VERSION 5.8 ;
BUSBITCHARS "[]" ;
DIVIDERCHAR "/" ;
UNITS
    DATABASE MICRONS 2000 ;
END UNITS

VIA adder_tester_via1_2_3200_1200_1_3_1040_1040
  VIARULE Via1_GEN_HH ;
  CUTSIZE 0.26 0.26 ;
  LAYERS Metal1 Via1 Metal2 ;
  CUTSPACING 0.26 0.26 ;
  ENCLOSURE 0.06 0.17 0.01 0.06 ;
  ROWCOL 1 3 ;
END adder_tester_via1_2_3200_1200_1_3_1040_1040

VIA adder_tester_via2_3_3200_1200_1_3_1040_1040
  VIARULE Via2_GEN_HH ;
  CUTSIZE 0.26 0.26 ;
  LAYERS Metal2 Via2 Metal3 ;
  CUTSPACING 0.26 0.26 ;
  ENCLOSURE 0.01 0.06 0.06 0.01 ;
  ROWCOL 1 3 ;
END adder_tester_via2_3_3200_1200_1_3_1040_1040

VIA adder_tester_via3_4_3200_1200_1_3_1040_1040
  VIARULE Via3_GEN_HH ;
  CUTSIZE 0.26 0.26 ;
  LAYERS Metal3 Via3 Metal4 ;
  CUTSPACING 0.26 0.26 ;
  ENCLOSURE 0.06 0.01 0.15 0.06 ;
  ROWCOL 1 3 ;
END adder_tester_via3_4_3200_1200_1_3_1040_1040

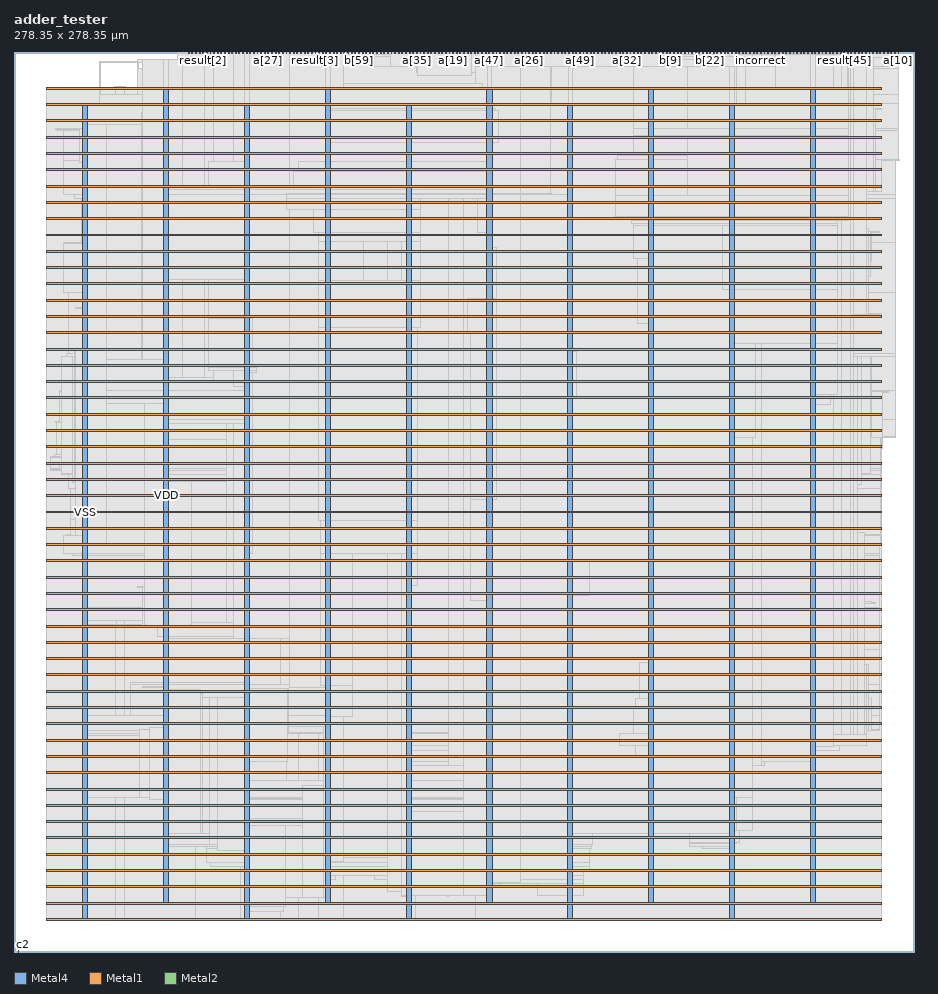
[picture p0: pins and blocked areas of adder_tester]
MACRO adder_tester
  FOREIGN adder_tester 0 0 ;
  CLASS BLOCK ;
  SIZE 278.35 BY 278.35 ;
  PIN VDD
    USE POWER ;
    DIRECTION INOUT ;
    PORT
      LAYER Metal4 ;
        RECT  246.28 14.82 247.88 267.42 ;
        RECT  196.28 14.82 197.88 267.42 ;
        RECT  146.28 14.82 147.88 267.42 ;
        RECT  96.28 14.82 97.88 267.42 ;
        RECT  46.28 14.82 47.88 267.42 ;
      LAYER Metal1 ;
        RECT  10.08 266.82 268.24 267.42 ;
        RECT  10.08 256.74 268.24 257.34 ;
        RECT  10.08 246.66 268.24 247.26 ;
        RECT  10.08 236.58 268.24 237.18 ;
        RECT  10.08 226.5 268.24 227.1 ;
        RECT  10.08 216.42 268.24 217.02 ;
        RECT  10.08 206.34 268.24 206.94 ;
        RECT  10.08 196.26 268.24 196.86 ;
        RECT  10.08 186.18 268.24 186.78 ;
        RECT  10.08 176.1 268.24 176.7 ;
        RECT  10.08 166.02 268.24 166.62 ;
        RECT  10.08 155.94 268.24 156.54 ;
        RECT  10.08 145.86 268.24 146.46 ;
        RECT  10.08 135.78 268.24 136.38 ;
        RECT  10.08 125.7 268.24 126.3 ;
        RECT  10.08 115.62 268.24 116.22 ;
        RECT  10.08 105.54 268.24 106.14 ;
        RECT  10.08 95.46 268.24 96.06 ;
        RECT  10.08 85.38 268.24 85.98 ;
        RECT  10.08 75.3 268.24 75.9 ;
        RECT  10.08 65.22 268.24 65.82 ;
        RECT  10.08 55.14 268.24 55.74 ;
        RECT  10.08 45.06 268.24 45.66 ;
        RECT  10.08 34.98 268.24 35.58 ;
        RECT  10.08 24.9 268.24 25.5 ;
        RECT  10.08 14.82 268.24 15.42 ;
      VIA 247.08 267.12 adder_tester_via3_4_3200_1200_1_3_1040_1040 ;
      VIA 247.08 267.12 adder_tester_via2_3_3200_1200_1_3_1040_1040 ;
      VIA 247.08 267.12 adder_tester_via1_2_3200_1200_1_3_1040_1040 ;
      VIA 247.08 257.04 adder_tester_via3_4_3200_1200_1_3_1040_1040 ;
      VIA 247.08 257.04 adder_tester_via2_3_3200_1200_1_3_1040_1040 ;
      VIA 247.08 257.04 adder_tester_via1_2_3200_1200_1_3_1040_1040 ;
      VIA 247.08 246.96 adder_tester_via3_4_3200_1200_1_3_1040_1040 ;
      VIA 247.08 246.96 adder_tester_via2_3_3200_1200_1_3_1040_1040 ;
      VIA 247.08 246.96 adder_tester_via1_2_3200_1200_1_3_1040_1040 ;
      VIA 247.08 236.88 adder_tester_via3_4_3200_1200_1_3_1040_1040 ;
      VIA 247.08 236.88 adder_tester_via2_3_3200_1200_1_3_1040_1040 ;
      VIA 247.08 236.88 adder_tester_via1_2_3200_1200_1_3_1040_1040 ;
      VIA 247.08 226.8 adder_tester_via3_4_3200_1200_1_3_1040_1040 ;
      VIA 247.08 226.8 adder_tester_via2_3_3200_1200_1_3_1040_1040 ;
      VIA 247.08 226.8 adder_tester_via1_2_3200_1200_1_3_1040_1040 ;
      VIA 247.08 216.72 adder_tester_via3_4_3200_1200_1_3_1040_1040 ;
      VIA 247.08 216.72 adder_tester_via2_3_3200_1200_1_3_1040_1040 ;
      VIA 247.08 216.72 adder_tester_via1_2_3200_1200_1_3_1040_1040 ;
      VIA 247.08 206.64 adder_tester_via3_4_3200_1200_1_3_1040_1040 ;
      VIA 247.08 206.64 adder_tester_via2_3_3200_1200_1_3_1040_1040 ;
      VIA 247.08 206.64 adder_tester_via1_2_3200_1200_1_3_1040_1040 ;
      VIA 247.08 196.56 adder_tester_via3_4_3200_1200_1_3_1040_1040 ;
      VIA 247.08 196.56 adder_tester_via2_3_3200_1200_1_3_1040_1040 ;
      VIA 247.08 196.56 adder_tester_via1_2_3200_1200_1_3_1040_1040 ;
      VIA 247.08 186.48 adder_tester_via3_4_3200_1200_1_3_1040_1040 ;
      VIA 247.08 186.48 adder_tester_via2_3_3200_1200_1_3_1040_1040 ;
      VIA 247.08 186.48 adder_tester_via1_2_3200_1200_1_3_1040_1040 ;
      VIA 247.08 176.4 adder_tester_via3_4_3200_1200_1_3_1040_1040 ;
      VIA 247.08 176.4 adder_tester_via2_3_3200_1200_1_3_1040_1040 ;
      VIA 247.08 176.4 adder_tester_via1_2_3200_1200_1_3_1040_1040 ;
      VIA 247.08 166.32 adder_tester_via3_4_3200_1200_1_3_1040_1040 ;
      VIA 247.08 166.32 adder_tester_via2_3_3200_1200_1_3_1040_1040 ;
      VIA 247.08 166.32 adder_tester_via1_2_3200_1200_1_3_1040_1040 ;
      VIA 247.08 156.24 adder_tester_via3_4_3200_1200_1_3_1040_1040 ;
      VIA 247.08 156.24 adder_tester_via2_3_3200_1200_1_3_1040_1040 ;
      VIA 247.08 156.24 adder_tester_via1_2_3200_1200_1_3_1040_1040 ;
      VIA 247.08 146.16 adder_tester_via3_4_3200_1200_1_3_1040_1040 ;
      VIA 247.08 146.16 adder_tester_via2_3_3200_1200_1_3_1040_1040 ;
      VIA 247.08 146.16 adder_tester_via1_2_3200_1200_1_3_1040_1040 ;
      VIA 247.08 136.08 adder_tester_via3_4_3200_1200_1_3_1040_1040 ;
      VIA 247.08 136.08 adder_tester_via2_3_3200_1200_1_3_1040_1040 ;
      VIA 247.08 136.08 adder_tester_via1_2_3200_1200_1_3_1040_1040 ;
      VIA 247.08 126 adder_tester_via3_4_3200_1200_1_3_1040_1040 ;
      VIA 247.08 126 adder_tester_via2_3_3200_1200_1_3_1040_1040 ;
      VIA 247.08 126 adder_tester_via1_2_3200_1200_1_3_1040_1040 ;
      VIA 247.08 115.92 adder_tester_via3_4_3200_1200_1_3_1040_1040 ;
      VIA 247.08 115.92 adder_tester_via2_3_3200_1200_1_3_1040_1040 ;
      VIA 247.08 115.92 adder_tester_via1_2_3200_1200_1_3_1040_1040 ;
      VIA 247.08 105.84 adder_tester_via3_4_3200_1200_1_3_1040_1040 ;
      VIA 247.08 105.84 adder_tester_via2_3_3200_1200_1_3_1040_1040 ;
      VIA 247.08 105.84 adder_tester_via1_2_3200_1200_1_3_1040_1040 ;
      VIA 247.08 95.76 adder_tester_via3_4_3200_1200_1_3_1040_1040 ;
      VIA 247.08 95.76 adder_tester_via2_3_3200_1200_1_3_1040_1040 ;
      VIA 247.08 95.76 adder_tester_via1_2_3200_1200_1_3_1040_1040 ;
      VIA 247.08 85.68 adder_tester_via3_4_3200_1200_1_3_1040_1040 ;
      VIA 247.08 85.68 adder_tester_via2_3_3200_1200_1_3_1040_1040 ;
      VIA 247.08 85.68 adder_tester_via1_2_3200_1200_1_3_1040_1040 ;
      VIA 247.08 75.6 adder_tester_via3_4_3200_1200_1_3_1040_1040 ;
      VIA 247.08 75.6 adder_tester_via2_3_3200_1200_1_3_1040_1040 ;
      VIA 247.08 75.6 adder_tester_via1_2_3200_1200_1_3_1040_1040 ;
      VIA 247.08 65.52 adder_tester_via3_4_3200_1200_1_3_1040_1040 ;
      VIA 247.08 65.52 adder_tester_via2_3_3200_1200_1_3_1040_1040 ;
      VIA 247.08 65.52 adder_tester_via1_2_3200_1200_1_3_1040_1040 ;
      VIA 247.08 55.44 adder_tester_via3_4_3200_1200_1_3_1040_1040 ;
      VIA 247.08 55.44 adder_tester_via2_3_3200_1200_1_3_1040_1040 ;
      VIA 247.08 55.44 adder_tester_via1_2_3200_1200_1_3_1040_1040 ;
      VIA 247.08 45.36 adder_tester_via3_4_3200_1200_1_3_1040_1040 ;
      VIA 247.08 45.36 adder_tester_via2_3_3200_1200_1_3_1040_1040 ;
      VIA 247.08 45.36 adder_tester_via1_2_3200_1200_1_3_1040_1040 ;
      VIA 247.08 35.28 adder_tester_via3_4_3200_1200_1_3_1040_1040 ;
      VIA 247.08 35.28 adder_tester_via2_3_3200_1200_1_3_1040_1040 ;
      VIA 247.08 35.28 adder_tester_via1_2_3200_1200_1_3_1040_1040 ;
      VIA 247.08 25.2 adder_tester_via3_4_3200_1200_1_3_1040_1040 ;
      VIA 247.08 25.2 adder_tester_via2_3_3200_1200_1_3_1040_1040 ;
      VIA 247.08 25.2 adder_tester_via1_2_3200_1200_1_3_1040_1040 ;
      VIA 247.08 15.12 adder_tester_via3_4_3200_1200_1_3_1040_1040 ;
      VIA 247.08 15.12 adder_tester_via2_3_3200_1200_1_3_1040_1040 ;
      VIA 247.08 15.12 adder_tester_via1_2_3200_1200_1_3_1040_1040 ;
      VIA 197.08 267.12 adder_tester_via3_4_3200_1200_1_3_1040_1040 ;
      VIA 197.08 267.12 adder_tester_via2_3_3200_1200_1_3_1040_1040 ;
      VIA 197.08 267.12 adder_tester_via1_2_3200_1200_1_3_1040_1040 ;
      VIA 197.08 257.04 adder_tester_via3_4_3200_1200_1_3_1040_1040 ;
      VIA 197.08 257.04 adder_tester_via2_3_3200_1200_1_3_1040_1040 ;
      VIA 197.08 257.04 adder_tester_via1_2_3200_1200_1_3_1040_1040 ;
      VIA 197.08 246.96 adder_tester_via3_4_3200_1200_1_3_1040_1040 ;
      VIA 197.08 246.96 adder_tester_via2_3_3200_1200_1_3_1040_1040 ;
      VIA 197.08 246.96 adder_tester_via1_2_3200_1200_1_3_1040_1040 ;
      VIA 197.08 236.88 adder_tester_via3_4_3200_1200_1_3_1040_1040 ;
      VIA 197.08 236.88 adder_tester_via2_3_3200_1200_1_3_1040_1040 ;
      VIA 197.08 236.88 adder_tester_via1_2_3200_1200_1_3_1040_1040 ;
      VIA 197.08 226.8 adder_tester_via3_4_3200_1200_1_3_1040_1040 ;
      VIA 197.08 226.8 adder_tester_via2_3_3200_1200_1_3_1040_1040 ;
      VIA 197.08 226.8 adder_tester_via1_2_3200_1200_1_3_1040_1040 ;
      VIA 197.08 216.72 adder_tester_via3_4_3200_1200_1_3_1040_1040 ;
      VIA 197.08 216.72 adder_tester_via2_3_3200_1200_1_3_1040_1040 ;
      VIA 197.08 216.72 adder_tester_via1_2_3200_1200_1_3_1040_1040 ;
      VIA 197.08 206.64 adder_tester_via3_4_3200_1200_1_3_1040_1040 ;
      VIA 197.08 206.64 adder_tester_via2_3_3200_1200_1_3_1040_1040 ;
      VIA 197.08 206.64 adder_tester_via1_2_3200_1200_1_3_1040_1040 ;
      VIA 197.08 196.56 adder_tester_via3_4_3200_1200_1_3_1040_1040 ;
      VIA 197.08 196.56 adder_tester_via2_3_3200_1200_1_3_1040_1040 ;
      VIA 197.08 196.56 adder_tester_via1_2_3200_1200_1_3_1040_1040 ;
      VIA 197.08 186.48 adder_tester_via3_4_3200_1200_1_3_1040_1040 ;
      VIA 197.08 186.48 adder_tester_via2_3_3200_1200_1_3_1040_1040 ;
      VIA 197.08 186.48 adder_tester_via1_2_3200_1200_1_3_1040_1040 ;
      VIA 197.08 176.4 adder_tester_via3_4_3200_1200_1_3_1040_1040 ;
      VIA 197.08 176.4 adder_tester_via2_3_3200_1200_1_3_1040_1040 ;
      VIA 197.08 176.4 adder_tester_via1_2_3200_1200_1_3_1040_1040 ;
      VIA 197.08 166.32 adder_tester_via3_4_3200_1200_1_3_1040_1040 ;
      VIA 197.08 166.32 adder_tester_via2_3_3200_1200_1_3_1040_1040 ;
      VIA 197.08 166.32 adder_tester_via1_2_3200_1200_1_3_1040_1040 ;
      VIA 197.08 156.24 adder_tester_via3_4_3200_1200_1_3_1040_1040 ;
      VIA 197.08 156.24 adder_tester_via2_3_3200_1200_1_3_1040_1040 ;
      VIA 197.08 156.24 adder_tester_via1_2_3200_1200_1_3_1040_1040 ;
      VIA 197.08 146.16 adder_tester_via3_4_3200_1200_1_3_1040_1040 ;
      VIA 197.08 146.16 adder_tester_via2_3_3200_1200_1_3_1040_1040 ;
      VIA 197.08 146.16 adder_tester_via1_2_3200_1200_1_3_1040_1040 ;
      VIA 197.08 136.08 adder_tester_via3_4_3200_1200_1_3_1040_1040 ;
      VIA 197.08 136.08 adder_tester_via2_3_3200_1200_1_3_1040_1040 ;
      VIA 197.08 136.08 adder_tester_via1_2_3200_1200_1_3_1040_1040 ;
      VIA 197.08 126 adder_tester_via3_4_3200_1200_1_3_1040_1040 ;
      VIA 197.08 126 adder_tester_via2_3_3200_1200_1_3_1040_1040 ;
      VIA 197.08 126 adder_tester_via1_2_3200_1200_1_3_1040_1040 ;
      VIA 197.08 115.92 adder_tester_via3_4_3200_1200_1_3_1040_1040 ;
      VIA 197.08 115.92 adder_tester_via2_3_3200_1200_1_3_1040_1040 ;
      VIA 197.08 115.92 adder_tester_via1_2_3200_1200_1_3_1040_1040 ;
      VIA 197.08 105.84 adder_tester_via3_4_3200_1200_1_3_1040_1040 ;
      VIA 197.08 105.84 adder_tester_via2_3_3200_1200_1_3_1040_1040 ;
      VIA 197.08 105.84 adder_tester_via1_2_3200_1200_1_3_1040_1040 ;
      VIA 197.08 95.76 adder_tester_via3_4_3200_1200_1_3_1040_1040 ;
      VIA 197.08 95.76 adder_tester_via2_3_3200_1200_1_3_1040_1040 ;
      VIA 197.08 95.76 adder_tester_via1_2_3200_1200_1_3_1040_1040 ;
      VIA 197.08 85.68 adder_tester_via3_4_3200_1200_1_3_1040_1040 ;
      VIA 197.08 85.68 adder_tester_via2_3_3200_1200_1_3_1040_1040 ;
      VIA 197.08 85.68 adder_tester_via1_2_3200_1200_1_3_1040_1040 ;
      VIA 197.08 75.6 adder_tester_via3_4_3200_1200_1_3_1040_1040 ;
      VIA 197.08 75.6 adder_tester_via2_3_3200_1200_1_3_1040_1040 ;
      VIA 197.08 75.6 adder_tester_via1_2_3200_1200_1_3_1040_1040 ;
      VIA 197.08 65.52 adder_tester_via3_4_3200_1200_1_3_1040_1040 ;
      VIA 197.08 65.52 adder_tester_via2_3_3200_1200_1_3_1040_1040 ;
      VIA 197.08 65.52 adder_tester_via1_2_3200_1200_1_3_1040_1040 ;
      VIA 197.08 55.44 adder_tester_via3_4_3200_1200_1_3_1040_1040 ;
      VIA 197.08 55.44 adder_tester_via2_3_3200_1200_1_3_1040_1040 ;
      VIA 197.08 55.44 adder_tester_via1_2_3200_1200_1_3_1040_1040 ;
      VIA 197.08 45.36 adder_tester_via3_4_3200_1200_1_3_1040_1040 ;
      VIA 197.08 45.36 adder_tester_via2_3_3200_1200_1_3_1040_1040 ;
      VIA 197.08 45.36 adder_tester_via1_2_3200_1200_1_3_1040_1040 ;
      VIA 197.08 35.28 adder_tester_via3_4_3200_1200_1_3_1040_1040 ;
      VIA 197.08 35.28 adder_tester_via2_3_3200_1200_1_3_1040_1040 ;
      VIA 197.08 35.28 adder_tester_via1_2_3200_1200_1_3_1040_1040 ;
      VIA 197.08 25.2 adder_tester_via3_4_3200_1200_1_3_1040_1040 ;
      VIA 197.08 25.2 adder_tester_via2_3_3200_1200_1_3_1040_1040 ;
      VIA 197.08 25.2 adder_tester_via1_2_3200_1200_1_3_1040_1040 ;
      VIA 197.08 15.12 adder_tester_via3_4_3200_1200_1_3_1040_1040 ;
      VIA 197.08 15.12 adder_tester_via2_3_3200_1200_1_3_1040_1040 ;
      VIA 197.08 15.12 adder_tester_via1_2_3200_1200_1_3_1040_1040 ;
      VIA 147.08 267.12 adder_tester_via3_4_3200_1200_1_3_1040_1040 ;
      VIA 147.08 267.12 adder_tester_via2_3_3200_1200_1_3_1040_1040 ;
      VIA 147.08 267.12 adder_tester_via1_2_3200_1200_1_3_1040_1040 ;
      VIA 147.08 257.04 adder_tester_via3_4_3200_1200_1_3_1040_1040 ;
      VIA 147.08 257.04 adder_tester_via2_3_3200_1200_1_3_1040_1040 ;
      VIA 147.08 257.04 adder_tester_via1_2_3200_1200_1_3_1040_1040 ;
      VIA 147.08 246.96 adder_tester_via3_4_3200_1200_1_3_1040_1040 ;
      VIA 147.08 246.96 adder_tester_via2_3_3200_1200_1_3_1040_1040 ;
      VIA 147.08 246.96 adder_tester_via1_2_3200_1200_1_3_1040_1040 ;
      VIA 147.08 236.88 adder_tester_via3_4_3200_1200_1_3_1040_1040 ;
      VIA 147.08 236.88 adder_tester_via2_3_3200_1200_1_3_1040_1040 ;
      VIA 147.08 236.88 adder_tester_via1_2_3200_1200_1_3_1040_1040 ;
      VIA 147.08 226.8 adder_tester_via3_4_3200_1200_1_3_1040_1040 ;
      VIA 147.08 226.8 adder_tester_via2_3_3200_1200_1_3_1040_1040 ;
      VIA 147.08 226.8 adder_tester_via1_2_3200_1200_1_3_1040_1040 ;
      VIA 147.08 216.72 adder_tester_via3_4_3200_1200_1_3_1040_1040 ;
      VIA 147.08 216.72 adder_tester_via2_3_3200_1200_1_3_1040_1040 ;
      VIA 147.08 216.72 adder_tester_via1_2_3200_1200_1_3_1040_1040 ;
      VIA 147.08 206.64 adder_tester_via3_4_3200_1200_1_3_1040_1040 ;
      VIA 147.08 206.64 adder_tester_via2_3_3200_1200_1_3_1040_1040 ;
      VIA 147.08 206.64 adder_tester_via1_2_3200_1200_1_3_1040_1040 ;
      VIA 147.08 196.56 adder_tester_via3_4_3200_1200_1_3_1040_1040 ;
      VIA 147.08 196.56 adder_tester_via2_3_3200_1200_1_3_1040_1040 ;
      VIA 147.08 196.56 adder_tester_via1_2_3200_1200_1_3_1040_1040 ;
      VIA 147.08 186.48 adder_tester_via3_4_3200_1200_1_3_1040_1040 ;
      VIA 147.08 186.48 adder_tester_via2_3_3200_1200_1_3_1040_1040 ;
      VIA 147.08 186.48 adder_tester_via1_2_3200_1200_1_3_1040_1040 ;
      VIA 147.08 176.4 adder_tester_via3_4_3200_1200_1_3_1040_1040 ;
      VIA 147.08 176.4 adder_tester_via2_3_3200_1200_1_3_1040_1040 ;
      VIA 147.08 176.4 adder_tester_via1_2_3200_1200_1_3_1040_1040 ;
      VIA 147.08 166.32 adder_tester_via3_4_3200_1200_1_3_1040_1040 ;
      VIA 147.08 166.32 adder_tester_via2_3_3200_1200_1_3_1040_1040 ;
      VIA 147.08 166.32 adder_tester_via1_2_3200_1200_1_3_1040_1040 ;
      VIA 147.08 156.24 adder_tester_via3_4_3200_1200_1_3_1040_1040 ;
      VIA 147.08 156.24 adder_tester_via2_3_3200_1200_1_3_1040_1040 ;
      VIA 147.08 156.24 adder_tester_via1_2_3200_1200_1_3_1040_1040 ;
      VIA 147.08 146.16 adder_tester_via3_4_3200_1200_1_3_1040_1040 ;
      VIA 147.08 146.16 adder_tester_via2_3_3200_1200_1_3_1040_1040 ;
      VIA 147.08 146.16 adder_tester_via1_2_3200_1200_1_3_1040_1040 ;
      VIA 147.08 136.08 adder_tester_via3_4_3200_1200_1_3_1040_1040 ;
      VIA 147.08 136.08 adder_tester_via2_3_3200_1200_1_3_1040_1040 ;
      VIA 147.08 136.08 adder_tester_via1_2_3200_1200_1_3_1040_1040 ;
      VIA 147.08 126 adder_tester_via3_4_3200_1200_1_3_1040_1040 ;
      VIA 147.08 126 adder_tester_via2_3_3200_1200_1_3_1040_1040 ;
      VIA 147.08 126 adder_tester_via1_2_3200_1200_1_3_1040_1040 ;
      VIA 147.08 115.92 adder_tester_via3_4_3200_1200_1_3_1040_1040 ;
      VIA 147.08 115.92 adder_tester_via2_3_3200_1200_1_3_1040_1040 ;
      VIA 147.08 115.92 adder_tester_via1_2_3200_1200_1_3_1040_1040 ;
      VIA 147.08 105.84 adder_tester_via3_4_3200_1200_1_3_1040_1040 ;
      VIA 147.08 105.84 adder_tester_via2_3_3200_1200_1_3_1040_1040 ;
      VIA 147.08 105.84 adder_tester_via1_2_3200_1200_1_3_1040_1040 ;
      VIA 147.08 95.76 adder_tester_via3_4_3200_1200_1_3_1040_1040 ;
      VIA 147.08 95.76 adder_tester_via2_3_3200_1200_1_3_1040_1040 ;
      VIA 147.08 95.76 adder_tester_via1_2_3200_1200_1_3_1040_1040 ;
      VIA 147.08 85.68 adder_tester_via3_4_3200_1200_1_3_1040_1040 ;
      VIA 147.08 85.68 adder_tester_via2_3_3200_1200_1_3_1040_1040 ;
      VIA 147.08 85.68 adder_tester_via1_2_3200_1200_1_3_1040_1040 ;
      VIA 147.08 75.6 adder_tester_via3_4_3200_1200_1_3_1040_1040 ;
      VIA 147.08 75.6 adder_tester_via2_3_3200_1200_1_3_1040_1040 ;
      VIA 147.08 75.6 adder_tester_via1_2_3200_1200_1_3_1040_1040 ;
      VIA 147.08 65.52 adder_tester_via3_4_3200_1200_1_3_1040_1040 ;
      VIA 147.08 65.52 adder_tester_via2_3_3200_1200_1_3_1040_1040 ;
      VIA 147.08 65.52 adder_tester_via1_2_3200_1200_1_3_1040_1040 ;
      VIA 147.08 55.44 adder_tester_via3_4_3200_1200_1_3_1040_1040 ;
      VIA 147.08 55.44 adder_tester_via2_3_3200_1200_1_3_1040_1040 ;
      VIA 147.08 55.44 adder_tester_via1_2_3200_1200_1_3_1040_1040 ;
      VIA 147.08 45.36 adder_tester_via3_4_3200_1200_1_3_1040_1040 ;
      VIA 147.08 45.36 adder_tester_via2_3_3200_1200_1_3_1040_1040 ;
      VIA 147.08 45.36 adder_tester_via1_2_3200_1200_1_3_1040_1040 ;
      VIA 147.08 35.28 adder_tester_via3_4_3200_1200_1_3_1040_1040 ;
      VIA 147.08 35.28 adder_tester_via2_3_3200_1200_1_3_1040_1040 ;
      VIA 147.08 35.28 adder_tester_via1_2_3200_1200_1_3_1040_1040 ;
      VIA 147.08 25.2 adder_tester_via3_4_3200_1200_1_3_1040_1040 ;
      VIA 147.08 25.2 adder_tester_via2_3_3200_1200_1_3_1040_1040 ;
      VIA 147.08 25.2 adder_tester_via1_2_3200_1200_1_3_1040_1040 ;
      VIA 147.08 15.12 adder_tester_via3_4_3200_1200_1_3_1040_1040 ;
      VIA 147.08 15.12 adder_tester_via2_3_3200_1200_1_3_1040_1040 ;
      VIA 147.08 15.12 adder_tester_via1_2_3200_1200_1_3_1040_1040 ;
      VIA 97.08 267.12 adder_tester_via3_4_3200_1200_1_3_1040_1040 ;
      VIA 97.08 267.12 adder_tester_via2_3_3200_1200_1_3_1040_1040 ;
      VIA 97.08 267.12 adder_tester_via1_2_3200_1200_1_3_1040_1040 ;
      VIA 97.08 257.04 adder_tester_via3_4_3200_1200_1_3_1040_1040 ;
      VIA 97.08 257.04 adder_tester_via2_3_3200_1200_1_3_1040_1040 ;
      VIA 97.08 257.04 adder_tester_via1_2_3200_1200_1_3_1040_1040 ;
      VIA 97.08 246.96 adder_tester_via3_4_3200_1200_1_3_1040_1040 ;
      VIA 97.08 246.96 adder_tester_via2_3_3200_1200_1_3_1040_1040 ;
      VIA 97.08 246.96 adder_tester_via1_2_3200_1200_1_3_1040_1040 ;
      VIA 97.08 236.88 adder_tester_via3_4_3200_1200_1_3_1040_1040 ;
      VIA 97.08 236.88 adder_tester_via2_3_3200_1200_1_3_1040_1040 ;
      VIA 97.08 236.88 adder_tester_via1_2_3200_1200_1_3_1040_1040 ;
      VIA 97.08 226.8 adder_tester_via3_4_3200_1200_1_3_1040_1040 ;
      VIA 97.08 226.8 adder_tester_via2_3_3200_1200_1_3_1040_1040 ;
      VIA 97.08 226.8 adder_tester_via1_2_3200_1200_1_3_1040_1040 ;
      VIA 97.08 216.72 adder_tester_via3_4_3200_1200_1_3_1040_1040 ;
      VIA 97.08 216.72 adder_tester_via2_3_3200_1200_1_3_1040_1040 ;
      VIA 97.08 216.72 adder_tester_via1_2_3200_1200_1_3_1040_1040 ;
      VIA 97.08 206.64 adder_tester_via3_4_3200_1200_1_3_1040_1040 ;
      VIA 97.08 206.64 adder_tester_via2_3_3200_1200_1_3_1040_1040 ;
      VIA 97.08 206.64 adder_tester_via1_2_3200_1200_1_3_1040_1040 ;
      VIA 97.08 196.56 adder_tester_via3_4_3200_1200_1_3_1040_1040 ;
      VIA 97.08 196.56 adder_tester_via2_3_3200_1200_1_3_1040_1040 ;
      VIA 97.08 196.56 adder_tester_via1_2_3200_1200_1_3_1040_1040 ;
      VIA 97.08 186.48 adder_tester_via3_4_3200_1200_1_3_1040_1040 ;
      VIA 97.08 186.48 adder_tester_via2_3_3200_1200_1_3_1040_1040 ;
      VIA 97.08 186.48 adder_tester_via1_2_3200_1200_1_3_1040_1040 ;
      VIA 97.08 176.4 adder_tester_via3_4_3200_1200_1_3_1040_1040 ;
      VIA 97.08 176.4 adder_tester_via2_3_3200_1200_1_3_1040_1040 ;
      VIA 97.08 176.4 adder_tester_via1_2_3200_1200_1_3_1040_1040 ;
      VIA 97.08 166.32 adder_tester_via3_4_3200_1200_1_3_1040_1040 ;
      VIA 97.08 166.32 adder_tester_via2_3_3200_1200_1_3_1040_1040 ;
      VIA 97.08 166.32 adder_tester_via1_2_3200_1200_1_3_1040_1040 ;
      VIA 97.08 156.24 adder_tester_via3_4_3200_1200_1_3_1040_1040 ;
      VIA 97.08 156.24 adder_tester_via2_3_3200_1200_1_3_1040_1040 ;
      VIA 97.08 156.24 adder_tester_via1_2_3200_1200_1_3_1040_1040 ;
      VIA 97.08 146.16 adder_tester_via3_4_3200_1200_1_3_1040_1040 ;
      VIA 97.08 146.16 adder_tester_via2_3_3200_1200_1_3_1040_1040 ;
      VIA 97.08 146.16 adder_tester_via1_2_3200_1200_1_3_1040_1040 ;
      VIA 97.08 136.08 adder_tester_via3_4_3200_1200_1_3_1040_1040 ;
      VIA 97.08 136.08 adder_tester_via2_3_3200_1200_1_3_1040_1040 ;
      VIA 97.08 136.08 adder_tester_via1_2_3200_1200_1_3_1040_1040 ;
      VIA 97.08 126 adder_tester_via3_4_3200_1200_1_3_1040_1040 ;
      VIA 97.08 126 adder_tester_via2_3_3200_1200_1_3_1040_1040 ;
      VIA 97.08 126 adder_tester_via1_2_3200_1200_1_3_1040_1040 ;
      VIA 97.08 115.92 adder_tester_via3_4_3200_1200_1_3_1040_1040 ;
      VIA 97.08 115.92 adder_tester_via2_3_3200_1200_1_3_1040_1040 ;
      VIA 97.08 115.92 adder_tester_via1_2_3200_1200_1_3_1040_1040 ;
      VIA 97.08 105.84 adder_tester_via3_4_3200_1200_1_3_1040_1040 ;
      VIA 97.08 105.84 adder_tester_via2_3_3200_1200_1_3_1040_1040 ;
      VIA 97.08 105.84 adder_tester_via1_2_3200_1200_1_3_1040_1040 ;
      VIA 97.08 95.76 adder_tester_via3_4_3200_1200_1_3_1040_1040 ;
      VIA 97.08 95.76 adder_tester_via2_3_3200_1200_1_3_1040_1040 ;
      VIA 97.08 95.76 adder_tester_via1_2_3200_1200_1_3_1040_1040 ;
      VIA 97.08 85.68 adder_tester_via3_4_3200_1200_1_3_1040_1040 ;
      VIA 97.08 85.68 adder_tester_via2_3_3200_1200_1_3_1040_1040 ;
      VIA 97.08 85.68 adder_tester_via1_2_3200_1200_1_3_1040_1040 ;
      VIA 97.08 75.6 adder_tester_via3_4_3200_1200_1_3_1040_1040 ;
      VIA 97.08 75.6 adder_tester_via2_3_3200_1200_1_3_1040_1040 ;
      VIA 97.08 75.6 adder_tester_via1_2_3200_1200_1_3_1040_1040 ;
      VIA 97.08 65.52 adder_tester_via3_4_3200_1200_1_3_1040_1040 ;
      VIA 97.08 65.52 adder_tester_via2_3_3200_1200_1_3_1040_1040 ;
      VIA 97.08 65.52 adder_tester_via1_2_3200_1200_1_3_1040_1040 ;
      VIA 97.08 55.44 adder_tester_via3_4_3200_1200_1_3_1040_1040 ;
      VIA 97.08 55.44 adder_tester_via2_3_3200_1200_1_3_1040_1040 ;
      VIA 97.08 55.44 adder_tester_via1_2_3200_1200_1_3_1040_1040 ;
      VIA 97.08 45.36 adder_tester_via3_4_3200_1200_1_3_1040_1040 ;
      VIA 97.08 45.36 adder_tester_via2_3_3200_1200_1_3_1040_1040 ;
      VIA 97.08 45.36 adder_tester_via1_2_3200_1200_1_3_1040_1040 ;
      VIA 97.08 35.28 adder_tester_via3_4_3200_1200_1_3_1040_1040 ;
      VIA 97.08 35.28 adder_tester_via2_3_3200_1200_1_3_1040_1040 ;
      VIA 97.08 35.28 adder_tester_via1_2_3200_1200_1_3_1040_1040 ;
      VIA 97.08 25.2 adder_tester_via3_4_3200_1200_1_3_1040_1040 ;
      VIA 97.08 25.2 adder_tester_via2_3_3200_1200_1_3_1040_1040 ;
      VIA 97.08 25.2 adder_tester_via1_2_3200_1200_1_3_1040_1040 ;
      VIA 97.08 15.12 adder_tester_via3_4_3200_1200_1_3_1040_1040 ;
      VIA 97.08 15.12 adder_tester_via2_3_3200_1200_1_3_1040_1040 ;
      VIA 97.08 15.12 adder_tester_via1_2_3200_1200_1_3_1040_1040 ;
      VIA 47.08 267.12 adder_tester_via3_4_3200_1200_1_3_1040_1040 ;
      VIA 47.08 267.12 adder_tester_via2_3_3200_1200_1_3_1040_1040 ;
      VIA 47.08 267.12 adder_tester_via1_2_3200_1200_1_3_1040_1040 ;
      VIA 47.08 257.04 adder_tester_via3_4_3200_1200_1_3_1040_1040 ;
      VIA 47.08 257.04 adder_tester_via2_3_3200_1200_1_3_1040_1040 ;
      VIA 47.08 257.04 adder_tester_via1_2_3200_1200_1_3_1040_1040 ;
      VIA 47.08 246.96 adder_tester_via3_4_3200_1200_1_3_1040_1040 ;
      VIA 47.08 246.96 adder_tester_via2_3_3200_1200_1_3_1040_1040 ;
      VIA 47.08 246.96 adder_tester_via1_2_3200_1200_1_3_1040_1040 ;
      VIA 47.08 236.88 adder_tester_via3_4_3200_1200_1_3_1040_1040 ;
      VIA 47.08 236.88 adder_tester_via2_3_3200_1200_1_3_1040_1040 ;
      VIA 47.08 236.88 adder_tester_via1_2_3200_1200_1_3_1040_1040 ;
      VIA 47.08 226.8 adder_tester_via3_4_3200_1200_1_3_1040_1040 ;
      VIA 47.08 226.8 adder_tester_via2_3_3200_1200_1_3_1040_1040 ;
      VIA 47.08 226.8 adder_tester_via1_2_3200_1200_1_3_1040_1040 ;
      VIA 47.08 216.72 adder_tester_via3_4_3200_1200_1_3_1040_1040 ;
      VIA 47.08 216.72 adder_tester_via2_3_3200_1200_1_3_1040_1040 ;
      VIA 47.08 216.72 adder_tester_via1_2_3200_1200_1_3_1040_1040 ;
      VIA 47.08 206.64 adder_tester_via3_4_3200_1200_1_3_1040_1040 ;
      VIA 47.08 206.64 adder_tester_via2_3_3200_1200_1_3_1040_1040 ;
      VIA 47.08 206.64 adder_tester_via1_2_3200_1200_1_3_1040_1040 ;
      VIA 47.08 196.56 adder_tester_via3_4_3200_1200_1_3_1040_1040 ;
      VIA 47.08 196.56 adder_tester_via2_3_3200_1200_1_3_1040_1040 ;
      VIA 47.08 196.56 adder_tester_via1_2_3200_1200_1_3_1040_1040 ;
      VIA 47.08 186.48 adder_tester_via3_4_3200_1200_1_3_1040_1040 ;
      VIA 47.08 186.48 adder_tester_via2_3_3200_1200_1_3_1040_1040 ;
      VIA 47.08 186.48 adder_tester_via1_2_3200_1200_1_3_1040_1040 ;
      VIA 47.08 176.4 adder_tester_via3_4_3200_1200_1_3_1040_1040 ;
      VIA 47.08 176.4 adder_tester_via2_3_3200_1200_1_3_1040_1040 ;
      VIA 47.08 176.4 adder_tester_via1_2_3200_1200_1_3_1040_1040 ;
      VIA 47.08 166.32 adder_tester_via3_4_3200_1200_1_3_1040_1040 ;
      VIA 47.08 166.32 adder_tester_via2_3_3200_1200_1_3_1040_1040 ;
      VIA 47.08 166.32 adder_tester_via1_2_3200_1200_1_3_1040_1040 ;
      VIA 47.08 156.24 adder_tester_via3_4_3200_1200_1_3_1040_1040 ;
      VIA 47.08 156.24 adder_tester_via2_3_3200_1200_1_3_1040_1040 ;
      VIA 47.08 156.24 adder_tester_via1_2_3200_1200_1_3_1040_1040 ;
      VIA 47.08 146.16 adder_tester_via3_4_3200_1200_1_3_1040_1040 ;
      VIA 47.08 146.16 adder_tester_via2_3_3200_1200_1_3_1040_1040 ;
      VIA 47.08 146.16 adder_tester_via1_2_3200_1200_1_3_1040_1040 ;
      VIA 47.08 136.08 adder_tester_via3_4_3200_1200_1_3_1040_1040 ;
      VIA 47.08 136.08 adder_tester_via2_3_3200_1200_1_3_1040_1040 ;
      VIA 47.08 136.08 adder_tester_via1_2_3200_1200_1_3_1040_1040 ;
      VIA 47.08 126 adder_tester_via3_4_3200_1200_1_3_1040_1040 ;
      VIA 47.08 126 adder_tester_via2_3_3200_1200_1_3_1040_1040 ;
      VIA 47.08 126 adder_tester_via1_2_3200_1200_1_3_1040_1040 ;
      VIA 47.08 115.92 adder_tester_via3_4_3200_1200_1_3_1040_1040 ;
      VIA 47.08 115.92 adder_tester_via2_3_3200_1200_1_3_1040_1040 ;
      VIA 47.08 115.92 adder_tester_via1_2_3200_1200_1_3_1040_1040 ;
      VIA 47.08 105.84 adder_tester_via3_4_3200_1200_1_3_1040_1040 ;
      VIA 47.08 105.84 adder_tester_via2_3_3200_1200_1_3_1040_1040 ;
      VIA 47.08 105.84 adder_tester_via1_2_3200_1200_1_3_1040_1040 ;
      VIA 47.08 95.76 adder_tester_via3_4_3200_1200_1_3_1040_1040 ;
      VIA 47.08 95.76 adder_tester_via2_3_3200_1200_1_3_1040_1040 ;
      VIA 47.08 95.76 adder_tester_via1_2_3200_1200_1_3_1040_1040 ;
      VIA 47.08 85.68 adder_tester_via3_4_3200_1200_1_3_1040_1040 ;
      VIA 47.08 85.68 adder_tester_via2_3_3200_1200_1_3_1040_1040 ;
      VIA 47.08 85.68 adder_tester_via1_2_3200_1200_1_3_1040_1040 ;
      VIA 47.08 75.6 adder_tester_via3_4_3200_1200_1_3_1040_1040 ;
      VIA 47.08 75.6 adder_tester_via2_3_3200_1200_1_3_1040_1040 ;
      VIA 47.08 75.6 adder_tester_via1_2_3200_1200_1_3_1040_1040 ;
      VIA 47.08 65.52 adder_tester_via3_4_3200_1200_1_3_1040_1040 ;
      VIA 47.08 65.52 adder_tester_via2_3_3200_1200_1_3_1040_1040 ;
      VIA 47.08 65.52 adder_tester_via1_2_3200_1200_1_3_1040_1040 ;
      VIA 47.08 55.44 adder_tester_via3_4_3200_1200_1_3_1040_1040 ;
      VIA 47.08 55.44 adder_tester_via2_3_3200_1200_1_3_1040_1040 ;
      VIA 47.08 55.44 adder_tester_via1_2_3200_1200_1_3_1040_1040 ;
      VIA 47.08 45.36 adder_tester_via3_4_3200_1200_1_3_1040_1040 ;
      VIA 47.08 45.36 adder_tester_via2_3_3200_1200_1_3_1040_1040 ;
      VIA 47.08 45.36 adder_tester_via1_2_3200_1200_1_3_1040_1040 ;
      VIA 47.08 35.28 adder_tester_via3_4_3200_1200_1_3_1040_1040 ;
      VIA 47.08 35.28 adder_tester_via2_3_3200_1200_1_3_1040_1040 ;
      VIA 47.08 35.28 adder_tester_via1_2_3200_1200_1_3_1040_1040 ;
      VIA 47.08 25.2 adder_tester_via3_4_3200_1200_1_3_1040_1040 ;
      VIA 47.08 25.2 adder_tester_via2_3_3200_1200_1_3_1040_1040 ;
      VIA 47.08 25.2 adder_tester_via1_2_3200_1200_1_3_1040_1040 ;
      VIA 47.08 15.12 adder_tester_via3_4_3200_1200_1_3_1040_1040 ;
      VIA 47.08 15.12 adder_tester_via2_3_3200_1200_1_3_1040_1040 ;
      VIA 47.08 15.12 adder_tester_via1_2_3200_1200_1_3_1040_1040 ;
    END
  END VDD
  PIN VSS
    USE GROUND ;
    DIRECTION INOUT ;
    PORT
      LAYER Metal4 ;
        RECT  221.28 9.78 222.88 262.38 ;
        RECT  171.28 9.78 172.88 262.38 ;
        RECT  121.28 9.78 122.88 262.38 ;
        RECT  71.28 9.78 72.88 262.38 ;
        RECT  21.28 9.78 22.88 262.38 ;
      LAYER Metal1 ;
        RECT  10.08 261.78 268.24 262.38 ;
        RECT  10.08 251.7 268.24 252.3 ;
        RECT  10.08 241.62 268.24 242.22 ;
        RECT  10.08 231.54 268.24 232.14 ;
        RECT  10.08 221.46 268.24 222.06 ;
        RECT  10.08 211.38 268.24 211.98 ;
        RECT  10.08 201.3 268.24 201.9 ;
        RECT  10.08 191.22 268.24 191.82 ;
        RECT  10.08 181.14 268.24 181.74 ;
        RECT  10.08 171.06 268.24 171.66 ;
        RECT  10.08 160.98 268.24 161.58 ;
        RECT  10.08 150.9 268.24 151.5 ;
        RECT  10.08 140.82 268.24 141.42 ;
        RECT  10.08 130.74 268.24 131.34 ;
        RECT  10.08 120.66 268.24 121.26 ;
        RECT  10.08 110.58 268.24 111.18 ;
        RECT  10.08 100.5 268.24 101.1 ;
        RECT  10.08 90.42 268.24 91.02 ;
        RECT  10.08 80.34 268.24 80.94 ;
        RECT  10.08 70.26 268.24 70.86 ;
        RECT  10.08 60.18 268.24 60.78 ;
        RECT  10.08 50.1 268.24 50.7 ;
        RECT  10.08 40.02 268.24 40.62 ;
        RECT  10.08 29.94 268.24 30.54 ;
        RECT  10.08 19.86 268.24 20.46 ;
        RECT  10.08 9.78 268.24 10.38 ;
      VIA 222.08 262.08 adder_tester_via3_4_3200_1200_1_3_1040_1040 ;
      VIA 222.08 262.08 adder_tester_via2_3_3200_1200_1_3_1040_1040 ;
      VIA 222.08 262.08 adder_tester_via1_2_3200_1200_1_3_1040_1040 ;
      VIA 222.08 252 adder_tester_via3_4_3200_1200_1_3_1040_1040 ;
      VIA 222.08 252 adder_tester_via2_3_3200_1200_1_3_1040_1040 ;
      VIA 222.08 252 adder_tester_via1_2_3200_1200_1_3_1040_1040 ;
      VIA 222.08 241.92 adder_tester_via3_4_3200_1200_1_3_1040_1040 ;
      VIA 222.08 241.92 adder_tester_via2_3_3200_1200_1_3_1040_1040 ;
      VIA 222.08 241.92 adder_tester_via1_2_3200_1200_1_3_1040_1040 ;
      VIA 222.08 231.84 adder_tester_via3_4_3200_1200_1_3_1040_1040 ;
      VIA 222.08 231.84 adder_tester_via2_3_3200_1200_1_3_1040_1040 ;
      VIA 222.08 231.84 adder_tester_via1_2_3200_1200_1_3_1040_1040 ;
      VIA 222.08 221.76 adder_tester_via3_4_3200_1200_1_3_1040_1040 ;
      VIA 222.08 221.76 adder_tester_via2_3_3200_1200_1_3_1040_1040 ;
      VIA 222.08 221.76 adder_tester_via1_2_3200_1200_1_3_1040_1040 ;
      VIA 222.08 211.68 adder_tester_via3_4_3200_1200_1_3_1040_1040 ;
      VIA 222.08 211.68 adder_tester_via2_3_3200_1200_1_3_1040_1040 ;
      VIA 222.08 211.68 adder_tester_via1_2_3200_1200_1_3_1040_1040 ;
      VIA 222.08 201.6 adder_tester_via3_4_3200_1200_1_3_1040_1040 ;
      VIA 222.08 201.6 adder_tester_via2_3_3200_1200_1_3_1040_1040 ;
      VIA 222.08 201.6 adder_tester_via1_2_3200_1200_1_3_1040_1040 ;
      VIA 222.08 191.52 adder_tester_via3_4_3200_1200_1_3_1040_1040 ;
      VIA 222.08 191.52 adder_tester_via2_3_3200_1200_1_3_1040_1040 ;
      VIA 222.08 191.52 adder_tester_via1_2_3200_1200_1_3_1040_1040 ;
      VIA 222.08 181.44 adder_tester_via3_4_3200_1200_1_3_1040_1040 ;
      VIA 222.08 181.44 adder_tester_via2_3_3200_1200_1_3_1040_1040 ;
      VIA 222.08 181.44 adder_tester_via1_2_3200_1200_1_3_1040_1040 ;
      VIA 222.08 171.36 adder_tester_via3_4_3200_1200_1_3_1040_1040 ;
      VIA 222.08 171.36 adder_tester_via2_3_3200_1200_1_3_1040_1040 ;
      VIA 222.08 171.36 adder_tester_via1_2_3200_1200_1_3_1040_1040 ;
      VIA 222.08 161.28 adder_tester_via3_4_3200_1200_1_3_1040_1040 ;
      VIA 222.08 161.28 adder_tester_via2_3_3200_1200_1_3_1040_1040 ;
      VIA 222.08 161.28 adder_tester_via1_2_3200_1200_1_3_1040_1040 ;
      VIA 222.08 151.2 adder_tester_via3_4_3200_1200_1_3_1040_1040 ;
      VIA 222.08 151.2 adder_tester_via2_3_3200_1200_1_3_1040_1040 ;
      VIA 222.08 151.2 adder_tester_via1_2_3200_1200_1_3_1040_1040 ;
      VIA 222.08 141.12 adder_tester_via3_4_3200_1200_1_3_1040_1040 ;
      VIA 222.08 141.12 adder_tester_via2_3_3200_1200_1_3_1040_1040 ;
      VIA 222.08 141.12 adder_tester_via1_2_3200_1200_1_3_1040_1040 ;
      VIA 222.08 131.04 adder_tester_via3_4_3200_1200_1_3_1040_1040 ;
      VIA 222.08 131.04 adder_tester_via2_3_3200_1200_1_3_1040_1040 ;
      VIA 222.08 131.04 adder_tester_via1_2_3200_1200_1_3_1040_1040 ;
      VIA 222.08 120.96 adder_tester_via3_4_3200_1200_1_3_1040_1040 ;
      VIA 222.08 120.96 adder_tester_via2_3_3200_1200_1_3_1040_1040 ;
      VIA 222.08 120.96 adder_tester_via1_2_3200_1200_1_3_1040_1040 ;
      VIA 222.08 110.88 adder_tester_via3_4_3200_1200_1_3_1040_1040 ;
      VIA 222.08 110.88 adder_tester_via2_3_3200_1200_1_3_1040_1040 ;
      VIA 222.08 110.88 adder_tester_via1_2_3200_1200_1_3_1040_1040 ;
      VIA 222.08 100.8 adder_tester_via3_4_3200_1200_1_3_1040_1040 ;
      VIA 222.08 100.8 adder_tester_via2_3_3200_1200_1_3_1040_1040 ;
      VIA 222.08 100.8 adder_tester_via1_2_3200_1200_1_3_1040_1040 ;
      VIA 222.08 90.72 adder_tester_via3_4_3200_1200_1_3_1040_1040 ;
      VIA 222.08 90.72 adder_tester_via2_3_3200_1200_1_3_1040_1040 ;
      VIA 222.08 90.72 adder_tester_via1_2_3200_1200_1_3_1040_1040 ;
      VIA 222.08 80.64 adder_tester_via3_4_3200_1200_1_3_1040_1040 ;
      VIA 222.08 80.64 adder_tester_via2_3_3200_1200_1_3_1040_1040 ;
      VIA 222.08 80.64 adder_tester_via1_2_3200_1200_1_3_1040_1040 ;
      VIA 222.08 70.56 adder_tester_via3_4_3200_1200_1_3_1040_1040 ;
      VIA 222.08 70.56 adder_tester_via2_3_3200_1200_1_3_1040_1040 ;
      VIA 222.08 70.56 adder_tester_via1_2_3200_1200_1_3_1040_1040 ;
      VIA 222.08 60.48 adder_tester_via3_4_3200_1200_1_3_1040_1040 ;
      VIA 222.08 60.48 adder_tester_via2_3_3200_1200_1_3_1040_1040 ;
      VIA 222.08 60.48 adder_tester_via1_2_3200_1200_1_3_1040_1040 ;
      VIA 222.08 50.4 adder_tester_via3_4_3200_1200_1_3_1040_1040 ;
      VIA 222.08 50.4 adder_tester_via2_3_3200_1200_1_3_1040_1040 ;
      VIA 222.08 50.4 adder_tester_via1_2_3200_1200_1_3_1040_1040 ;
      VIA 222.08 40.32 adder_tester_via3_4_3200_1200_1_3_1040_1040 ;
      VIA 222.08 40.32 adder_tester_via2_3_3200_1200_1_3_1040_1040 ;
      VIA 222.08 40.32 adder_tester_via1_2_3200_1200_1_3_1040_1040 ;
      VIA 222.08 30.24 adder_tester_via3_4_3200_1200_1_3_1040_1040 ;
      VIA 222.08 30.24 adder_tester_via2_3_3200_1200_1_3_1040_1040 ;
      VIA 222.08 30.24 adder_tester_via1_2_3200_1200_1_3_1040_1040 ;
      VIA 222.08 20.16 adder_tester_via3_4_3200_1200_1_3_1040_1040 ;
      VIA 222.08 20.16 adder_tester_via2_3_3200_1200_1_3_1040_1040 ;
      VIA 222.08 20.16 adder_tester_via1_2_3200_1200_1_3_1040_1040 ;
      VIA 222.08 10.08 adder_tester_via3_4_3200_1200_1_3_1040_1040 ;
      VIA 222.08 10.08 adder_tester_via2_3_3200_1200_1_3_1040_1040 ;
      VIA 222.08 10.08 adder_tester_via1_2_3200_1200_1_3_1040_1040 ;
      VIA 172.08 262.08 adder_tester_via3_4_3200_1200_1_3_1040_1040 ;
      VIA 172.08 262.08 adder_tester_via2_3_3200_1200_1_3_1040_1040 ;
      VIA 172.08 262.08 adder_tester_via1_2_3200_1200_1_3_1040_1040 ;
      VIA 172.08 252 adder_tester_via3_4_3200_1200_1_3_1040_1040 ;
      VIA 172.08 252 adder_tester_via2_3_3200_1200_1_3_1040_1040 ;
      VIA 172.08 252 adder_tester_via1_2_3200_1200_1_3_1040_1040 ;
      VIA 172.08 241.92 adder_tester_via3_4_3200_1200_1_3_1040_1040 ;
      VIA 172.08 241.92 adder_tester_via2_3_3200_1200_1_3_1040_1040 ;
      VIA 172.08 241.92 adder_tester_via1_2_3200_1200_1_3_1040_1040 ;
      VIA 172.08 231.84 adder_tester_via3_4_3200_1200_1_3_1040_1040 ;
      VIA 172.08 231.84 adder_tester_via2_3_3200_1200_1_3_1040_1040 ;
      VIA 172.08 231.84 adder_tester_via1_2_3200_1200_1_3_1040_1040 ;
      VIA 172.08 221.76 adder_tester_via3_4_3200_1200_1_3_1040_1040 ;
      VIA 172.08 221.76 adder_tester_via2_3_3200_1200_1_3_1040_1040 ;
      VIA 172.08 221.76 adder_tester_via1_2_3200_1200_1_3_1040_1040 ;
      VIA 172.08 211.68 adder_tester_via3_4_3200_1200_1_3_1040_1040 ;
      VIA 172.08 211.68 adder_tester_via2_3_3200_1200_1_3_1040_1040 ;
      VIA 172.08 211.68 adder_tester_via1_2_3200_1200_1_3_1040_1040 ;
      VIA 172.08 201.6 adder_tester_via3_4_3200_1200_1_3_1040_1040 ;
      VIA 172.08 201.6 adder_tester_via2_3_3200_1200_1_3_1040_1040 ;
      VIA 172.08 201.6 adder_tester_via1_2_3200_1200_1_3_1040_1040 ;
      VIA 172.08 191.52 adder_tester_via3_4_3200_1200_1_3_1040_1040 ;
      VIA 172.08 191.52 adder_tester_via2_3_3200_1200_1_3_1040_1040 ;
      VIA 172.08 191.52 adder_tester_via1_2_3200_1200_1_3_1040_1040 ;
      VIA 172.08 181.44 adder_tester_via3_4_3200_1200_1_3_1040_1040 ;
      VIA 172.08 181.44 adder_tester_via2_3_3200_1200_1_3_1040_1040 ;
      VIA 172.08 181.44 adder_tester_via1_2_3200_1200_1_3_1040_1040 ;
      VIA 172.08 171.36 adder_tester_via3_4_3200_1200_1_3_1040_1040 ;
      VIA 172.08 171.36 adder_tester_via2_3_3200_1200_1_3_1040_1040 ;
      VIA 172.08 171.36 adder_tester_via1_2_3200_1200_1_3_1040_1040 ;
      VIA 172.08 161.28 adder_tester_via3_4_3200_1200_1_3_1040_1040 ;
      VIA 172.08 161.28 adder_tester_via2_3_3200_1200_1_3_1040_1040 ;
      VIA 172.08 161.28 adder_tester_via1_2_3200_1200_1_3_1040_1040 ;
      VIA 172.08 151.2 adder_tester_via3_4_3200_1200_1_3_1040_1040 ;
      VIA 172.08 151.2 adder_tester_via2_3_3200_1200_1_3_1040_1040 ;
      VIA 172.08 151.2 adder_tester_via1_2_3200_1200_1_3_1040_1040 ;
      VIA 172.08 141.12 adder_tester_via3_4_3200_1200_1_3_1040_1040 ;
      VIA 172.08 141.12 adder_tester_via2_3_3200_1200_1_3_1040_1040 ;
      VIA 172.08 141.12 adder_tester_via1_2_3200_1200_1_3_1040_1040 ;
      VIA 172.08 131.04 adder_tester_via3_4_3200_1200_1_3_1040_1040 ;
      VIA 172.08 131.04 adder_tester_via2_3_3200_1200_1_3_1040_1040 ;
      VIA 172.08 131.04 adder_tester_via1_2_3200_1200_1_3_1040_1040 ;
      VIA 172.08 120.96 adder_tester_via3_4_3200_1200_1_3_1040_1040 ;
      VIA 172.08 120.96 adder_tester_via2_3_3200_1200_1_3_1040_1040 ;
      VIA 172.08 120.96 adder_tester_via1_2_3200_1200_1_3_1040_1040 ;
      VIA 172.08 110.88 adder_tester_via3_4_3200_1200_1_3_1040_1040 ;
      VIA 172.08 110.88 adder_tester_via2_3_3200_1200_1_3_1040_1040 ;
      VIA 172.08 110.88 adder_tester_via1_2_3200_1200_1_3_1040_1040 ;
      VIA 172.08 100.8 adder_tester_via3_4_3200_1200_1_3_1040_1040 ;
      VIA 172.08 100.8 adder_tester_via2_3_3200_1200_1_3_1040_1040 ;
      VIA 172.08 100.8 adder_tester_via1_2_3200_1200_1_3_1040_1040 ;
      VIA 172.08 90.72 adder_tester_via3_4_3200_1200_1_3_1040_1040 ;
      VIA 172.08 90.72 adder_tester_via2_3_3200_1200_1_3_1040_1040 ;
      VIA 172.08 90.72 adder_tester_via1_2_3200_1200_1_3_1040_1040 ;
      VIA 172.08 80.64 adder_tester_via3_4_3200_1200_1_3_1040_1040 ;
      VIA 172.08 80.64 adder_tester_via2_3_3200_1200_1_3_1040_1040 ;
      VIA 172.08 80.64 adder_tester_via1_2_3200_1200_1_3_1040_1040 ;
      VIA 172.08 70.56 adder_tester_via3_4_3200_1200_1_3_1040_1040 ;
      VIA 172.08 70.56 adder_tester_via2_3_3200_1200_1_3_1040_1040 ;
      VIA 172.08 70.56 adder_tester_via1_2_3200_1200_1_3_1040_1040 ;
      VIA 172.08 60.48 adder_tester_via3_4_3200_1200_1_3_1040_1040 ;
      VIA 172.08 60.48 adder_tester_via2_3_3200_1200_1_3_1040_1040 ;
      VIA 172.08 60.48 adder_tester_via1_2_3200_1200_1_3_1040_1040 ;
      VIA 172.08 50.4 adder_tester_via3_4_3200_1200_1_3_1040_1040 ;
      VIA 172.08 50.4 adder_tester_via2_3_3200_1200_1_3_1040_1040 ;
      VIA 172.08 50.4 adder_tester_via1_2_3200_1200_1_3_1040_1040 ;
      VIA 172.08 40.32 adder_tester_via3_4_3200_1200_1_3_1040_1040 ;
      VIA 172.08 40.32 adder_tester_via2_3_3200_1200_1_3_1040_1040 ;
      VIA 172.08 40.32 adder_tester_via1_2_3200_1200_1_3_1040_1040 ;
      VIA 172.08 30.24 adder_tester_via3_4_3200_1200_1_3_1040_1040 ;
      VIA 172.08 30.24 adder_tester_via2_3_3200_1200_1_3_1040_1040 ;
      VIA 172.08 30.24 adder_tester_via1_2_3200_1200_1_3_1040_1040 ;
      VIA 172.08 20.16 adder_tester_via3_4_3200_1200_1_3_1040_1040 ;
      VIA 172.08 20.16 adder_tester_via2_3_3200_1200_1_3_1040_1040 ;
      VIA 172.08 20.16 adder_tester_via1_2_3200_1200_1_3_1040_1040 ;
      VIA 172.08 10.08 adder_tester_via3_4_3200_1200_1_3_1040_1040 ;
      VIA 172.08 10.08 adder_tester_via2_3_3200_1200_1_3_1040_1040 ;
      VIA 172.08 10.08 adder_tester_via1_2_3200_1200_1_3_1040_1040 ;
      VIA 122.08 262.08 adder_tester_via3_4_3200_1200_1_3_1040_1040 ;
      VIA 122.08 262.08 adder_tester_via2_3_3200_1200_1_3_1040_1040 ;
      VIA 122.08 262.08 adder_tester_via1_2_3200_1200_1_3_1040_1040 ;
      VIA 122.08 252 adder_tester_via3_4_3200_1200_1_3_1040_1040 ;
      VIA 122.08 252 adder_tester_via2_3_3200_1200_1_3_1040_1040 ;
      VIA 122.08 252 adder_tester_via1_2_3200_1200_1_3_1040_1040 ;
      VIA 122.08 241.92 adder_tester_via3_4_3200_1200_1_3_1040_1040 ;
      VIA 122.08 241.92 adder_tester_via2_3_3200_1200_1_3_1040_1040 ;
      VIA 122.08 241.92 adder_tester_via1_2_3200_1200_1_3_1040_1040 ;
      VIA 122.08 231.84 adder_tester_via3_4_3200_1200_1_3_1040_1040 ;
      VIA 122.08 231.84 adder_tester_via2_3_3200_1200_1_3_1040_1040 ;
      VIA 122.08 231.84 adder_tester_via1_2_3200_1200_1_3_1040_1040 ;
      VIA 122.08 221.76 adder_tester_via3_4_3200_1200_1_3_1040_1040 ;
      VIA 122.08 221.76 adder_tester_via2_3_3200_1200_1_3_1040_1040 ;
      VIA 122.08 221.76 adder_tester_via1_2_3200_1200_1_3_1040_1040 ;
      VIA 122.08 211.68 adder_tester_via3_4_3200_1200_1_3_1040_1040 ;
      VIA 122.08 211.68 adder_tester_via2_3_3200_1200_1_3_1040_1040 ;
      VIA 122.08 211.68 adder_tester_via1_2_3200_1200_1_3_1040_1040 ;
      VIA 122.08 201.6 adder_tester_via3_4_3200_1200_1_3_1040_1040 ;
      VIA 122.08 201.6 adder_tester_via2_3_3200_1200_1_3_1040_1040 ;
      VIA 122.08 201.6 adder_tester_via1_2_3200_1200_1_3_1040_1040 ;
      VIA 122.08 191.52 adder_tester_via3_4_3200_1200_1_3_1040_1040 ;
      VIA 122.08 191.52 adder_tester_via2_3_3200_1200_1_3_1040_1040 ;
      VIA 122.08 191.52 adder_tester_via1_2_3200_1200_1_3_1040_1040 ;
      VIA 122.08 181.44 adder_tester_via3_4_3200_1200_1_3_1040_1040 ;
      VIA 122.08 181.44 adder_tester_via2_3_3200_1200_1_3_1040_1040 ;
      VIA 122.08 181.44 adder_tester_via1_2_3200_1200_1_3_1040_1040 ;
      VIA 122.08 171.36 adder_tester_via3_4_3200_1200_1_3_1040_1040 ;
      VIA 122.08 171.36 adder_tester_via2_3_3200_1200_1_3_1040_1040 ;
      VIA 122.08 171.36 adder_tester_via1_2_3200_1200_1_3_1040_1040 ;
      VIA 122.08 161.28 adder_tester_via3_4_3200_1200_1_3_1040_1040 ;
      VIA 122.08 161.28 adder_tester_via2_3_3200_1200_1_3_1040_1040 ;
      VIA 122.08 161.28 adder_tester_via1_2_3200_1200_1_3_1040_1040 ;
      VIA 122.08 151.2 adder_tester_via3_4_3200_1200_1_3_1040_1040 ;
      VIA 122.08 151.2 adder_tester_via2_3_3200_1200_1_3_1040_1040 ;
      VIA 122.08 151.2 adder_tester_via1_2_3200_1200_1_3_1040_1040 ;
      VIA 122.08 141.12 adder_tester_via3_4_3200_1200_1_3_1040_1040 ;
      VIA 122.08 141.12 adder_tester_via2_3_3200_1200_1_3_1040_1040 ;
      VIA 122.08 141.12 adder_tester_via1_2_3200_1200_1_3_1040_1040 ;
      VIA 122.08 131.04 adder_tester_via3_4_3200_1200_1_3_1040_1040 ;
      VIA 122.08 131.04 adder_tester_via2_3_3200_1200_1_3_1040_1040 ;
      VIA 122.08 131.04 adder_tester_via1_2_3200_1200_1_3_1040_1040 ;
      VIA 122.08 120.96 adder_tester_via3_4_3200_1200_1_3_1040_1040 ;
      VIA 122.08 120.96 adder_tester_via2_3_3200_1200_1_3_1040_1040 ;
      VIA 122.08 120.96 adder_tester_via1_2_3200_1200_1_3_1040_1040 ;
      VIA 122.08 110.88 adder_tester_via3_4_3200_1200_1_3_1040_1040 ;
      VIA 122.08 110.88 adder_tester_via2_3_3200_1200_1_3_1040_1040 ;
      VIA 122.08 110.88 adder_tester_via1_2_3200_1200_1_3_1040_1040 ;
      VIA 122.08 100.8 adder_tester_via3_4_3200_1200_1_3_1040_1040 ;
      VIA 122.08 100.8 adder_tester_via2_3_3200_1200_1_3_1040_1040 ;
      VIA 122.08 100.8 adder_tester_via1_2_3200_1200_1_3_1040_1040 ;
      VIA 122.08 90.72 adder_tester_via3_4_3200_1200_1_3_1040_1040 ;
      VIA 122.08 90.72 adder_tester_via2_3_3200_1200_1_3_1040_1040 ;
      VIA 122.08 90.72 adder_tester_via1_2_3200_1200_1_3_1040_1040 ;
      VIA 122.08 80.64 adder_tester_via3_4_3200_1200_1_3_1040_1040 ;
      VIA 122.08 80.64 adder_tester_via2_3_3200_1200_1_3_1040_1040 ;
      VIA 122.08 80.64 adder_tester_via1_2_3200_1200_1_3_1040_1040 ;
      VIA 122.08 70.56 adder_tester_via3_4_3200_1200_1_3_1040_1040 ;
      VIA 122.08 70.56 adder_tester_via2_3_3200_1200_1_3_1040_1040 ;
      VIA 122.08 70.56 adder_tester_via1_2_3200_1200_1_3_1040_1040 ;
      VIA 122.08 60.48 adder_tester_via3_4_3200_1200_1_3_1040_1040 ;
      VIA 122.08 60.48 adder_tester_via2_3_3200_1200_1_3_1040_1040 ;
      VIA 122.08 60.48 adder_tester_via1_2_3200_1200_1_3_1040_1040 ;
      VIA 122.08 50.4 adder_tester_via3_4_3200_1200_1_3_1040_1040 ;
      VIA 122.08 50.4 adder_tester_via2_3_3200_1200_1_3_1040_1040 ;
      VIA 122.08 50.4 adder_tester_via1_2_3200_1200_1_3_1040_1040 ;
      VIA 122.08 40.32 adder_tester_via3_4_3200_1200_1_3_1040_1040 ;
      VIA 122.08 40.32 adder_tester_via2_3_3200_1200_1_3_1040_1040 ;
      VIA 122.08 40.32 adder_tester_via1_2_3200_1200_1_3_1040_1040 ;
      VIA 122.08 30.24 adder_tester_via3_4_3200_1200_1_3_1040_1040 ;
      VIA 122.08 30.24 adder_tester_via2_3_3200_1200_1_3_1040_1040 ;
      VIA 122.08 30.24 adder_tester_via1_2_3200_1200_1_3_1040_1040 ;
      VIA 122.08 20.16 adder_tester_via3_4_3200_1200_1_3_1040_1040 ;
      VIA 122.08 20.16 adder_tester_via2_3_3200_1200_1_3_1040_1040 ;
      VIA 122.08 20.16 adder_tester_via1_2_3200_1200_1_3_1040_1040 ;
      VIA 122.08 10.08 adder_tester_via3_4_3200_1200_1_3_1040_1040 ;
      VIA 122.08 10.08 adder_tester_via2_3_3200_1200_1_3_1040_1040 ;
      VIA 122.08 10.08 adder_tester_via1_2_3200_1200_1_3_1040_1040 ;
      VIA 72.08 262.08 adder_tester_via3_4_3200_1200_1_3_1040_1040 ;
      VIA 72.08 262.08 adder_tester_via2_3_3200_1200_1_3_1040_1040 ;
      VIA 72.08 262.08 adder_tester_via1_2_3200_1200_1_3_1040_1040 ;
      VIA 72.08 252 adder_tester_via3_4_3200_1200_1_3_1040_1040 ;
      VIA 72.08 252 adder_tester_via2_3_3200_1200_1_3_1040_1040 ;
      VIA 72.08 252 adder_tester_via1_2_3200_1200_1_3_1040_1040 ;
      VIA 72.08 241.92 adder_tester_via3_4_3200_1200_1_3_1040_1040 ;
      VIA 72.08 241.92 adder_tester_via2_3_3200_1200_1_3_1040_1040 ;
      VIA 72.08 241.92 adder_tester_via1_2_3200_1200_1_3_1040_1040 ;
      VIA 72.08 231.84 adder_tester_via3_4_3200_1200_1_3_1040_1040 ;
      VIA 72.08 231.84 adder_tester_via2_3_3200_1200_1_3_1040_1040 ;
      VIA 72.08 231.84 adder_tester_via1_2_3200_1200_1_3_1040_1040 ;
      VIA 72.08 221.76 adder_tester_via3_4_3200_1200_1_3_1040_1040 ;
      VIA 72.08 221.76 adder_tester_via2_3_3200_1200_1_3_1040_1040 ;
      VIA 72.08 221.76 adder_tester_via1_2_3200_1200_1_3_1040_1040 ;
      VIA 72.08 211.68 adder_tester_via3_4_3200_1200_1_3_1040_1040 ;
      VIA 72.08 211.68 adder_tester_via2_3_3200_1200_1_3_1040_1040 ;
      VIA 72.08 211.68 adder_tester_via1_2_3200_1200_1_3_1040_1040 ;
      VIA 72.08 201.6 adder_tester_via3_4_3200_1200_1_3_1040_1040 ;
      VIA 72.08 201.6 adder_tester_via2_3_3200_1200_1_3_1040_1040 ;
      VIA 72.08 201.6 adder_tester_via1_2_3200_1200_1_3_1040_1040 ;
      VIA 72.08 191.52 adder_tester_via3_4_3200_1200_1_3_1040_1040 ;
      VIA 72.08 191.52 adder_tester_via2_3_3200_1200_1_3_1040_1040 ;
      VIA 72.08 191.52 adder_tester_via1_2_3200_1200_1_3_1040_1040 ;
      VIA 72.08 181.44 adder_tester_via3_4_3200_1200_1_3_1040_1040 ;
      VIA 72.08 181.44 adder_tester_via2_3_3200_1200_1_3_1040_1040 ;
      VIA 72.08 181.44 adder_tester_via1_2_3200_1200_1_3_1040_1040 ;
      VIA 72.08 171.36 adder_tester_via3_4_3200_1200_1_3_1040_1040 ;
      VIA 72.08 171.36 adder_tester_via2_3_3200_1200_1_3_1040_1040 ;
      VIA 72.08 171.36 adder_tester_via1_2_3200_1200_1_3_1040_1040 ;
      VIA 72.08 161.28 adder_tester_via3_4_3200_1200_1_3_1040_1040 ;
      VIA 72.08 161.28 adder_tester_via2_3_3200_1200_1_3_1040_1040 ;
      VIA 72.08 161.28 adder_tester_via1_2_3200_1200_1_3_1040_1040 ;
      VIA 72.08 151.2 adder_tester_via3_4_3200_1200_1_3_1040_1040 ;
      VIA 72.08 151.2 adder_tester_via2_3_3200_1200_1_3_1040_1040 ;
      VIA 72.08 151.2 adder_tester_via1_2_3200_1200_1_3_1040_1040 ;
      VIA 72.08 141.12 adder_tester_via3_4_3200_1200_1_3_1040_1040 ;
      VIA 72.08 141.12 adder_tester_via2_3_3200_1200_1_3_1040_1040 ;
      VIA 72.08 141.12 adder_tester_via1_2_3200_1200_1_3_1040_1040 ;
      VIA 72.08 131.04 adder_tester_via3_4_3200_1200_1_3_1040_1040 ;
      VIA 72.08 131.04 adder_tester_via2_3_3200_1200_1_3_1040_1040 ;
      VIA 72.08 131.04 adder_tester_via1_2_3200_1200_1_3_1040_1040 ;
      VIA 72.08 120.96 adder_tester_via3_4_3200_1200_1_3_1040_1040 ;
      VIA 72.08 120.96 adder_tester_via2_3_3200_1200_1_3_1040_1040 ;
      VIA 72.08 120.96 adder_tester_via1_2_3200_1200_1_3_1040_1040 ;
      VIA 72.08 110.88 adder_tester_via3_4_3200_1200_1_3_1040_1040 ;
      VIA 72.08 110.88 adder_tester_via2_3_3200_1200_1_3_1040_1040 ;
      VIA 72.08 110.88 adder_tester_via1_2_3200_1200_1_3_1040_1040 ;
      VIA 72.08 100.8 adder_tester_via3_4_3200_1200_1_3_1040_1040 ;
      VIA 72.08 100.8 adder_tester_via2_3_3200_1200_1_3_1040_1040 ;
      VIA 72.08 100.8 adder_tester_via1_2_3200_1200_1_3_1040_1040 ;
      VIA 72.08 90.72 adder_tester_via3_4_3200_1200_1_3_1040_1040 ;
      VIA 72.08 90.72 adder_tester_via2_3_3200_1200_1_3_1040_1040 ;
      VIA 72.08 90.72 adder_tester_via1_2_3200_1200_1_3_1040_1040 ;
      VIA 72.08 80.64 adder_tester_via3_4_3200_1200_1_3_1040_1040 ;
      VIA 72.08 80.64 adder_tester_via2_3_3200_1200_1_3_1040_1040 ;
      VIA 72.08 80.64 adder_tester_via1_2_3200_1200_1_3_1040_1040 ;
      VIA 72.08 70.56 adder_tester_via3_4_3200_1200_1_3_1040_1040 ;
      VIA 72.08 70.56 adder_tester_via2_3_3200_1200_1_3_1040_1040 ;
      VIA 72.08 70.56 adder_tester_via1_2_3200_1200_1_3_1040_1040 ;
      VIA 72.08 60.48 adder_tester_via3_4_3200_1200_1_3_1040_1040 ;
      VIA 72.08 60.48 adder_tester_via2_3_3200_1200_1_3_1040_1040 ;
      VIA 72.08 60.48 adder_tester_via1_2_3200_1200_1_3_1040_1040 ;
      VIA 72.08 50.4 adder_tester_via3_4_3200_1200_1_3_1040_1040 ;
      VIA 72.08 50.4 adder_tester_via2_3_3200_1200_1_3_1040_1040 ;
      VIA 72.08 50.4 adder_tester_via1_2_3200_1200_1_3_1040_1040 ;
      VIA 72.08 40.32 adder_tester_via3_4_3200_1200_1_3_1040_1040 ;
      VIA 72.08 40.32 adder_tester_via2_3_3200_1200_1_3_1040_1040 ;
      VIA 72.08 40.32 adder_tester_via1_2_3200_1200_1_3_1040_1040 ;
      VIA 72.08 30.24 adder_tester_via3_4_3200_1200_1_3_1040_1040 ;
      VIA 72.08 30.24 adder_tester_via2_3_3200_1200_1_3_1040_1040 ;
      VIA 72.08 30.24 adder_tester_via1_2_3200_1200_1_3_1040_1040 ;
      VIA 72.08 20.16 adder_tester_via3_4_3200_1200_1_3_1040_1040 ;
      VIA 72.08 20.16 adder_tester_via2_3_3200_1200_1_3_1040_1040 ;
      VIA 72.08 20.16 adder_tester_via1_2_3200_1200_1_3_1040_1040 ;
      VIA 72.08 10.08 adder_tester_via3_4_3200_1200_1_3_1040_1040 ;
      VIA 72.08 10.08 adder_tester_via2_3_3200_1200_1_3_1040_1040 ;
      VIA 72.08 10.08 adder_tester_via1_2_3200_1200_1_3_1040_1040 ;
      VIA 22.08 262.08 adder_tester_via3_4_3200_1200_1_3_1040_1040 ;
      VIA 22.08 262.08 adder_tester_via2_3_3200_1200_1_3_1040_1040 ;
      VIA 22.08 262.08 adder_tester_via1_2_3200_1200_1_3_1040_1040 ;
      VIA 22.08 252 adder_tester_via3_4_3200_1200_1_3_1040_1040 ;
      VIA 22.08 252 adder_tester_via2_3_3200_1200_1_3_1040_1040 ;
      VIA 22.08 252 adder_tester_via1_2_3200_1200_1_3_1040_1040 ;
      VIA 22.08 241.92 adder_tester_via3_4_3200_1200_1_3_1040_1040 ;
      VIA 22.08 241.92 adder_tester_via2_3_3200_1200_1_3_1040_1040 ;
      VIA 22.08 241.92 adder_tester_via1_2_3200_1200_1_3_1040_1040 ;
      VIA 22.08 231.84 adder_tester_via3_4_3200_1200_1_3_1040_1040 ;
      VIA 22.08 231.84 adder_tester_via2_3_3200_1200_1_3_1040_1040 ;
      VIA 22.08 231.84 adder_tester_via1_2_3200_1200_1_3_1040_1040 ;
      VIA 22.08 221.76 adder_tester_via3_4_3200_1200_1_3_1040_1040 ;
      VIA 22.08 221.76 adder_tester_via2_3_3200_1200_1_3_1040_1040 ;
      VIA 22.08 221.76 adder_tester_via1_2_3200_1200_1_3_1040_1040 ;
      VIA 22.08 211.68 adder_tester_via3_4_3200_1200_1_3_1040_1040 ;
      VIA 22.08 211.68 adder_tester_via2_3_3200_1200_1_3_1040_1040 ;
      VIA 22.08 211.68 adder_tester_via1_2_3200_1200_1_3_1040_1040 ;
      VIA 22.08 201.6 adder_tester_via3_4_3200_1200_1_3_1040_1040 ;
      VIA 22.08 201.6 adder_tester_via2_3_3200_1200_1_3_1040_1040 ;
      VIA 22.08 201.6 adder_tester_via1_2_3200_1200_1_3_1040_1040 ;
      VIA 22.08 191.52 adder_tester_via3_4_3200_1200_1_3_1040_1040 ;
      VIA 22.08 191.52 adder_tester_via2_3_3200_1200_1_3_1040_1040 ;
      VIA 22.08 191.52 adder_tester_via1_2_3200_1200_1_3_1040_1040 ;
      VIA 22.08 181.44 adder_tester_via3_4_3200_1200_1_3_1040_1040 ;
      VIA 22.08 181.44 adder_tester_via2_3_3200_1200_1_3_1040_1040 ;
      VIA 22.08 181.44 adder_tester_via1_2_3200_1200_1_3_1040_1040 ;
      VIA 22.08 171.36 adder_tester_via3_4_3200_1200_1_3_1040_1040 ;
      VIA 22.08 171.36 adder_tester_via2_3_3200_1200_1_3_1040_1040 ;
      VIA 22.08 171.36 adder_tester_via1_2_3200_1200_1_3_1040_1040 ;
      VIA 22.08 161.28 adder_tester_via3_4_3200_1200_1_3_1040_1040 ;
      VIA 22.08 161.28 adder_tester_via2_3_3200_1200_1_3_1040_1040 ;
      VIA 22.08 161.28 adder_tester_via1_2_3200_1200_1_3_1040_1040 ;
      VIA 22.08 151.2 adder_tester_via3_4_3200_1200_1_3_1040_1040 ;
      VIA 22.08 151.2 adder_tester_via2_3_3200_1200_1_3_1040_1040 ;
      VIA 22.08 151.2 adder_tester_via1_2_3200_1200_1_3_1040_1040 ;
      VIA 22.08 141.12 adder_tester_via3_4_3200_1200_1_3_1040_1040 ;
      VIA 22.08 141.12 adder_tester_via2_3_3200_1200_1_3_1040_1040 ;
      VIA 22.08 141.12 adder_tester_via1_2_3200_1200_1_3_1040_1040 ;
      VIA 22.08 131.04 adder_tester_via3_4_3200_1200_1_3_1040_1040 ;
      VIA 22.08 131.04 adder_tester_via2_3_3200_1200_1_3_1040_1040 ;
      VIA 22.08 131.04 adder_tester_via1_2_3200_1200_1_3_1040_1040 ;
      VIA 22.08 120.96 adder_tester_via3_4_3200_1200_1_3_1040_1040 ;
      VIA 22.08 120.96 adder_tester_via2_3_3200_1200_1_3_1040_1040 ;
      VIA 22.08 120.96 adder_tester_via1_2_3200_1200_1_3_1040_1040 ;
      VIA 22.08 110.88 adder_tester_via3_4_3200_1200_1_3_1040_1040 ;
      VIA 22.08 110.88 adder_tester_via2_3_3200_1200_1_3_1040_1040 ;
      VIA 22.08 110.88 adder_tester_via1_2_3200_1200_1_3_1040_1040 ;
      VIA 22.08 100.8 adder_tester_via3_4_3200_1200_1_3_1040_1040 ;
      VIA 22.08 100.8 adder_tester_via2_3_3200_1200_1_3_1040_1040 ;
      VIA 22.08 100.8 adder_tester_via1_2_3200_1200_1_3_1040_1040 ;
      VIA 22.08 90.72 adder_tester_via3_4_3200_1200_1_3_1040_1040 ;
      VIA 22.08 90.72 adder_tester_via2_3_3200_1200_1_3_1040_1040 ;
      VIA 22.08 90.72 adder_tester_via1_2_3200_1200_1_3_1040_1040 ;
      VIA 22.08 80.64 adder_tester_via3_4_3200_1200_1_3_1040_1040 ;
      VIA 22.08 80.64 adder_tester_via2_3_3200_1200_1_3_1040_1040 ;
      VIA 22.08 80.64 adder_tester_via1_2_3200_1200_1_3_1040_1040 ;
      VIA 22.08 70.56 adder_tester_via3_4_3200_1200_1_3_1040_1040 ;
      VIA 22.08 70.56 adder_tester_via2_3_3200_1200_1_3_1040_1040 ;
      VIA 22.08 70.56 adder_tester_via1_2_3200_1200_1_3_1040_1040 ;
      VIA 22.08 60.48 adder_tester_via3_4_3200_1200_1_3_1040_1040 ;
      VIA 22.08 60.48 adder_tester_via2_3_3200_1200_1_3_1040_1040 ;
      VIA 22.08 60.48 adder_tester_via1_2_3200_1200_1_3_1040_1040 ;
      VIA 22.08 50.4 adder_tester_via3_4_3200_1200_1_3_1040_1040 ;
      VIA 22.08 50.4 adder_tester_via2_3_3200_1200_1_3_1040_1040 ;
      VIA 22.08 50.4 adder_tester_via1_2_3200_1200_1_3_1040_1040 ;
      VIA 22.08 40.32 adder_tester_via3_4_3200_1200_1_3_1040_1040 ;
      VIA 22.08 40.32 adder_tester_via2_3_3200_1200_1_3_1040_1040 ;
      VIA 22.08 40.32 adder_tester_via1_2_3200_1200_1_3_1040_1040 ;
      VIA 22.08 30.24 adder_tester_via3_4_3200_1200_1_3_1040_1040 ;
      VIA 22.08 30.24 adder_tester_via2_3_3200_1200_1_3_1040_1040 ;
      VIA 22.08 30.24 adder_tester_via1_2_3200_1200_1_3_1040_1040 ;
      VIA 22.08 20.16 adder_tester_via3_4_3200_1200_1_3_1040_1040 ;
      VIA 22.08 20.16 adder_tester_via2_3_3200_1200_1_3_1040_1040 ;
      VIA 22.08 20.16 adder_tester_via1_2_3200_1200_1_3_1040_1040 ;
      VIA 22.08 10.08 adder_tester_via3_4_3200_1200_1_3_1040_1040 ;
      VIA 22.08 10.08 adder_tester_via2_3_3200_1200_1_3_1040_1040 ;
      VIA 22.08 10.08 adder_tester_via1_2_3200_1200_1_3_1040_1040 ;
    END
  END VSS
  PIN a[0]
    DIRECTION OUTPUT ;
    USE SIGNAL ;
    PORT
      LAYER Metal2 ;
        RECT  175.98 277.83 176.26 278.35 ;
    END
  END a[0]
  PIN a[10]
    DIRECTION OUTPUT ;
    USE SIGNAL ;
    PORT
      LAYER Metal2 ;
        RECT  273.42 277.83 273.7 278.35 ;
    END
  END a[10]
  PIN a[11]
    DIRECTION OUTPUT ;
    USE SIGNAL ;
    PORT
      LAYER Metal2 ;
        RECT  84.14 277.83 84.42 278.35 ;
    END
  END a[11]
  PIN a[12]
    DIRECTION OUTPUT ;
    USE SIGNAL ;
    PORT
      LAYER Metal2 ;
        RECT  141.26 277.83 141.54 278.35 ;
    END
  END a[12]
  PIN a[13]
    DIRECTION OUTPUT ;
    USE SIGNAL ;
    PORT
      LAYER Metal2 ;
        RECT  137.9 277.83 138.18 278.35 ;
    END
  END a[13]
  PIN a[14]
    DIRECTION OUTPUT ;
    USE SIGNAL ;
    PORT
      LAYER Metal2 ;
        RECT  83.02 277.83 83.3 278.35 ;
    END
  END a[14]
  PIN a[15]
    DIRECTION OUTPUT ;
    USE SIGNAL ;
    PORT
      LAYER Metal2 ;
        RECT  144.62 277.83 144.9 278.35 ;
    END
  END a[15]
  PIN a[16]
    DIRECTION OUTPUT ;
    USE SIGNAL ;
    PORT
      LAYER Metal2 ;
        RECT  145.74 277.83 146.02 278.35 ;
    END
  END a[16]
  PIN a[17]
    DIRECTION OUTPUT ;
    USE SIGNAL ;
    PORT
      LAYER Metal2 ;
        RECT  136.78 277.83 137.06 278.35 ;
    END
  END a[17]
  PIN a[18]
    DIRECTION OUTPUT ;
    USE SIGNAL ;
    PORT
      LAYER Metal2 ;
        RECT  81.9 277.83 82.18 278.35 ;
    END
  END a[18]
  PIN a[19]
    DIRECTION OUTPUT ;
    USE SIGNAL ;
    PORT
      LAYER Metal2 ;
        RECT  135.66 277.83 135.94 278.35 ;
    END
  END a[19]
  PIN a[1]
    DIRECTION OUTPUT ;
    USE SIGNAL ;
    PORT
      LAYER Metal2 ;
        RECT  149.1 277.83 149.38 278.35 ;
    END
  END a[1]
  PIN a[20]
    DIRECTION OUTPUT ;
    USE SIGNAL ;
    PORT
      LAYER Metal2 ;
        RECT  151.34 277.83 151.62 278.35 ;
    END
  END a[20]
  PIN a[21]
    DIRECTION OUTPUT ;
    USE SIGNAL ;
    PORT
      LAYER Metal2 ;
        RECT  150.22 277.83 150.5 278.35 ;
    END
  END a[21]
  PIN a[22]
    DIRECTION OUTPUT ;
    USE SIGNAL ;
    PORT
      LAYER Metal2 ;
        RECT  80.78 277.83 81.06 278.35 ;
    END
  END a[22]
  PIN a[23]
    DIRECTION OUTPUT ;
    USE SIGNAL ;
    PORT
      LAYER Metal2 ;
        RECT  134.54 277.83 134.82 278.35 ;
    END
  END a[23]
  PIN a[24]
    DIRECTION OUTPUT ;
    USE SIGNAL ;
    PORT
      LAYER Metal2 ;
        RECT  155.82 277.83 156.1 278.35 ;
    END
  END a[24]
  PIN a[25]
    DIRECTION OUTPUT ;
    USE SIGNAL ;
    PORT
      LAYER Metal2 ;
        RECT  79.66 277.83 79.94 278.35 ;
    END
  END a[25]
  PIN a[26]
    DIRECTION OUTPUT ;
    USE SIGNAL ;
    PORT
      LAYER Metal2 ;
        RECT  159.18 277.83 159.46 278.35 ;
    END
  END a[26]
  PIN a[27]
    DIRECTION OUTPUT ;
    USE SIGNAL ;
    PORT
      LAYER Metal2 ;
        RECT  78.54 277.83 78.82 278.35 ;
    END
  END a[27]
  PIN a[28]
    DIRECTION OUTPUT ;
    USE SIGNAL ;
    PORT
      LAYER Metal2 ;
        RECT  161.42 277.83 161.7 278.35 ;
    END
  END a[28]
  PIN a[29]
    DIRECTION OUTPUT ;
    USE SIGNAL ;
    PORT
      LAYER Metal2 ;
        RECT  162.54 277.83 162.82 278.35 ;
    END
  END a[29]
  PIN a[2]
    DIRECTION OUTPUT ;
    USE SIGNAL ;
    PORT
      LAYER Metal2 ;
        RECT  131.18 277.83 131.46 278.35 ;
    END
  END a[2]
  PIN a[30]
    DIRECTION OUTPUT ;
    USE SIGNAL ;
    PORT
      LAYER Metal2 ;
        RECT  163.66 277.83 163.94 278.35 ;
    END
  END a[30]
  PIN a[31]
    DIRECTION OUTPUT ;
    USE SIGNAL ;
    PORT
      LAYER Metal2 ;
        RECT  165.9 277.83 166.18 278.35 ;
    END
  END a[31]
  PIN a[32]
    DIRECTION OUTPUT ;
    USE SIGNAL ;
    PORT
      LAYER Metal2 ;
        RECT  189.42 277.83 189.7 278.35 ;
    END
  END a[32]
  PIN a[33]
    DIRECTION OUTPUT ;
    USE SIGNAL ;
    PORT
      LAYER Metal2 ;
        RECT  71.82 277.83 72.1 278.35 ;
    END
  END a[33]
  PIN a[34]
    DIRECTION OUTPUT ;
    USE SIGNAL ;
    PORT
      LAYER Metal2 ;
        RECT  77.42 277.83 77.7 278.35 ;
    END
  END a[34]
  PIN a[35]
    DIRECTION OUTPUT ;
    USE SIGNAL ;
    PORT
      LAYER Metal2 ;
        RECT  124.46 277.83 124.74 278.35 ;
    END
  END a[35]
  PIN a[36]
    DIRECTION OUTPUT ;
    USE SIGNAL ;
    PORT
      LAYER Metal2 ;
        RECT  130.06 277.83 130.34 278.35 ;
    END
  END a[36]
  PIN a[37]
    DIRECTION OUTPUT ;
    USE SIGNAL ;
    PORT
      LAYER Metal2 ;
        RECT  117.74 277.83 118.02 278.35 ;
    END
  END a[37]
  PIN a[38]
    DIRECTION OUTPUT ;
    USE SIGNAL ;
    PORT
      LAYER Metal2 ;
        RECT  75.18 277.83 75.46 278.35 ;
    END
  END a[38]
  PIN a[39]
    DIRECTION OUTPUT ;
    USE SIGNAL ;
    PORT
      LAYER Metal2 ;
        RECT  167.02 277.83 167.3 278.35 ;
    END
  END a[39]
  PIN a[3]
    DIRECTION OUTPUT ;
    USE SIGNAL ;
    PORT
      LAYER Metal2 ;
        RECT  168.14 277.83 168.42 278.35 ;
    END
  END a[3]
  PIN a[40]
    DIRECTION OUTPUT ;
    USE SIGNAL ;
    PORT
      LAYER Metal2 ;
        RECT  171.5 277.83 171.78 278.35 ;
    END
  END a[40]
  PIN a[41]
    DIRECTION OUTPUT ;
    USE SIGNAL ;
    PORT
      LAYER Metal2 ;
        RECT  125.58 277.83 125.86 278.35 ;
    END
  END a[41]
  PIN a[42]
    DIRECTION OUTPUT ;
    USE SIGNAL ;
    PORT
      LAYER Metal2 ;
        RECT  128.94 277.83 129.22 278.35 ;
    END
  END a[42]
  PIN a[43]
    DIRECTION OUTPUT ;
    USE SIGNAL ;
    PORT
      LAYER Metal2 ;
        RECT  76.3 277.83 76.58 278.35 ;
    END
  END a[43]
  PIN a[44]
    DIRECTION OUTPUT ;
    USE SIGNAL ;
    PORT
      LAYER Metal2 ;
        RECT  170.38 277.83 170.66 278.35 ;
    END
  END a[44]
  PIN a[45]
    DIRECTION OUTPUT ;
    USE SIGNAL ;
    PORT
      LAYER Metal2 ;
        RECT  74.06 277.83 74.34 278.35 ;
    END
  END a[45]
  PIN a[46]
    DIRECTION OUTPUT ;
    USE SIGNAL ;
    PORT
      LAYER Metal2 ;
        RECT  172.62 277.83 172.9 278.35 ;
    END
  END a[46]
  PIN a[47]
    DIRECTION OUTPUT ;
    USE SIGNAL ;
    PORT
      LAYER Metal2 ;
        RECT  146.86 277.83 147.14 278.35 ;
    END
  END a[47]
  PIN a[48]
    DIRECTION OUTPUT ;
    USE SIGNAL ;
    PORT
      LAYER Metal2 ;
        RECT  173.74 277.83 174.02 278.35 ;
    END
  END a[48]
  PIN a[49]
    DIRECTION OUTPUT ;
    USE SIGNAL ;
    PORT
      LAYER Metal2 ;
        RECT  174.86 277.83 175.14 278.35 ;
    END
  END a[49]
  PIN a[4]
    DIRECTION OUTPUT ;
    USE SIGNAL ;
    PORT
      LAYER Metal2 ;
        RECT  126.7 277.83 126.98 278.35 ;
    END
  END a[4]
  PIN a[50]
    DIRECTION OUTPUT ;
    USE SIGNAL ;
    PORT
      LAYER Metal2 ;
        RECT  122.22 277.83 122.5 278.35 ;
    END
  END a[50]
  PIN a[51]
    DIRECTION OUTPUT ;
    USE SIGNAL ;
    PORT
      LAYER Metal2 ;
        RECT  178.22 277.83 178.5 278.35 ;
    END
  END a[51]
  PIN a[52]
    DIRECTION OUTPUT ;
    USE SIGNAL ;
    PORT
      LAYER Metal2 ;
        RECT  179.34 277.83 179.62 278.35 ;
    END
  END a[52]
  PIN a[53]
    DIRECTION OUTPUT ;
    USE SIGNAL ;
    PORT
      LAYER Metal2 ;
        RECT  180.46 277.83 180.74 278.35 ;
    END
  END a[53]
  PIN a[54]
    DIRECTION OUTPUT ;
    USE SIGNAL ;
    PORT
      LAYER Metal2 ;
        RECT  72.94 277.83 73.22 278.35 ;
    END
  END a[54]
  PIN a[55]
    DIRECTION OUTPUT ;
    USE SIGNAL ;
    PORT
      LAYER Metal2 ;
        RECT  158.06 277.83 158.34 278.35 ;
    END
  END a[55]
  PIN a[56]
    DIRECTION OUTPUT ;
    USE SIGNAL ;
    PORT
      LAYER Metal2 ;
        RECT  182.7 277.83 182.98 278.35 ;
    END
  END a[56]
  PIN a[57]
    DIRECTION OUTPUT ;
    USE SIGNAL ;
    PORT
      LAYER Metal2 ;
        RECT  183.82 277.83 184.1 278.35 ;
    END
  END a[57]
  PIN a[58]
    DIRECTION OUTPUT ;
    USE SIGNAL ;
    PORT
      LAYER Metal2 ;
        RECT  184.94 277.83 185.22 278.35 ;
    END
  END a[58]
  PIN a[59]
    DIRECTION OUTPUT ;
    USE SIGNAL ;
    PORT
      LAYER Metal2 ;
        RECT  153.58 277.83 153.86 278.35 ;
    END
  END a[59]
  PIN a[5]
    DIRECTION OUTPUT ;
    USE SIGNAL ;
    PORT
      LAYER Metal2 ;
        RECT  140.14 277.83 140.42 278.35 ;
    END
  END a[5]
  PIN a[60]
    DIRECTION OUTPUT ;
    USE SIGNAL ;
    PORT
      LAYER Metal2 ;
        RECT  132.3 277.83 132.58 278.35 ;
    END
  END a[60]
  PIN a[61]
    DIRECTION OUTPUT ;
    USE SIGNAL ;
    PORT
      LAYER Metal2 ;
        RECT  123.34 277.83 123.62 278.35 ;
    END
  END a[61]
  PIN a[62]
    DIRECTION OUTPUT ;
    USE SIGNAL ;
    PORT
      LAYER Metal2 ;
        RECT  187.18 277.83 187.46 278.35 ;
    END
  END a[62]
  PIN a[63]
    DIRECTION OUTPUT ;
    USE SIGNAL ;
    PORT
      LAYER Metal2 ;
        RECT  188.3 277.83 188.58 278.35 ;
    END
  END a[63]
  PIN a[6]
    DIRECTION OUTPUT ;
    USE SIGNAL ;
    PORT
      LAYER Metal2 ;
        RECT  70.7 277.83 70.98 278.35 ;
    END
  END a[6]
  PIN a[7]
    DIRECTION OUTPUT ;
    USE SIGNAL ;
    PORT
      LAYER Metal2 ;
        RECT  154.7 277.83 154.98 278.35 ;
    END
  END a[7]
  PIN a[8]
    DIRECTION OUTPUT ;
    USE SIGNAL ;
    PORT
      LAYER Metal2 ;
        RECT  190.54 277.83 190.82 278.35 ;
    END
  END a[8]
  PIN a[9]
    DIRECTION OUTPUT ;
    USE SIGNAL ;
    PORT
      LAYER Metal2 ;
        RECT  191.66 277.83 191.94 278.35 ;
    END
  END a[9]
  PIN b[0]
    DIRECTION OUTPUT ;
    USE SIGNAL ;
    PORT
      LAYER Metal2 ;
        RECT  192.78 277.83 193.06 278.35 ;
    END
  END b[0]
  PIN b[10]
    DIRECTION OUTPUT ;
    USE SIGNAL ;
    PORT
      LAYER Metal2 ;
        RECT  121.1 277.83 121.38 278.35 ;
    END
  END b[10]
  PIN b[11]
    DIRECTION OUTPUT ;
    USE SIGNAL ;
    PORT
      LAYER Metal2 ;
        RECT  196.14 277.83 196.42 278.35 ;
    END
  END b[11]
  PIN b[12]
    DIRECTION OUTPUT ;
    USE SIGNAL ;
    PORT
      LAYER Metal2 ;
        RECT  197.26 277.83 197.54 278.35 ;
    END
  END b[12]
  PIN b[13]
    DIRECTION OUTPUT ;
    USE SIGNAL ;
    PORT
      LAYER Metal2 ;
        RECT  198.38 277.83 198.66 278.35 ;
    END
  END b[13]
  PIN b[14]
    DIRECTION OUTPUT ;
    USE SIGNAL ;
    PORT
      LAYER Metal2 ;
        RECT  118.86 277.83 119.14 278.35 ;
    END
  END b[14]
  PIN b[15]
    DIRECTION OUTPUT ;
    USE SIGNAL ;
    PORT
      LAYER Metal2 ;
        RECT  201.74 277.83 202.02 278.35 ;
    END
  END b[15]
  PIN b[16]
    DIRECTION OUTPUT ;
    USE SIGNAL ;
    PORT
      LAYER Metal2 ;
        RECT  67.34 277.83 67.62 278.35 ;
    END
  END b[16]
  PIN b[17]
    DIRECTION OUTPUT ;
    USE SIGNAL ;
    PORT
      LAYER Metal2 ;
        RECT  206.22 277.83 206.5 278.35 ;
    END
  END b[17]
  PIN b[18]
    DIRECTION OUTPUT ;
    USE SIGNAL ;
    PORT
      LAYER Metal2 ;
        RECT  66.22 277.83 66.5 278.35 ;
    END
  END b[18]
  PIN b[19]
    DIRECTION OUTPUT ;
    USE SIGNAL ;
    PORT
      LAYER Metal2 ;
        RECT  217.42 277.83 217.7 278.35 ;
    END
  END b[19]
  PIN b[1]
    DIRECTION OUTPUT ;
    USE SIGNAL ;
    PORT
      LAYER Metal2 ;
        RECT  209.58 277.83 209.86 278.35 ;
    END
  END b[1]
  PIN b[20]
    DIRECTION OUTPUT ;
    USE SIGNAL ;
    PORT
      LAYER Metal2 ;
        RECT  199.5 277.83 199.78 278.35 ;
    END
  END b[20]
  PIN b[21]
    DIRECTION OUTPUT ;
    USE SIGNAL ;
    PORT
      LAYER Metal2 ;
        RECT  115.5 277.83 115.78 278.35 ;
    END
  END b[21]
  PIN b[22]
    DIRECTION OUTPUT ;
    USE SIGNAL ;
    PORT
      LAYER Metal2 ;
        RECT  215.18 277.83 215.46 278.35 ;
    END
  END b[22]
  PIN b[23]
    DIRECTION OUTPUT ;
    USE SIGNAL ;
    PORT
      LAYER Metal2 ;
        RECT  212.94 277.83 213.22 278.35 ;
    END
  END b[23]
  PIN b[24]
    DIRECTION OUTPUT ;
    USE SIGNAL ;
    PORT
      LAYER Metal2 ;
        RECT  102.06 277.83 102.34 278.35 ;
    END
  END b[24]
  PIN b[25]
    DIRECTION OUTPUT ;
    USE SIGNAL ;
    PORT
      LAYER Metal2 ;
        RECT  113.26 277.83 113.54 278.35 ;
    END
  END b[25]
  PIN b[26]
    DIRECTION OUTPUT ;
    USE SIGNAL ;
    PORT
      LAYER Metal2 ;
        RECT  65.1 277.83 65.38 278.35 ;
    END
  END b[26]
  PIN b[27]
    DIRECTION OUTPUT ;
    USE SIGNAL ;
    PORT
      LAYER Metal2 ;
        RECT  112.14 277.83 112.42 278.35 ;
    END
  END b[27]
  PIN b[28]
    DIRECTION OUTPUT ;
    USE SIGNAL ;
    PORT
      LAYER Metal2 ;
        RECT  218.54 277.83 218.82 278.35 ;
    END
  END b[28]
  PIN b[29]
    DIRECTION OUTPUT ;
    USE SIGNAL ;
    PORT
      LAYER Metal2 ;
        RECT  195.02 277.83 195.3 278.35 ;
    END
  END b[29]
  PIN b[2]
    DIRECTION OUTPUT ;
    USE SIGNAL ;
    PORT
      LAYER Metal2 ;
        RECT  203.98 277.83 204.26 278.35 ;
    END
  END b[2]
  PIN b[30]
    DIRECTION OUTPUT ;
    USE SIGNAL ;
    PORT
      LAYER Metal2 ;
        RECT  111.02 277.83 111.3 278.35 ;
    END
  END b[30]
  PIN b[31]
    DIRECTION OUTPUT ;
    USE SIGNAL ;
    PORT
      LAYER Metal2 ;
        RECT  114.38 277.83 114.66 278.35 ;
    END
  END b[31]
  PIN b[32]
    DIRECTION OUTPUT ;
    USE SIGNAL ;
    PORT
      LAYER Metal2 ;
        RECT  216.3 277.83 216.58 278.35 ;
    END
  END b[32]
  PIN b[33]
    DIRECTION OUTPUT ;
    USE SIGNAL ;
    PORT
      LAYER Metal2 ;
        RECT  63.98 277.83 64.26 278.35 ;
    END
  END b[33]
  PIN b[34]
    DIRECTION OUTPUT ;
    USE SIGNAL ;
    PORT
      LAYER Metal2 ;
        RECT  219.66 277.83 219.94 278.35 ;
    END
  END b[34]
  PIN b[35]
    DIRECTION OUTPUT ;
    USE SIGNAL ;
    PORT
      LAYER Metal2 ;
        RECT  160.3 277.83 160.58 278.35 ;
    END
  END b[35]
  PIN b[36]
    DIRECTION OUTPUT ;
    USE SIGNAL ;
    PORT
      LAYER Metal2 ;
        RECT  200.62 277.83 200.9 278.35 ;
    END
  END b[36]
  PIN b[37]
    DIRECTION OUTPUT ;
    USE SIGNAL ;
    PORT
      LAYER Metal2 ;
        RECT  105.42 277.83 105.7 278.35 ;
    END
  END b[37]
  PIN b[38]
    DIRECTION OUTPUT ;
    USE SIGNAL ;
    PORT
      LAYER Metal2 ;
        RECT  220.78 277.83 221.06 278.35 ;
    END
  END b[38]
  PIN b[39]
    DIRECTION OUTPUT ;
    USE SIGNAL ;
    PORT
      LAYER Metal2 ;
        RECT  109.9 277.83 110.18 278.35 ;
    END
  END b[39]
  PIN b[3]
    DIRECTION OUTPUT ;
    USE SIGNAL ;
    PORT
      LAYER Metal2 ;
        RECT  214.06 277.83 214.34 278.35 ;
    END
  END b[3]
  PIN b[40]
    DIRECTION OUTPUT ;
    USE SIGNAL ;
    PORT
      LAYER Metal2 ;
        RECT  193.9 277.83 194.18 278.35 ;
    END
  END b[40]
  PIN b[41]
    DIRECTION OUTPUT ;
    USE SIGNAL ;
    PORT
      LAYER Metal2 ;
        RECT  119.98 277.83 120.26 278.35 ;
    END
  END b[41]
  PIN b[42]
    DIRECTION OUTPUT ;
    USE SIGNAL ;
    PORT
      LAYER Metal2 ;
        RECT  186.06 277.83 186.34 278.35 ;
    END
  END b[42]
  PIN b[43]
    DIRECTION OUTPUT ;
    USE SIGNAL ;
    PORT
      LAYER Metal2 ;
        RECT  221.9 277.83 222.18 278.35 ;
    END
  END b[43]
  PIN b[44]
    DIRECTION OUTPUT ;
    USE SIGNAL ;
    PORT
      LAYER Metal2 ;
        RECT  107.66 277.83 107.94 278.35 ;
    END
  END b[44]
  PIN b[45]
    DIRECTION OUTPUT ;
    USE SIGNAL ;
    PORT
      LAYER Metal2 ;
        RECT  210.7 277.83 210.98 278.35 ;
    END
  END b[45]
  PIN b[46]
    DIRECTION OUTPUT ;
    USE SIGNAL ;
    PORT
      LAYER Metal2 ;
        RECT  181.58 277.83 181.86 278.35 ;
    END
  END b[46]
  PIN b[47]
    DIRECTION OUTPUT ;
    USE SIGNAL ;
    PORT
      LAYER Metal2 ;
        RECT  68.46 277.83 68.74 278.35 ;
    END
  END b[47]
  PIN b[48]
    DIRECTION OUTPUT ;
    USE SIGNAL ;
    PORT
      LAYER Metal2 ;
        RECT  69.58 277.83 69.86 278.35 ;
    END
  END b[48]
  PIN b[49]
    DIRECTION OUTPUT ;
    USE SIGNAL ;
    PORT
      LAYER Metal2 ;
        RECT  211.82 277.83 212.1 278.35 ;
    END
  END b[49]
  PIN b[4]
    DIRECTION OUTPUT ;
    USE SIGNAL ;
    PORT
      LAYER Metal2 ;
        RECT  108.78 277.83 109.06 278.35 ;
    END
  END b[4]
  PIN b[50]
    DIRECTION OUTPUT ;
    USE SIGNAL ;
    PORT
      LAYER Metal2 ;
        RECT  62.86 277.83 63.14 278.35 ;
    END
  END b[50]
  PIN b[51]
    DIRECTION OUTPUT ;
    USE SIGNAL ;
    PORT
      LAYER Metal2 ;
        RECT  224.14 277.83 224.42 278.35 ;
    END
  END b[51]
  PIN b[52]
    DIRECTION OUTPUT ;
    USE SIGNAL ;
    PORT
      LAYER Metal2 ;
        RECT  225.26 277.83 225.54 278.35 ;
    END
  END b[52]
  PIN b[53]
    DIRECTION OUTPUT ;
    USE SIGNAL ;
    PORT
      LAYER Metal2 ;
        RECT  116.62 277.83 116.9 278.35 ;
    END
  END b[53]
  PIN b[54]
    DIRECTION OUTPUT ;
    USE SIGNAL ;
    PORT
      LAYER Metal2 ;
        RECT  169.26 277.83 169.54 278.35 ;
    END
  END b[54]
  PIN b[55]
    DIRECTION OUTPUT ;
    USE SIGNAL ;
    PORT
      LAYER Metal2 ;
        RECT  227.5 277.83 227.78 278.35 ;
    END
  END b[55]
  PIN b[56]
    DIRECTION OUTPUT ;
    USE SIGNAL ;
    PORT
      LAYER Metal2 ;
        RECT  223.02 277.83 223.3 278.35 ;
    END
  END b[56]
  PIN b[57]
    DIRECTION OUTPUT ;
    USE SIGNAL ;
    PORT
      LAYER Metal2 ;
        RECT  226.38 277.83 226.66 278.35 ;
    END
  END b[57]
  PIN b[58]
    DIRECTION OUTPUT ;
    USE SIGNAL ;
    PORT
      LAYER Metal2 ;
        RECT  205.1 277.83 205.38 278.35 ;
    END
  END b[58]
  PIN b[59]
    DIRECTION OUTPUT ;
    USE SIGNAL ;
    PORT
      LAYER Metal2 ;
        RECT  106.54 277.83 106.82 278.35 ;
    END
  END b[59]
  PIN b[5]
    DIRECTION OUTPUT ;
    USE SIGNAL ;
    PORT
      LAYER Metal2 ;
        RECT  164.78 277.83 165.06 278.35 ;
    END
  END b[5]
  PIN b[60]
    DIRECTION OUTPUT ;
    USE SIGNAL ;
    PORT
      LAYER Metal2 ;
        RECT  208.46 277.83 208.74 278.35 ;
    END
  END b[60]
  PIN b[61]
    DIRECTION OUTPUT ;
    USE SIGNAL ;
    PORT
      LAYER Metal2 ;
        RECT  61.74 277.83 62.02 278.35 ;
    END
  END b[61]
  PIN b[62]
    DIRECTION OUTPUT ;
    USE SIGNAL ;
    PORT
      LAYER Metal2 ;
        RECT  152.46 277.83 152.74 278.35 ;
    END
  END b[62]
  PIN b[63]
    DIRECTION OUTPUT ;
    USE SIGNAL ;
    PORT
      LAYER Metal2 ;
        RECT  104.3 277.83 104.58 278.35 ;
    END
  END b[63]
  PIN b[6]
    DIRECTION OUTPUT ;
    USE SIGNAL ;
    PORT
      LAYER Metal2 ;
        RECT  228.62 277.83 228.9 278.35 ;
    END
  END b[6]
  PIN b[7]
    DIRECTION OUTPUT ;
    USE SIGNAL ;
    PORT
      LAYER Metal2 ;
        RECT  207.34 277.83 207.62 278.35 ;
    END
  END b[7]
  PIN b[8]
    DIRECTION OUTPUT ;
    USE SIGNAL ;
    PORT
      LAYER Metal2 ;
        RECT  147.98 277.83 148.26 278.35 ;
    END
  END b[8]
  PIN b[9]
    DIRECTION OUTPUT ;
    USE SIGNAL ;
    PORT
      LAYER Metal2 ;
        RECT  202.86 277.83 203.14 278.35 ;
    END
  END b[9]
  PIN c1
    DIRECTION INPUT ;
    USE SIGNAL ;
    PORT
      LAYER Metal2 ;
        RECT  229.74 277.83 230.02 278.35 ;
    END
  END c1
  PIN c2
    DIRECTION INPUT ;
    USE SIGNAL ;
    PORT
      LAYER Metal2 ;
        RECT  1.26 0 1.54 0.52 ;
    END
  END c2
  PIN cin
    DIRECTION OUTPUT ;
    USE SIGNAL ;
    PORT
      LAYER Metal2 ;
        RECT  103.18 277.83 103.46 278.35 ;
    END
  END cin
  PIN correct
    DIRECTION OUTPUT ;
    USE SIGNAL ;
    PORT
      LAYER Metal2 ;
        RECT  143.5 277.83 143.78 278.35 ;
    END
  END correct
  PIN incorrect
    DIRECTION OUTPUT ;
    USE SIGNAL ;
    PORT
      LAYER Metal2 ;
        RECT  230.86 277.83 231.14 278.35 ;
    END
  END incorrect
  PIN result[0]
    DIRECTION INPUT ;
    USE SIGNAL ;
    PORT
      LAYER Metal2 ;
        RECT  139.02 277.83 139.3 278.35 ;
    END
  END result[0]
  PIN result[10]
    DIRECTION INPUT ;
    USE SIGNAL ;
    PORT
      LAYER Metal2 ;
        RECT  60.62 277.83 60.9 278.35 ;
    END
  END result[10]
  PIN result[11]
    DIRECTION INPUT ;
    USE SIGNAL ;
    PORT
      LAYER Metal2 ;
        RECT  231.98 277.83 232.26 278.35 ;
    END
  END result[11]
  PIN result[12]
    DIRECTION INPUT ;
    USE SIGNAL ;
    PORT
      LAYER Metal2 ;
        RECT  233.1 277.83 233.38 278.35 ;
    END
  END result[12]
  PIN result[13]
    DIRECTION INPUT ;
    USE SIGNAL ;
    PORT
      LAYER Metal2 ;
        RECT  234.22 277.83 234.5 278.35 ;
    END
  END result[13]
  PIN result[14]
    DIRECTION INPUT ;
    USE SIGNAL ;
    PORT
      LAYER Metal2 ;
        RECT  100.94 277.83 101.22 278.35 ;
    END
  END result[14]
  PIN result[15]
    DIRECTION INPUT ;
    USE SIGNAL ;
    PORT
      LAYER Metal2 ;
        RECT  235.34 277.83 235.62 278.35 ;
    END
  END result[15]
  PIN result[16]
    DIRECTION INPUT ;
    USE SIGNAL ;
    PORT
      LAYER Metal2 ;
        RECT  236.46 277.83 236.74 278.35 ;
    END
  END result[16]
  PIN result[17]
    DIRECTION INPUT ;
    USE SIGNAL ;
    PORT
      LAYER Metal2 ;
        RECT  237.58 277.83 237.86 278.35 ;
    END
  END result[17]
  PIN result[18]
    DIRECTION INPUT ;
    USE SIGNAL ;
    PORT
      LAYER Metal2 ;
        RECT  99.82 277.83 100.1 278.35 ;
    END
  END result[18]
  PIN result[19]
    DIRECTION INPUT ;
    USE SIGNAL ;
    PORT
      LAYER Metal2 ;
        RECT  238.7 277.83 238.98 278.35 ;
    END
  END result[19]
  PIN result[1]
    DIRECTION INPUT ;
    USE SIGNAL ;
    PORT
      LAYER Metal2 ;
        RECT  59.5 277.83 59.78 278.35 ;
    END
  END result[1]
  PIN result[20]
    DIRECTION INPUT ;
    USE SIGNAL ;
    PORT
      LAYER Metal2 ;
        RECT  239.82 277.83 240.1 278.35 ;
    END
  END result[20]
  PIN result[21]
    DIRECTION INPUT ;
    USE SIGNAL ;
    PORT
      LAYER Metal2 ;
        RECT  98.7 277.83 98.98 278.35 ;
    END
  END result[21]
  PIN result[22]
    DIRECTION INPUT ;
    USE SIGNAL ;
    PORT
      LAYER Metal2 ;
        RECT  240.94 277.83 241.22 278.35 ;
    END
  END result[22]
  PIN result[23]
    DIRECTION INPUT ;
    USE SIGNAL ;
    PORT
      LAYER Metal2 ;
        RECT  242.06 277.83 242.34 278.35 ;
    END
  END result[23]
  PIN result[24]
    DIRECTION INPUT ;
    USE SIGNAL ;
    PORT
      LAYER Metal2 ;
        RECT  243.18 277.83 243.46 278.35 ;
    END
  END result[24]
  PIN result[25]
    DIRECTION INPUT ;
    USE SIGNAL ;
    PORT
      LAYER Metal2 ;
        RECT  97.58 277.83 97.86 278.35 ;
    END
  END result[25]
  PIN result[26]
    DIRECTION INPUT ;
    USE SIGNAL ;
    PORT
      LAYER Metal2 ;
        RECT  244.3 277.83 244.58 278.35 ;
    END
  END result[26]
  PIN result[27]
    DIRECTION INPUT ;
    USE SIGNAL ;
    PORT
      LAYER Metal2 ;
        RECT  245.42 277.83 245.7 278.35 ;
    END
  END result[27]
  PIN result[28]
    DIRECTION INPUT ;
    USE SIGNAL ;
    PORT
      LAYER Metal2 ;
        RECT  246.54 277.83 246.82 278.35 ;
    END
  END result[28]
  PIN result[29]
    DIRECTION INPUT ;
    USE SIGNAL ;
    PORT
      LAYER Metal2 ;
        RECT  96.46 277.83 96.74 278.35 ;
    END
  END result[29]
  PIN result[2]
    DIRECTION INPUT ;
    USE SIGNAL ;
    PORT
      LAYER Metal2 ;
        RECT  58.38 277.83 58.66 278.35 ;
    END
  END result[2]
  PIN result[30]
    DIRECTION INPUT ;
    USE SIGNAL ;
    PORT
      LAYER Metal2 ;
        RECT  133.42 277.83 133.7 278.35 ;
    END
  END result[30]
  PIN result[31]
    DIRECTION INPUT ;
    USE SIGNAL ;
    PORT
      LAYER Metal2 ;
        RECT  247.66 277.83 247.94 278.35 ;
    END
  END result[31]
  PIN result[32]
    DIRECTION INPUT ;
    USE SIGNAL ;
    PORT
      LAYER Metal2 ;
        RECT  95.34 277.83 95.62 278.35 ;
    END
  END result[32]
  PIN result[33]
    DIRECTION INPUT ;
    USE SIGNAL ;
    PORT
      LAYER Metal2 ;
        RECT  248.78 277.83 249.06 278.35 ;
    END
  END result[33]
  PIN result[34]
    DIRECTION INPUT ;
    USE SIGNAL ;
    PORT
      LAYER Metal2 ;
        RECT  177.1 277.83 177.38 278.35 ;
    END
  END result[34]
  PIN result[35]
    DIRECTION INPUT ;
    USE SIGNAL ;
    PORT
      LAYER Metal2 ;
        RECT  249.9 277.83 250.18 278.35 ;
    END
  END result[35]
  PIN result[36]
    DIRECTION INPUT ;
    USE SIGNAL ;
    PORT
      LAYER Metal2 ;
        RECT  94.22 277.83 94.5 278.35 ;
    END
  END result[36]
  PIN result[37]
    DIRECTION INPUT ;
    USE SIGNAL ;
    PORT
      LAYER Metal2 ;
        RECT  251.02 277.83 251.3 278.35 ;
    END
  END result[37]
  PIN result[38]
    DIRECTION INPUT ;
    USE SIGNAL ;
    PORT
      LAYER Metal2 ;
        RECT  252.14 277.83 252.42 278.35 ;
    END
  END result[38]
  PIN result[39]
    DIRECTION INPUT ;
    USE SIGNAL ;
    PORT
      LAYER Metal2 ;
        RECT  57.26 277.83 57.54 278.35 ;
    END
  END result[39]
  PIN result[3]
    DIRECTION INPUT ;
    USE SIGNAL ;
    PORT
      LAYER Metal2 ;
        RECT  93.1 277.83 93.38 278.35 ;
    END
  END result[3]
  PIN result[40]
    DIRECTION INPUT ;
    USE SIGNAL ;
    PORT
      LAYER Metal2 ;
        RECT  253.26 277.83 253.54 278.35 ;
    END
  END result[40]
  PIN result[41]
    DIRECTION INPUT ;
    USE SIGNAL ;
    PORT
      LAYER Metal2 ;
        RECT  254.38 277.83 254.66 278.35 ;
    END
  END result[41]
  PIN result[42]
    DIRECTION INPUT ;
    USE SIGNAL ;
    PORT
      LAYER Metal2 ;
        RECT  156.94 277.83 157.22 278.35 ;
    END
  END result[42]
  PIN result[43]
    DIRECTION INPUT ;
    USE SIGNAL ;
    PORT
      LAYER Metal2 ;
        RECT  91.98 277.83 92.26 278.35 ;
    END
  END result[43]
  PIN result[44]
    DIRECTION INPUT ;
    USE SIGNAL ;
    PORT
      LAYER Metal2 ;
        RECT  255.5 277.83 255.78 278.35 ;
    END
  END result[44]
  PIN result[45]
    DIRECTION INPUT ;
    USE SIGNAL ;
    PORT
      LAYER Metal2 ;
        RECT  256.62 277.83 256.9 278.35 ;
    END
  END result[45]
  PIN result[46]
    DIRECTION INPUT ;
    USE SIGNAL ;
    PORT
      LAYER Metal2 ;
        RECT  257.74 277.83 258.02 278.35 ;
    END
  END result[46]
  PIN result[47]
    DIRECTION INPUT ;
    USE SIGNAL ;
    PORT
      LAYER Metal2 ;
        RECT  90.86 277.83 91.14 278.35 ;
    END
  END result[47]
  PIN result[48]
    DIRECTION INPUT ;
    USE SIGNAL ;
    PORT
      LAYER Metal2 ;
        RECT  258.86 277.83 259.14 278.35 ;
    END
  END result[48]
  PIN result[49]
    DIRECTION INPUT ;
    USE SIGNAL ;
    PORT
      LAYER Metal2 ;
        RECT  142.38 277.83 142.66 278.35 ;
    END
  END result[49]
  PIN result[4]
    DIRECTION INPUT ;
    USE SIGNAL ;
    PORT
      LAYER Metal2 ;
        RECT  56.14 277.83 56.42 278.35 ;
    END
  END result[4]
  PIN result[50]
    DIRECTION INPUT ;
    USE SIGNAL ;
    PORT
      LAYER Metal2 ;
        RECT  89.74 277.83 90.02 278.35 ;
    END
  END result[50]
  PIN result[51]
    DIRECTION INPUT ;
    USE SIGNAL ;
    PORT
      LAYER Metal2 ;
        RECT  127.82 277.83 128.1 278.35 ;
    END
  END result[51]
  PIN result[52]
    DIRECTION INPUT ;
    USE SIGNAL ;
    PORT
      LAYER Metal2 ;
        RECT  259.98 277.83 260.26 278.35 ;
    END
  END result[52]
  PIN result[53]
    DIRECTION INPUT ;
    USE SIGNAL ;
    PORT
      LAYER Metal2 ;
        RECT  261.1 277.83 261.38 278.35 ;
    END
  END result[53]
  PIN result[54]
    DIRECTION INPUT ;
    USE SIGNAL ;
    PORT
      LAYER Metal2 ;
        RECT  88.62 277.83 88.9 278.35 ;
    END
  END result[54]
  PIN result[55]
    DIRECTION INPUT ;
    USE SIGNAL ;
    PORT
      LAYER Metal2 ;
        RECT  262.22 277.83 262.5 278.35 ;
    END
  END result[55]
  PIN result[56]
    DIRECTION INPUT ;
    USE SIGNAL ;
    PORT
      LAYER Metal2 ;
        RECT  263.34 277.83 263.62 278.35 ;
    END
  END result[56]
  PIN result[57]
    DIRECTION INPUT ;
    USE SIGNAL ;
    PORT
      LAYER Metal2 ;
        RECT  55.02 277.83 55.3 278.35 ;
    END
  END result[57]
  PIN result[58]
    DIRECTION INPUT ;
    USE SIGNAL ;
    PORT
      LAYER Metal2 ;
        RECT  87.5 277.83 87.78 278.35 ;
    END
  END result[58]
  PIN result[59]
    DIRECTION INPUT ;
    USE SIGNAL ;
    PORT
      LAYER Metal2 ;
        RECT  264.46 277.83 264.74 278.35 ;
    END
  END result[59]
  PIN result[5]
    DIRECTION INPUT ;
    USE SIGNAL ;
    PORT
      LAYER Metal2 ;
        RECT  265.58 277.83 265.86 278.35 ;
    END
  END result[5]
  PIN result[60]
    DIRECTION INPUT ;
    USE SIGNAL ;
    PORT
      LAYER Metal2 ;
        RECT  266.7 277.83 266.98 278.35 ;
    END
  END result[60]
  PIN result[61]
    DIRECTION INPUT ;
    USE SIGNAL ;
    PORT
      LAYER Metal2 ;
        RECT  86.38 277.83 86.66 278.35 ;
    END
  END result[61]
  PIN result[62]
    DIRECTION INPUT ;
    USE SIGNAL ;
    PORT
      LAYER Metal2 ;
        RECT  267.82 277.83 268.1 278.35 ;
    END
  END result[62]
  PIN result[63]
    DIRECTION INPUT ;
    USE SIGNAL ;
    PORT
      LAYER Metal2 ;
        RECT  268.94 277.83 269.22 278.35 ;
    END
  END result[63]
  PIN result[64]
    DIRECTION INPUT ;
    USE SIGNAL ;
    PORT
      LAYER Metal2 ;
        RECT  270.06 277.83 270.34 278.35 ;
    END
  END result[64]
  PIN result[6]
    DIRECTION INPUT ;
    USE SIGNAL ;
    PORT
      LAYER Metal2 ;
        RECT  85.26 277.83 85.54 278.35 ;
    END
  END result[6]
  PIN result[7]
    DIRECTION INPUT ;
    USE SIGNAL ;
    PORT
      LAYER Metal2 ;
        RECT  271.18 277.83 271.46 278.35 ;
    END
  END result[7]
  PIN result[8]
    DIRECTION INPUT ;
    USE SIGNAL ;
    PORT
      LAYER Metal2 ;
        RECT  272.3 277.83 272.58 278.35 ;
    END
  END result[8]
  PIN result[9]
    DIRECTION INPUT ;
    USE SIGNAL ;
    PORT
      LAYER Metal2 ;
        RECT  53.9 277.83 54.18 278.35 ;
    END
  END result[9]
  OBS
    LAYER Pwell ;
     RECT  81.89 9.65 88.35 12.345 ;
     RECT  74.05 17.895 94.51 19.73 ;
     RECT  118.85 17.895 128.67 19.73 ;
     RECT  132.85 17.895 142.11 19.73 ;
     RECT  160.85 17.895 177.39 19.73 ;
     RECT  74.05 19.73 104.03 20.59 ;
     RECT  110.45 19.73 177.39 20.59 ;
     RECT  76.29 20.59 104.03 22.425 ;
     RECT  110.45 20.59 167.87 22.425 ;
     RECT  58.37 27.975 63.71 29.81 ;
     RECT  74.05 27.975 110.19 29.81 ;
     RECT  113.81 27.975 138.75 29.81 ;
     RECT  139.57 27.975 151.63 29.81 ;
     RECT  151.89 27.975 159.47 29.81 ;
     RECT  160.29 27.975 176.83 29.81 ;
     RECT  74.05 29.81 151.63 30.67 ;
     RECT  151.89 29.81 180.19 30.67 ;
     RECT  55.01 29.81 71.55 32.505 ;
     RECT  86.37 30.67 92.83 32.505 ;
     RECT  95.89 30.67 104.59 32.505 ;
     RECT  104.85 30.67 114.67 32.505 ;
     RECT  118.85 30.67 147.71 32.505 ;
     RECT  155.25 30.67 180.19 32.505 ;
     RECT  207.89 29.81 224.43 32.505 ;
     RECT  58.93 38.055 118.03 39.89 ;
     RECT  129.49 38.055 159.47 39.89 ;
     RECT  164.77 38.055 193.63 39.89 ;
     RECT  200.61 38.055 224.43 39.89 ;
     RECT  48.85 39.89 232.83 40.75 ;
     RECT  48.85 40.75 63.15 42.585 ;
     RECT  90.29 40.75 105.71 42.585 ;
     RECT  106.53 40.75 143.79 42.585 ;
     RECT  154.69 40.75 171.23 42.585 ;
     RECT  188.29 40.75 232.83 42.585 ;
     RECT  34.29 48.135 39.63 49.97 ;
     RECT  40.45 48.135 44.11 49.97 ;
     RECT  44.93 48.135 64.83 49.97 ;
     RECT  65.09 48.135 81.63 49.97 ;
     RECT  154.13 48.135 170.67 49.97 ;
     RECT  171.49 48.135 177.95 49.97 ;
     RECT  179.89 48.135 196.43 49.97 ;
     RECT  201.73 48.135 212.67 49.97 ;
     RECT  212.93 48.135 229.47 49.97 ;
     RECT  25.89 49.97 81.63 50.83 ;
     RECT  88.05 48.135 120.83 50.83 ;
     RECT  130.61 48.135 135.95 50.83 ;
     RECT  154.13 49.97 198.67 50.83 ;
     RECT  199.49 49.97 229.47 50.83 ;
     RECT  25.89 50.83 46.35 52.665 ;
     RECT  47.17 50.83 81.63 52.665 ;
     RECT  91.41 50.83 115.23 52.665 ;
     RECT  137.33 49.97 153.87 52.665 ;
     RECT  155.25 50.83 198.67 52.665 ;
     RECT  199.49 50.83 203.15 52.665 ;
     RECT  205.65 50.83 224.99 52.665 ;
     RECT  25.89 58.215 82.75 60.05 ;
     RECT  139.57 58.215 159.47 60.05 ;
     RECT  159.73 58.215 165.07 60.05 ;
     RECT  167.57 58.215 170.67 60.05 ;
     RECT  171.49 58.215 190.27 60.05 ;
     RECT  190.53 58.215 210.43 60.05 ;
     RECT  214.05 58.215 218.83 60.05 ;
     RECT  219.09 58.215 222.75 60.05 ;
     RECT  229.73 58.215 233.39 60.05 ;
     RECT  25.89 60.05 86.11 60.91 ;
     RECT  94.21 58.215 127.55 60.91 ;
     RECT  132.85 60.05 236.19 60.91 ;
     RECT  32.61 60.91 40.75 62.745 ;
     RECT  41.57 60.91 86.11 62.745 ;
     RECT  105.41 60.91 112.99 62.745 ;
     RECT  132.85 60.91 191.39 62.745 ;
     RECT  191.65 60.91 236.19 62.745 ;
     RECT  237.57 60.05 244.03 62.745 ;
     RECT  248.21 60.05 264.75 62.745 ;
     RECT  37.65 68.295 45.23 70.13 ;
     RECT  45.49 68.295 86.67 70.13 ;
     RECT  91.41 68.295 126.99 70.13 ;
     RECT  129.49 68.295 137.07 70.13 ;
     RECT  169.81 68.295 185.23 70.13 ;
     RECT  186.05 68.295 213.23 70.13 ;
     RECT  216.85 68.295 263.07 70.13 ;
     RECT  29.81 70.13 86.67 70.99 ;
     RECT  91.41 70.13 137.63 70.99 ;
     RECT  148.53 68.295 156.67 70.99 ;
     RECT  169.25 70.13 185.23 70.99 ;
     RECT  186.05 70.13 267.55 70.99 ;
     RECT  29.81 70.99 46.35 72.825 ;
     RECT  48.29 70.99 80.51 72.825 ;
     RECT  101.49 70.99 137.63 72.825 ;
     RECT  142.37 70.13 147.15 72.825 ;
     RECT  169.25 70.99 178.51 72.825 ;
     RECT  178.77 70.99 182.43 72.825 ;
     RECT  189.41 70.99 209.87 72.825 ;
     RECT  211.25 70.99 217.15 72.825 ;
     RECT  223.01 70.99 267.55 72.825 ;
     RECT  52.21 78.375 56.43 80.21 ;
     RECT  56.69 78.375 73.23 80.21 ;
     RECT  76.29 78.375 96.19 80.21 ;
     RECT  99.25 78.375 115.79 80.21 ;
     RECT  116.61 78.375 144.35 80.21 ;
     RECT  145.17 78.375 154.43 80.21 ;
     RECT  169.25 78.375 179.63 80.21 ;
     RECT  203.41 78.375 210.99 80.21 ;
     RECT  211.81 78.375 219.39 80.21 ;
     RECT  52.21 80.21 74.91 81.07 ;
     RECT  76.29 80.21 144.35 81.07 ;
     RECT  197.25 78.375 200.91 81.07 ;
     RECT  203.41 80.21 219.39 81.07 ;
     RECT  221.33 78.375 268.11 81.07 ;
     RECT  34.85 80.21 51.39 82.905 ;
     RECT  52.77 81.07 74.91 82.905 ;
     RECT  80.21 81.07 88.35 82.905 ;
     RECT  90.29 81.07 142.67 82.905 ;
     RECT  145.17 80.21 161.71 82.905 ;
     RECT  164.21 80.21 182.99 82.905 ;
     RECT  187.17 80.21 196.43 82.905 ;
     RECT  209.01 81.07 213.79 82.905 ;
     RECT  232.53 81.07 242.91 82.905 ;
     RECT  243.73 81.07 251.87 82.905 ;
     RECT  86.93 88.455 131.47 90.29 ;
     RECT  132.29 88.455 157.23 90.29 ;
     RECT  164.21 88.455 185.79 90.29 ;
     RECT  187.17 88.455 203.71 90.29 ;
     RECT  207.33 88.455 212.67 90.29 ;
     RECT  214.61 88.455 219.95 90.29 ;
     RECT  230.29 88.455 233.39 90.29 ;
     RECT  235.89 88.455 244.03 90.29 ;
     RECT  252.13 88.455 260.27 90.29 ;
     RECT  83.57 90.29 157.79 91.15 ;
     RECT  161.41 90.29 203.71 91.15 ;
     RECT  207.33 90.29 264.19 91.15 ;
     RECT  62.85 90.29 70.99 92.985 ;
     RECT  83.57 91.15 100.11 92.985 ;
     RECT  102.61 91.15 118.59 92.985 ;
     RECT  121.65 91.15 138.19 92.985 ;
     RECT  141.25 91.15 157.79 92.985 ;
     RECT  161.41 91.15 174.59 92.985 ;
     RECT  174.85 91.15 190.27 92.985 ;
     RECT  207.89 91.15 264.19 92.985 ;
     RECT  43.81 98.535 47.47 100.37 ;
     RECT  154.69 98.535 190.27 100.37 ;
     RECT  194.45 98.535 215.47 100.37 ;
     RECT  217.97 98.535 255.79 100.37 ;
     RECT  86.37 98.535 110.19 101.23 ;
     RECT  116.05 98.535 154.43 101.23 ;
     RECT  154.69 100.37 264.19 101.23 ;
     RECT  40.45 100.37 50.27 103.065 ;
     RECT  50.53 100.37 56.99 103.065 ;
     RECT  59.49 98.535 76.03 103.065 ;
     RECT  86.37 101.23 109.07 103.065 ;
     RECT  128.37 101.23 135.95 103.065 ;
     RECT  137.89 101.23 150.51 103.065 ;
     RECT  154.69 101.23 170.67 103.065 ;
     RECT  173.73 101.23 188.03 103.065 ;
     RECT  188.85 101.23 213.79 103.065 ;
     RECT  214.61 101.23 231.15 103.065 ;
     RECT  231.97 101.23 247.39 103.065 ;
     RECT  247.65 101.23 264.19 103.065 ;
     RECT  34.85 108.615 51.39 110.45 ;
     RECT  52.77 108.615 91.15 110.45 ;
     RECT  96.45 108.615 111.87 110.45 ;
     RECT  113.25 108.615 129.79 110.45 ;
     RECT  137.33 108.615 145.47 110.45 ;
     RECT  167.01 108.615 183.55 110.45 ;
     RECT  183.81 108.615 194.19 110.45 ;
     RECT  194.45 108.615 200.35 110.45 ;
     RECT  202.85 108.615 210.43 110.45 ;
     RECT  213.49 108.615 222.75 110.45 ;
     RECT  223.01 108.615 239.55 110.45 ;
     RECT  244.85 108.615 260.27 110.45 ;
     RECT  34.85 110.45 145.47 111.31 ;
     RECT  145.73 108.615 166.19 111.31 ;
     RECT  167.01 110.45 266.43 111.31 ;
     RECT  36.53 111.31 73.23 113.145 ;
     RECT  89.17 111.31 105.71 113.145 ;
     RECT  105.97 111.31 145.47 113.145 ;
     RECT  145.73 111.31 162.27 113.145 ;
     RECT  170.93 111.31 186.91 113.145 ;
     RECT  193.89 111.31 203.15 113.145 ;
     RECT  207.89 111.31 266.43 113.145 ;
     RECT  38.21 118.695 65.95 120.53 ;
     RECT  66.77 118.695 106.83 120.53 ;
     RECT  113.81 118.695 135.95 120.53 ;
     RECT  169.25 118.695 198.67 120.53 ;
     RECT  225.81 118.695 249.07 120.53 ;
     RECT  252.13 118.695 260.27 120.53 ;
     RECT  36.53 120.53 135.95 121.39 ;
     RECT  152.45 118.695 156.11 121.39 ;
     RECT  165.33 120.53 199.23 121.39 ;
     RECT  210.13 118.695 217.71 121.39 ;
     RECT  225.81 120.53 264.19 121.39 ;
     RECT  13.57 120.53 30.11 123.225 ;
     RECT  36.53 121.39 53.07 123.225 ;
     RECT  56.13 121.39 77.15 123.225 ;
     RECT  84.69 121.39 101.23 123.225 ;
     RECT  103.73 121.39 119.15 123.225 ;
     RECT  125.57 121.39 128.67 123.225 ;
     RECT  141.25 120.53 148.83 123.225 ;
     RECT  158.61 120.53 165.07 123.225 ;
     RECT  165.33 121.39 181.87 123.225 ;
     RECT  182.69 121.39 199.23 123.225 ;
     RECT  200.05 120.53 209.87 123.225 ;
     RECT  233.65 121.39 264.19 123.225 ;
     RECT  37.65 128.775 51.39 130.61 ;
     RECT  53.89 128.775 82.75 130.61 ;
     RECT  87.49 128.775 104.03 130.61 ;
     RECT  107.65 128.775 139.87 130.61 ;
     RECT  140.13 128.775 147.71 130.61 ;
     RECT  154.13 128.775 161.71 130.61 ;
     RECT  165.33 128.775 194.19 130.61 ;
     RECT  198.37 128.775 216.03 130.61 ;
     RECT  236.45 128.775 260.27 130.61 ;
     RECT  14.69 128.775 34.03 131.47 ;
     RECT  37.65 130.61 104.03 131.47 ;
     RECT  106.53 130.61 216.03 131.47 ;
     RECT  16.37 131.47 28.99 133.305 ;
     RECT  46.61 131.47 73.79 133.305 ;
     RECT  74.05 131.47 90.59 133.305 ;
     RECT  91.41 131.47 99.55 133.305 ;
     RECT  106.53 131.47 165.63 133.305 ;
     RECT  180.45 131.47 185.79 133.305 ;
     RECT  192.21 131.47 198.67 133.305 ;
     RECT  201.17 131.47 214.35 133.305 ;
     RECT  231.97 130.61 264.19 133.305 ;
     RECT  19.73 138.855 27.31 140.69 ;
     RECT  45.49 138.855 70.43 140.69 ;
     RECT  76.85 138.855 101.23 140.69 ;
     RECT  116.61 138.855 145.47 140.69 ;
     RECT  147.41 138.855 170.67 140.69 ;
     RECT  174.29 138.855 193.07 140.69 ;
     RECT  194.45 138.855 202.03 140.69 ;
     RECT  202.29 138.855 221.63 140.69 ;
     RECT  235.33 138.855 250.75 140.69 ;
     RECT  45.49 140.69 73.79 141.55 ;
     RECT  76.85 140.69 105.71 141.55 ;
     RECT  109.89 140.69 170.67 141.55 ;
     RECT  174.29 140.69 227.79 141.55 ;
     RECT  229.17 140.69 250.75 141.55 ;
     RECT  15.25 140.69 34.59 143.385 ;
     RECT  56.13 141.55 73.79 143.385 ;
     RECT  89.17 141.55 105.71 143.385 ;
     RECT  109.89 141.55 126.43 143.385 ;
     RECT  131.73 141.55 170.11 143.385 ;
     RECT  192.77 141.55 202.59 143.385 ;
     RECT  206.77 141.55 227.79 143.385 ;
     RECT  229.17 141.55 245.71 143.385 ;
     RECT  252.13 140.69 260.27 143.385 ;
     RECT  13.01 148.935 36.83 150.77 ;
     RECT  56.13 148.935 76.03 150.77 ;
     RECT  90.29 148.935 106.83 150.77 ;
     RECT  112.13 148.935 127.55 150.77 ;
     RECT  132.29 148.935 148.83 150.77 ;
     RECT  149.09 148.935 155.55 150.77 ;
     RECT  177.65 148.935 181.31 150.77 ;
     RECT  182.13 148.935 185.79 150.77 ;
     RECT  191.65 148.935 196.43 150.77 ;
     RECT  213.49 148.935 221.07 150.77 ;
     RECT  245.97 148.935 262.51 150.77 ;
     RECT  10.21 150.77 36.83 151.63 ;
     RECT  56.13 150.77 76.59 151.63 ;
     RECT  82.45 150.77 106.83 151.63 ;
     RECT  107.65 150.77 167.87 151.63 ;
     RECT  208.45 150.77 221.07 151.63 ;
     RECT  245.97 150.77 263.07 151.63 ;
     RECT  10.21 151.63 36.27 153.465 ;
     RECT  60.05 151.63 76.59 153.465 ;
     RECT  82.45 151.63 98.99 153.465 ;
     RECT  107.65 151.63 114.67 153.465 ;
     RECT  115.49 151.63 134.27 153.465 ;
     RECT  145.17 151.63 167.87 153.465 ;
     RECT  174.85 150.77 197.55 153.465 ;
     RECT  208.45 151.63 219.39 153.465 ;
     RECT  246.53 151.63 263.07 153.465 ;
     RECT  257.47 158.985 266.395 159.015 ;
     RECT  13.01 159.015 41.87 160.85 ;
     RECT  52.21 159.015 76.03 160.85 ;
     RECT  77.41 159.015 93.95 160.85 ;
     RECT  99.25 159.015 128.11 160.85 ;
     RECT  145.73 159.015 162.27 160.85 ;
     RECT  166.45 159.015 171.79 160.85 ;
     RECT  201.17 159.015 207.07 160.85 ;
     RECT  207.89 159.015 222.19 160.85 ;
     RECT  224.13 159.015 234.51 160.85 ;
     RECT  240.37 159.015 268.67 160.85 ;
     RECT  13.01 160.85 44.67 161.71 ;
     RECT  51.09 160.85 93.95 161.71 ;
     RECT  99.25 160.85 139.31 161.71 ;
     RECT  145.73 160.85 268.67 161.71 ;
     RECT  19.17 161.71 44.67 163.545 ;
     RECT  51.09 161.71 91.15 163.545 ;
     RECT  107.65 161.71 139.31 163.545 ;
     RECT  148.53 161.71 156.67 163.545 ;
     RECT  161.97 161.71 210.99 163.545 ;
     RECT  213.49 161.71 218.27 163.545 ;
     RECT  218.53 161.71 262.51 163.545 ;
     RECT  257.47 169.065 266.395 169.095 ;
     RECT  21.41 169.095 76.59 170.93 ;
     RECT  85.25 169.095 101.79 170.93 ;
     RECT  104.29 169.095 107.95 170.93 ;
     RECT  108.77 169.095 137.07 170.93 ;
     RECT  155.81 169.095 163.95 170.93 ;
     RECT  174.85 169.095 194.19 170.93 ;
     RECT  204.53 169.095 225.55 170.93 ;
     RECT  226.93 169.095 237.87 170.93 ;
     RECT  19.73 170.93 76.59 171.79 ;
     RECT  104.29 170.93 137.07 171.79 ;
     RECT  151.89 170.93 163.95 171.79 ;
     RECT  170.37 170.93 194.19 171.79 ;
     RECT  194.45 169.095 202.03 171.79 ;
     RECT  204.53 170.93 240.11 171.79 ;
     RECT  242.05 169.095 268.67 171.79 ;
     RECT  19.73 171.79 27.31 173.625 ;
     RECT  52.77 171.79 72.67 173.625 ;
     RECT  81.33 170.93 103.47 173.625 ;
     RECT  104.29 171.79 133.15 173.625 ;
     RECT  151.89 171.79 157.23 173.625 ;
     RECT  170.37 171.79 190.83 173.625 ;
     RECT  209.57 171.79 215.47 173.625 ;
     RECT  219.65 171.79 223.31 173.625 ;
     RECT  223.57 171.79 240.11 173.625 ;
     RECT  245.41 171.79 268.67 173.625 ;
     RECT  246.27 173.625 255.195 173.655 ;
     RECT  257.47 173.625 266.395 173.655 ;
     RECT  62.03 179.145 70.955 179.175 ;
     RECT  102.91 179.145 111.835 179.175 ;
     RECT  17.49 179.175 37.39 181.01 ;
     RECT  53.89 179.175 101.79 181.01 ;
     RECT  102.05 179.175 135.95 181.01 ;
     RECT  145.73 179.175 166.19 181.01 ;
     RECT  168.13 179.175 173.47 181.01 ;
     RECT  177.09 179.175 188.03 181.01 ;
     RECT  205.09 179.175 210.43 181.01 ;
     RECT  13.57 181.01 37.39 181.87 ;
     RECT  42.69 181.01 188.03 181.87 ;
     RECT  219.65 179.175 264.19 181.87 ;
     RECT  13.57 181.87 36.83 183.705 ;
     RECT  42.69 181.87 73.23 183.705 ;
     RECT  73.49 181.87 85.55 183.705 ;
     RECT  86.93 181.87 149.95 183.705 ;
     RECT  150.21 181.87 177.39 183.705 ;
     RECT  181.57 181.87 186.35 183.705 ;
     RECT  191.65 181.01 195.31 183.705 ;
     RECT  196.13 181.01 216.03 183.705 ;
     RECT  219.65 181.87 228.35 183.705 ;
     RECT  228.61 181.87 263.63 183.705 ;
     RECT  74.35 183.705 83.275 183.735 ;
     RECT  87.79 183.705 96.715 183.735 ;
     RECT  114.67 183.705 123.595 183.735 ;
     RECT  236.75 183.705 245.675 183.735 ;
     RECT  161.71 189.225 170.635 189.255 ;
     RECT  19.17 189.255 39.07 191.09 ;
     RECT  40.45 189.255 86.11 191.09 ;
     RECT  86.37 189.255 106.27 191.09 ;
     RECT  107.09 189.255 135.95 191.09 ;
     RECT  148.53 189.255 153.31 191.09 ;
     RECT  156.37 189.255 182.99 191.09 ;
     RECT  185.49 189.255 222.19 191.09 ;
     RECT  231.97 189.255 264.19 191.09 ;
     RECT  19.17 191.09 135.95 191.95 ;
     RECT  138.45 189.255 143.79 191.95 ;
     RECT  144.61 191.09 222.19 191.95 ;
     RECT  20.29 191.95 128.11 193.785 ;
     RECT  144.61 191.95 217.15 193.785 ;
     RECT  222.45 191.09 266.99 193.785 ;
     RECT  95.63 193.785 104.555 193.815 ;
     RECT  186.91 193.785 195.835 193.815 ;
     RECT  248.51 193.785 257.435 193.815 ;
     RECT  56.43 199.305 65.355 199.335 ;
     RECT  84.99 199.305 93.915 199.335 ;
     RECT  112.43 199.305 121.355 199.335 ;
     RECT  257.47 199.305 266.395 199.335 ;
     RECT  18.05 199.335 34.59 201.17 ;
     RECT  35.97 199.335 42.99 201.17 ;
     RECT  55.57 199.335 70.43 201.17 ;
     RECT  71.81 199.335 74.91 201.17 ;
     RECT  79.65 199.335 147.15 201.17 ;
     RECT  156.37 199.335 189.71 201.17 ;
     RECT  193.89 199.335 198.67 201.17 ;
     RECT  199.49 199.335 204.83 201.17 ;
     RECT  205.65 199.335 268.67 201.17 ;
     RECT  14.13 201.17 34.59 202.03 ;
     RECT  35.97 201.17 44.11 202.03 ;
     RECT  44.37 199.335 49.15 202.03 ;
     RECT  53.33 201.17 147.15 202.03 ;
     RECT  154.13 201.17 268.67 202.03 ;
     RECT  14.13 202.03 30.67 203.865 ;
     RECT  39.89 202.03 44.11 203.865 ;
     RECT  53.33 202.03 57.55 203.865 ;
     RECT  63.41 202.03 79.95 203.865 ;
     RECT  82.45 202.03 147.15 203.865 ;
     RECT  154.13 202.03 195.87 203.865 ;
     RECT  196.13 202.03 202.03 203.865 ;
     RECT  203.41 202.03 208.19 203.865 ;
     RECT  209.01 202.03 263.63 203.865 ;
     RECT  64.27 203.865 73.195 203.895 ;
     RECT  83.31 203.865 92.235 203.895 ;
     RECT  94.51 203.865 103.435 203.895 ;
     RECT  107.95 203.865 116.875 203.895 ;
     RECT  171.79 203.865 180.715 203.895 ;
     RECT  236.75 203.865 245.675 203.895 ;
     RECT  104.59 209.385 113.515 209.415 ;
     RECT  118.59 209.385 127.515 209.415 ;
     RECT  226.11 209.385 235.035 209.415 ;
     RECT  237.31 209.385 246.235 209.415 ;
     RECT  31.49 209.415 45.79 211.25 ;
     RECT  61.17 209.415 65.39 211.25 ;
     RECT  65.65 209.415 82.19 211.25 ;
     RECT  88.05 209.415 147.71 211.25 ;
     RECT  154.13 209.415 186.35 211.25 ;
     RECT  187.73 209.415 264.19 211.25 ;
     RECT  30.37 211.25 186.35 212.11 ;
     RECT  187.73 211.25 265.87 212.11 ;
     RECT  13.57 211.25 30.11 213.945 ;
     RECT  30.37 212.11 63.15 213.945 ;
     RECT  63.41 212.11 79.95 213.945 ;
     RECT  80.77 212.11 146.59 213.945 ;
     RECT  146.85 212.11 186.35 213.945 ;
     RECT  187.73 212.11 228.35 213.945 ;
     RECT  230.85 212.11 265.87 213.945 ;
     RECT  86.11 213.945 95.035 213.975 ;
     RECT  112.99 213.945 121.915 213.975 ;
     RECT  231.71 213.945 240.635 213.975 ;
     RECT  115.23 219.465 124.155 219.495 ;
     RECT  138.75 219.465 147.675 219.495 ;
     RECT  213.23 219.465 222.155 219.495 ;
     RECT  255.79 219.465 264.715 219.495 ;
     RECT  22.53 219.495 39.07 221.33 ;
     RECT  40.45 219.495 193.63 221.33 ;
     RECT  195.01 219.495 211.55 221.33 ;
     RECT  212.37 219.495 266.99 221.33 ;
     RECT  22.53 221.33 268.11 222.19 ;
     RECT  28.13 222.19 84.99 224.025 ;
     RECT  89.73 222.19 107.39 224.025 ;
     RECT  111.01 222.19 174.59 224.025 ;
     RECT  177.09 222.19 254.11 224.025 ;
     RECT  256.05 222.19 268.11 224.025 ;
     RECT  56.99 224.025 65.915 224.055 ;
     RECT  147.71 224.025 156.635 224.055 ;
     RECT  207.63 224.025 216.555 224.055 ;
     RECT  256.91 224.025 265.835 224.055 ;
     RECT  60.91 229.545 69.835 229.575 ;
     RECT  91.15 229.545 100.075 229.575 ;
     RECT  147.15 229.545 156.075 229.575 ;
     RECT  247.39 229.545 256.315 229.575 ;
     RECT  20.85 229.575 23.95 231.41 ;
     RECT  28.13 229.575 52.51 231.41 ;
     RECT  53.33 229.575 81.63 231.41 ;
     RECT  85.25 229.575 129.79 231.41 ;
     RECT  130.61 229.575 163.39 231.41 ;
     RECT  167.01 229.575 172.91 231.41 ;
     RECT  176.53 229.575 180.19 231.41 ;
     RECT  185.49 229.575 226.11 231.41 ;
     RECT  227.49 229.575 265.87 231.41 ;
     RECT  13.57 231.41 267.55 232.27 ;
     RECT  13.57 232.27 39.63 234.105 ;
     RECT  46.61 232.27 81.07 234.105 ;
     RECT  81.33 232.27 98.99 234.105 ;
     RECT  99.25 232.27 110.75 234.105 ;
     RECT  111.57 232.27 114.67 234.105 ;
     RECT  119.41 232.27 145.47 234.105 ;
     RECT  158.61 232.27 267.55 234.105 ;
     RECT  87.79 234.105 96.715 234.135 ;
     RECT  202.59 239.625 211.515 239.655 ;
     RECT  235.07 239.625 243.995 239.655 ;
     RECT  246.27 239.625 255.195 239.655 ;
     RECT  257.47 239.625 266.395 239.655 ;
     RECT  21.41 239.655 24.51 241.49 ;
     RECT  31.49 239.655 37.39 241.49 ;
     RECT  87.49 239.655 109.07 241.49 ;
     RECT  121.65 239.655 129.79 241.49 ;
     RECT  130.61 239.655 135.95 241.49 ;
     RECT  136.77 239.655 139.87 241.49 ;
     RECT  144.61 239.655 149.95 241.49 ;
     RECT  156.93 239.655 160.59 241.49 ;
     RECT  168.13 239.655 233.95 241.49 ;
     RECT  234.21 239.655 268.67 241.49 ;
     RECT  51.09 239.655 87.23 242.35 ;
     RECT  87.49 241.49 139.87 242.35 ;
     RECT  165.33 241.49 268.67 242.35 ;
     RECT  13.57 241.49 44.67 244.185 ;
     RECT  51.65 242.35 68.75 244.185 ;
     RECT  69.57 242.35 86.11 244.185 ;
     RECT  89.17 242.35 133.15 244.185 ;
     RECT  133.41 242.35 138.75 244.185 ;
     RECT  141.25 241.49 165.07 244.185 ;
     RECT  165.33 242.35 181.87 244.185 ;
     RECT  182.69 242.35 268.67 244.185 ;
     RECT  235.07 244.185 243.995 244.215 ;
     RECT  246.27 244.185 255.195 244.215 ;
     RECT  257.47 244.185 266.395 244.215 ;
     RECT  233.39 249.705 242.315 249.735 ;
     RECT  16.93 249.735 46.91 251.57 ;
     RECT  50.53 249.735 73.79 251.57 ;
     RECT  74.05 249.735 79.39 251.57 ;
     RECT  83.01 249.735 86.67 251.57 ;
     RECT  91.97 249.735 148.27 251.57 ;
     RECT  156.93 249.735 201.47 251.57 ;
     RECT  202.29 249.735 267.55 251.57 ;
     RECT  11.33 251.57 46.91 252.43 ;
     RECT  80.77 251.57 148.27 252.43 ;
     RECT  11.33 252.43 46.35 254.265 ;
     RECT  47.73 251.57 79.95 254.265 ;
     RECT  80.77 252.43 97.31 254.265 ;
     RECT  98.69 252.43 123.63 254.265 ;
     RECT  123.89 252.43 140.43 254.265 ;
     RECT  140.69 252.43 147.15 254.265 ;
     RECT  149.09 251.57 267.55 254.265 ;
     RECT  180.75 259.785 189.675 259.815 ;
     RECT  191.95 259.785 200.875 259.815 ;
     RECT  203.15 259.785 212.075 259.815 ;
     RECT  235.63 259.785 244.555 259.815 ;
     RECT  49.41 259.815 65.95 261.65 ;
     RECT  66.21 259.815 69.87 261.65 ;
     RECT  144.61 259.815 266.99 261.65 ;
     RECT  24.21 259.815 40.75 262.51 ;
     RECT  49.41 261.65 70.43 262.51 ;
     RECT  71.25 259.815 77.71 262.51 ;
     RECT  86.37 259.815 107.39 262.51 ;
     RECT  116.61 259.815 133.15 262.51 ;
     RECT  142.37 261.65 268.67 262.51 ;
     RECT  30.93 262.51 34.59 264.345 ;
     RECT  55.57 262.51 70.43 264.345 ;
     RECT  93.65 262.51 97.31 264.345 ;
     RECT  98.69 262.51 102.35 264.345 ;
     RECT  121.09 262.51 124.75 264.345 ;
     RECT  142.37 262.51 161.71 264.345 ;
     RECT  161.97 262.51 268.67 264.345 ;
     RECT  59.23 264.345 68.155 264.375 ;
     RECT  174.03 264.345 182.955 264.375 ;
     RECT  185.23 264.345 194.155 264.375 ;
     RECT  196.43 264.345 205.355 264.375 ;
     RECT  207.63 264.345 216.555 264.375 ;
     RECT  218.83 264.345 227.755 264.375 ;
     RECT  230.03 264.345 238.955 264.375 ;
     RECT  241.23 264.345 250.155 264.375 ;
     RECT  257.47 264.345 266.395 264.375 ;
    LAYER Nwell ;
     RECT  81.89 12.345 88.35 14.69 ;
     RECT  74.05 14.69 94.51 17.895 ;
     RECT  118.85 14.69 128.67 17.895 ;
     RECT  132.85 14.69 142.11 17.895 ;
     RECT  160.85 14.69 177.39 17.895 ;
     RECT  76.29 22.425 104.03 24.77 ;
     RECT  110.45 22.425 167.87 24.77 ;
     RECT  110.45 24.77 176.83 25.63 ;
     RECT  58.37 24.77 63.71 27.975 ;
     RECT  74.05 24.77 110.19 27.975 ;
     RECT  113.81 25.63 138.75 27.975 ;
     RECT  139.57 25.63 151.63 27.975 ;
     RECT  151.89 25.63 159.47 27.975 ;
     RECT  160.29 25.63 176.83 27.975 ;
     RECT  55.01 32.505 71.55 34.85 ;
     RECT  86.37 32.505 92.83 34.85 ;
     RECT  95.89 32.505 104.59 34.85 ;
     RECT  104.85 32.505 114.67 34.85 ;
     RECT  118.85 32.505 147.71 34.85 ;
     RECT  155.25 32.505 180.19 34.85 ;
     RECT  207.89 32.505 224.43 34.85 ;
     RECT  55.01 34.85 118.03 35.71 ;
     RECT  118.85 34.85 193.63 35.71 ;
     RECT  58.93 35.71 118.03 38.055 ;
     RECT  129.49 35.71 159.47 38.055 ;
     RECT  164.77 35.71 193.63 38.055 ;
     RECT  200.61 34.85 224.43 38.055 ;
     RECT  48.85 42.585 63.15 44.93 ;
     RECT  90.29 42.585 105.71 44.93 ;
     RECT  106.53 42.585 143.79 44.93 ;
     RECT  154.69 42.585 171.23 44.93 ;
     RECT  188.29 42.585 232.83 44.93 ;
     RECT  88.05 44.93 143.79 45.79 ;
     RECT  154.13 44.93 171.23 45.79 ;
     RECT  179.89 44.93 232.83 45.79 ;
     RECT  34.29 44.93 39.63 48.135 ;
     RECT  40.45 44.93 44.11 48.135 ;
     RECT  44.93 44.93 64.83 48.135 ;
     RECT  65.09 44.93 81.63 48.135 ;
     RECT  88.05 45.79 120.83 48.135 ;
     RECT  130.61 45.79 135.95 48.135 ;
     RECT  154.13 45.79 170.67 48.135 ;
     RECT  171.49 44.93 177.95 48.135 ;
     RECT  179.89 45.79 196.43 48.135 ;
     RECT  201.73 45.79 212.67 48.135 ;
     RECT  212.93 45.79 229.47 48.135 ;
     RECT  25.89 52.665 46.35 55.01 ;
     RECT  47.17 52.665 81.63 55.01 ;
     RECT  91.41 52.665 115.23 55.01 ;
     RECT  137.33 52.665 153.87 55.01 ;
     RECT  155.25 52.665 198.67 55.01 ;
     RECT  199.49 52.665 203.15 55.01 ;
     RECT  205.65 52.665 224.99 55.01 ;
     RECT  91.41 55.01 127.55 55.87 ;
     RECT  137.33 55.01 224.99 55.87 ;
     RECT  25.89 55.01 82.75 58.215 ;
     RECT  94.21 55.87 127.55 58.215 ;
     RECT  139.57 55.87 159.47 58.215 ;
     RECT  159.73 55.87 165.07 58.215 ;
     RECT  167.57 55.87 170.67 58.215 ;
     RECT  171.49 55.87 190.27 58.215 ;
     RECT  190.53 55.87 210.43 58.215 ;
     RECT  214.05 55.87 218.83 58.215 ;
     RECT  219.09 55.87 222.75 58.215 ;
     RECT  229.73 55.01 233.39 58.215 ;
     RECT  32.61 62.745 40.75 65.09 ;
     RECT  41.57 62.745 86.11 65.09 ;
     RECT  105.41 62.745 112.99 65.09 ;
     RECT  132.85 62.745 191.39 65.09 ;
     RECT  191.65 62.745 236.19 65.09 ;
     RECT  237.57 62.745 244.03 65.09 ;
     RECT  248.21 62.745 264.75 65.09 ;
     RECT  32.61 65.09 86.67 65.95 ;
     RECT  129.49 65.09 264.75 65.95 ;
     RECT  37.65 65.95 45.23 68.295 ;
     RECT  45.49 65.95 86.67 68.295 ;
     RECT  91.41 65.09 126.99 68.295 ;
     RECT  129.49 65.95 137.07 68.295 ;
     RECT  148.53 65.95 156.67 68.295 ;
     RECT  169.81 65.95 185.23 68.295 ;
     RECT  186.05 65.95 213.23 68.295 ;
     RECT  216.85 65.95 263.07 68.295 ;
     RECT  48.29 72.825 80.51 75.17 ;
     RECT  101.49 72.825 137.63 75.17 ;
     RECT  142.37 72.825 147.15 75.17 ;
     RECT  169.25 72.825 178.51 75.17 ;
     RECT  178.77 72.825 182.43 75.17 ;
     RECT  189.41 72.825 209.87 75.17 ;
     RECT  211.25 72.825 217.15 75.17 ;
     RECT  223.01 72.825 267.55 75.17 ;
     RECT  29.81 72.825 46.35 76.03 ;
     RECT  48.29 75.17 96.19 76.03 ;
     RECT  99.25 75.17 154.43 76.03 ;
     RECT  169.25 75.17 182.43 76.03 ;
     RECT  189.41 75.17 210.99 76.03 ;
     RECT  211.25 75.17 219.39 76.03 ;
     RECT  52.21 76.03 56.43 78.375 ;
     RECT  56.69 76.03 73.23 78.375 ;
     RECT  76.29 76.03 96.19 78.375 ;
     RECT  99.25 76.03 115.79 78.375 ;
     RECT  116.61 76.03 144.35 78.375 ;
     RECT  145.17 76.03 154.43 78.375 ;
     RECT  169.25 76.03 179.63 78.375 ;
     RECT  197.25 76.03 200.91 78.375 ;
     RECT  203.41 76.03 210.99 78.375 ;
     RECT  211.81 76.03 219.39 78.375 ;
     RECT  221.33 75.17 268.11 78.375 ;
     RECT  80.21 82.905 88.35 85.25 ;
     RECT  90.29 82.905 142.67 85.25 ;
     RECT  145.17 82.905 161.71 85.25 ;
     RECT  164.21 82.905 182.99 85.25 ;
     RECT  187.17 82.905 196.43 85.25 ;
     RECT  209.01 82.905 213.79 85.25 ;
     RECT  232.53 82.905 242.91 85.25 ;
     RECT  243.73 82.905 251.87 85.25 ;
     RECT  34.85 82.905 51.39 86.11 ;
     RECT  52.77 82.905 74.91 86.11 ;
     RECT  80.21 85.25 161.71 86.11 ;
     RECT  207.33 85.25 213.79 86.11 ;
     RECT  230.29 85.25 251.87 86.11 ;
     RECT  86.93 86.11 131.47 88.455 ;
     RECT  132.29 86.11 157.23 88.455 ;
     RECT  164.21 85.25 185.79 88.455 ;
     RECT  187.17 85.25 203.71 88.455 ;
     RECT  207.33 86.11 212.67 88.455 ;
     RECT  214.61 85.25 219.95 88.455 ;
     RECT  230.29 86.11 233.39 88.455 ;
     RECT  235.89 86.11 244.03 88.455 ;
     RECT  252.13 85.25 260.27 88.455 ;
     RECT  62.85 92.985 70.99 95.33 ;
     RECT  83.57 92.985 100.11 95.33 ;
     RECT  102.61 92.985 118.59 95.33 ;
     RECT  121.65 92.985 138.19 95.33 ;
     RECT  141.25 92.985 157.79 95.33 ;
     RECT  161.41 92.985 174.59 95.33 ;
     RECT  174.85 92.985 190.27 95.33 ;
     RECT  207.89 92.985 264.19 95.33 ;
     RECT  83.57 95.33 190.27 96.19 ;
     RECT  194.45 95.33 264.19 96.19 ;
     RECT  43.81 95.33 47.47 98.535 ;
     RECT  59.49 95.33 76.03 98.535 ;
     RECT  86.37 96.19 110.19 98.535 ;
     RECT  116.05 96.19 154.43 98.535 ;
     RECT  154.69 96.19 190.27 98.535 ;
     RECT  194.45 96.19 215.47 98.535 ;
     RECT  217.97 96.19 255.79 98.535 ;
     RECT  40.45 103.065 50.27 105.41 ;
     RECT  50.53 103.065 56.99 105.41 ;
     RECT  59.49 103.065 76.03 105.41 ;
     RECT  86.37 103.065 109.07 105.41 ;
     RECT  128.37 103.065 135.95 105.41 ;
     RECT  137.89 103.065 150.51 105.41 ;
     RECT  154.69 103.065 170.67 105.41 ;
     RECT  173.73 103.065 188.03 105.41 ;
     RECT  188.85 103.065 213.79 105.41 ;
     RECT  214.61 103.065 231.15 105.41 ;
     RECT  231.97 103.065 247.39 105.41 ;
     RECT  247.65 103.065 264.19 105.41 ;
     RECT  34.85 105.41 111.87 106.27 ;
     RECT  113.25 105.41 135.95 106.27 ;
     RECT  137.33 105.41 264.19 106.27 ;
     RECT  34.85 106.27 51.39 108.615 ;
     RECT  52.77 106.27 91.15 108.615 ;
     RECT  96.45 106.27 111.87 108.615 ;
     RECT  113.25 106.27 129.79 108.615 ;
     RECT  137.33 106.27 145.47 108.615 ;
     RECT  145.73 106.27 166.19 108.615 ;
     RECT  167.01 106.27 183.55 108.615 ;
     RECT  183.81 106.27 194.19 108.615 ;
     RECT  194.45 106.27 200.35 108.615 ;
     RECT  202.85 106.27 210.43 108.615 ;
     RECT  213.49 106.27 222.75 108.615 ;
     RECT  223.01 106.27 239.55 108.615 ;
     RECT  244.85 106.27 260.27 108.615 ;
     RECT  36.53 113.145 73.23 115.49 ;
     RECT  89.17 113.145 105.71 115.49 ;
     RECT  105.97 113.145 145.47 115.49 ;
     RECT  170.93 113.145 186.91 115.49 ;
     RECT  193.89 113.145 203.15 115.49 ;
     RECT  36.53 115.49 145.47 116.35 ;
     RECT  145.73 113.145 162.27 116.35 ;
     RECT  169.25 115.49 203.15 116.35 ;
     RECT  207.89 113.145 266.43 116.35 ;
     RECT  38.21 116.35 65.95 118.695 ;
     RECT  66.77 116.35 106.83 118.695 ;
     RECT  113.81 116.35 135.95 118.695 ;
     RECT  152.45 116.35 156.11 118.695 ;
     RECT  169.25 116.35 198.67 118.695 ;
     RECT  210.13 116.35 217.71 118.695 ;
     RECT  225.81 116.35 249.07 118.695 ;
     RECT  252.13 116.35 260.27 118.695 ;
     RECT  13.57 123.225 30.11 125.57 ;
     RECT  56.13 123.225 77.15 125.57 ;
     RECT  84.69 123.225 101.23 125.57 ;
     RECT  103.73 123.225 119.15 125.57 ;
     RECT  125.57 123.225 128.67 125.57 ;
     RECT  141.25 123.225 148.83 125.57 ;
     RECT  158.61 123.225 165.07 125.57 ;
     RECT  165.33 123.225 181.87 125.57 ;
     RECT  182.69 123.225 199.23 125.57 ;
     RECT  200.05 123.225 209.87 125.57 ;
     RECT  13.57 125.57 34.03 126.43 ;
     RECT  36.53 123.225 53.07 126.43 ;
     RECT  84.69 125.57 139.87 126.43 ;
     RECT  140.13 125.57 148.83 126.43 ;
     RECT  154.13 125.57 165.07 126.43 ;
     RECT  165.33 125.57 216.03 126.43 ;
     RECT  233.65 123.225 264.19 126.43 ;
     RECT  14.69 126.43 34.03 128.775 ;
     RECT  37.65 126.43 51.39 128.775 ;
     RECT  53.89 125.57 82.75 128.775 ;
     RECT  87.49 126.43 104.03 128.775 ;
     RECT  107.65 126.43 139.87 128.775 ;
     RECT  140.13 126.43 147.71 128.775 ;
     RECT  154.13 126.43 161.71 128.775 ;
     RECT  165.33 126.43 194.19 128.775 ;
     RECT  198.37 126.43 216.03 128.775 ;
     RECT  236.45 126.43 260.27 128.775 ;
     RECT  46.61 133.305 73.79 135.65 ;
     RECT  74.05 133.305 90.59 135.65 ;
     RECT  91.41 133.305 99.55 135.65 ;
     RECT  106.53 133.305 165.63 135.65 ;
     RECT  180.45 133.305 185.79 135.65 ;
     RECT  192.21 133.305 198.67 135.65 ;
     RECT  201.17 133.305 214.35 135.65 ;
     RECT  16.37 133.305 28.99 136.51 ;
     RECT  45.49 135.65 73.79 136.51 ;
     RECT  74.05 135.65 101.23 136.51 ;
     RECT  106.53 135.65 170.67 136.51 ;
     RECT  174.29 135.65 221.63 136.51 ;
     RECT  231.97 133.305 264.19 136.51 ;
     RECT  19.73 136.51 27.31 138.855 ;
     RECT  45.49 136.51 70.43 138.855 ;
     RECT  76.85 136.51 101.23 138.855 ;
     RECT  116.61 136.51 145.47 138.855 ;
     RECT  147.41 136.51 170.67 138.855 ;
     RECT  174.29 136.51 193.07 138.855 ;
     RECT  194.45 136.51 202.03 138.855 ;
     RECT  202.29 136.51 221.63 138.855 ;
     RECT  235.33 136.51 250.75 138.855 ;
     RECT  15.25 143.385 34.59 145.73 ;
     RECT  56.13 143.385 73.79 145.73 ;
     RECT  89.17 143.385 105.71 145.73 ;
     RECT  109.89 143.385 126.43 145.73 ;
     RECT  192.77 143.385 202.59 145.73 ;
     RECT  252.13 143.385 260.27 145.73 ;
     RECT  89.17 145.73 106.83 146.59 ;
     RECT  109.89 145.73 127.55 146.59 ;
     RECT  131.73 143.385 170.11 146.59 ;
     RECT  191.65 145.73 202.59 146.59 ;
     RECT  206.77 143.385 227.79 146.59 ;
     RECT  229.17 143.385 245.71 146.59 ;
     RECT  13.01 145.73 36.83 148.935 ;
     RECT  56.13 145.73 76.03 148.935 ;
     RECT  90.29 146.59 106.83 148.935 ;
     RECT  112.13 146.59 127.55 148.935 ;
     RECT  132.29 146.59 148.83 148.935 ;
     RECT  149.09 146.59 155.55 148.935 ;
     RECT  177.65 145.73 181.31 148.935 ;
     RECT  182.13 145.73 185.79 148.935 ;
     RECT  191.65 146.59 196.43 148.935 ;
     RECT  213.49 146.59 221.07 148.935 ;
     RECT  245.97 145.73 262.51 148.935 ;
     RECT  10.21 153.465 36.27 155.81 ;
     RECT  60.05 153.465 76.59 155.81 ;
     RECT  82.45 153.465 98.99 155.81 ;
     RECT  107.65 153.465 114.67 155.81 ;
     RECT  115.49 153.465 134.27 155.81 ;
     RECT  145.17 153.465 167.87 155.81 ;
     RECT  208.45 153.465 219.39 155.81 ;
     RECT  246.53 153.465 263.07 155.81 ;
     RECT  10.21 155.81 41.87 156.67 ;
     RECT  52.21 155.81 76.59 156.67 ;
     RECT  77.41 155.81 98.99 156.67 ;
     RECT  99.25 155.81 134.27 156.67 ;
     RECT  145.17 155.81 171.79 156.67 ;
     RECT  174.85 153.465 197.55 156.67 ;
     RECT  240.37 155.81 268.67 158.985 ;
     RECT  13.01 156.67 41.87 159.015 ;
     RECT  52.21 156.67 76.03 159.015 ;
     RECT  77.41 156.67 93.95 159.015 ;
     RECT  99.25 156.67 128.11 159.015 ;
     RECT  145.73 156.67 162.27 159.015 ;
     RECT  166.45 156.67 171.79 159.015 ;
     RECT  201.17 155.81 207.07 159.015 ;
     RECT  207.89 155.81 222.19 159.015 ;
     RECT  224.13 155.81 234.51 159.015 ;
     RECT  240.37 158.985 257.47 159.015 ;
     RECT  266.395 158.985 268.67 159.015 ;
     RECT  19.17 163.545 44.67 165.89 ;
     RECT  51.09 163.545 91.15 165.89 ;
     RECT  107.65 163.545 139.31 165.89 ;
     RECT  148.53 163.545 156.67 165.89 ;
     RECT  161.97 163.545 210.99 165.89 ;
     RECT  213.49 163.545 218.27 165.89 ;
     RECT  218.53 163.545 262.51 165.89 ;
     RECT  19.17 165.89 101.79 166.75 ;
     RECT  104.29 165.89 139.31 166.75 ;
     RECT  148.53 165.89 268.67 166.75 ;
     RECT  242.05 166.75 268.67 169.065 ;
     RECT  21.41 166.75 76.59 169.095 ;
     RECT  85.25 166.75 101.79 169.095 ;
     RECT  104.29 166.75 107.95 169.095 ;
     RECT  108.77 166.75 137.07 169.095 ;
     RECT  155.81 166.75 163.95 169.095 ;
     RECT  174.85 166.75 194.19 169.095 ;
     RECT  194.45 166.75 202.03 169.095 ;
     RECT  204.53 166.75 225.55 169.095 ;
     RECT  226.93 166.75 237.87 169.095 ;
     RECT  242.05 169.065 257.47 169.095 ;
     RECT  266.395 169.065 268.67 169.095 ;
     RECT  245.41 173.625 246.27 173.655 ;
     RECT  255.195 173.625 257.47 173.655 ;
     RECT  266.395 173.625 268.67 173.655 ;
     RECT  19.73 173.625 27.31 175.97 ;
     RECT  52.77 173.625 72.67 175.97 ;
     RECT  81.33 173.625 103.47 175.97 ;
     RECT  104.29 173.625 133.15 175.97 ;
     RECT  151.89 173.625 157.23 175.97 ;
     RECT  170.37 173.625 190.83 175.97 ;
     RECT  209.57 173.625 215.47 175.97 ;
     RECT  219.65 173.625 223.31 175.97 ;
     RECT  223.57 173.625 240.11 175.97 ;
     RECT  245.41 173.655 268.67 175.97 ;
     RECT  52.77 175.97 135.95 176.83 ;
     RECT  168.13 175.97 190.83 176.83 ;
     RECT  205.09 175.97 215.47 176.83 ;
     RECT  219.65 175.97 268.67 176.83 ;
     RECT  53.89 176.83 101.79 179.145 ;
     RECT  102.05 176.83 135.95 179.145 ;
     RECT  17.49 175.97 37.39 179.175 ;
     RECT  53.89 179.145 62.03 179.175 ;
     RECT  70.955 179.145 101.79 179.175 ;
     RECT  102.05 179.145 102.91 179.175 ;
     RECT  111.835 179.145 135.95 179.175 ;
     RECT  145.73 175.97 166.19 179.175 ;
     RECT  168.13 176.83 173.47 179.175 ;
     RECT  177.09 176.83 188.03 179.175 ;
     RECT  205.09 176.83 210.43 179.175 ;
     RECT  219.65 176.83 264.19 179.175 ;
     RECT  73.49 183.705 74.35 183.735 ;
     RECT  83.275 183.705 85.55 183.735 ;
     RECT  86.93 183.705 87.79 183.735 ;
     RECT  96.715 183.705 114.67 183.735 ;
     RECT  123.595 183.705 149.95 183.735 ;
     RECT  228.61 183.705 236.75 183.735 ;
     RECT  245.675 183.705 263.63 183.735 ;
     RECT  13.57 183.705 36.83 186.05 ;
     RECT  42.69 183.705 73.23 186.05 ;
     RECT  73.49 183.735 85.55 186.05 ;
     RECT  86.93 183.735 149.95 186.05 ;
     RECT  150.21 183.705 177.39 186.05 ;
     RECT  181.57 183.705 186.35 186.05 ;
     RECT  191.65 183.705 195.31 186.05 ;
     RECT  196.13 183.705 216.03 186.05 ;
     RECT  219.65 183.705 228.35 186.05 ;
     RECT  228.61 183.735 263.63 186.05 ;
     RECT  13.57 186.05 39.07 186.91 ;
     RECT  86.37 186.05 228.35 186.91 ;
     RECT  228.61 186.05 264.19 186.91 ;
     RECT  156.37 186.91 182.99 189.225 ;
     RECT  19.17 186.91 39.07 189.255 ;
     RECT  40.45 186.05 86.11 189.255 ;
     RECT  86.37 186.91 106.27 189.255 ;
     RECT  107.09 186.91 135.95 189.255 ;
     RECT  138.45 186.91 143.79 189.255 ;
     RECT  148.53 186.91 153.31 189.255 ;
     RECT  156.37 189.225 161.71 189.255 ;
     RECT  170.635 189.225 182.99 189.255 ;
     RECT  185.49 186.91 222.19 189.255 ;
     RECT  231.97 186.91 264.19 189.255 ;
     RECT  20.29 193.785 95.63 193.815 ;
     RECT  104.555 193.785 128.11 193.815 ;
     RECT  144.61 193.785 186.91 193.815 ;
     RECT  195.835 193.785 217.15 193.815 ;
     RECT  222.45 193.785 248.51 193.815 ;
     RECT  257.435 193.785 266.99 193.815 ;
     RECT  20.29 193.815 128.11 196.13 ;
     RECT  144.61 193.815 217.15 196.13 ;
     RECT  222.45 193.815 266.99 196.13 ;
     RECT  18.05 196.13 268.67 196.99 ;
     RECT  55.57 196.99 70.43 199.305 ;
     RECT  79.65 196.99 147.15 199.305 ;
     RECT  205.65 196.99 268.67 199.305 ;
     RECT  18.05 196.99 34.59 199.335 ;
     RECT  35.97 196.99 42.99 199.335 ;
     RECT  44.37 196.99 49.15 199.335 ;
     RECT  55.57 199.305 56.43 199.335 ;
     RECT  65.355 199.305 70.43 199.335 ;
     RECT  71.81 196.99 74.91 199.335 ;
     RECT  79.65 199.305 84.99 199.335 ;
     RECT  93.915 199.305 112.43 199.335 ;
     RECT  121.355 199.305 147.15 199.335 ;
     RECT  156.37 196.99 189.71 199.335 ;
     RECT  193.89 196.99 198.67 199.335 ;
     RECT  199.49 196.99 204.83 199.335 ;
     RECT  205.65 199.305 257.47 199.335 ;
     RECT  266.395 199.305 268.67 199.335 ;
     RECT  63.41 203.865 64.27 203.895 ;
     RECT  73.195 203.865 79.95 203.895 ;
     RECT  82.45 203.865 83.31 203.895 ;
     RECT  92.235 203.865 94.51 203.895 ;
     RECT  103.435 203.865 107.95 203.895 ;
     RECT  116.875 203.865 147.15 203.895 ;
     RECT  154.13 203.865 171.79 203.895 ;
     RECT  180.715 203.865 195.87 203.895 ;
     RECT  209.01 203.865 236.75 203.895 ;
     RECT  245.675 203.865 263.63 203.895 ;
     RECT  39.89 203.865 44.11 206.21 ;
     RECT  63.41 203.895 79.95 206.21 ;
     RECT  82.45 203.895 147.15 206.21 ;
     RECT  154.13 203.895 195.87 206.21 ;
     RECT  196.13 203.865 202.03 206.21 ;
     RECT  203.41 203.865 208.19 206.21 ;
     RECT  209.01 203.895 263.63 206.21 ;
     RECT  14.13 203.865 30.67 207.07 ;
     RECT  53.33 203.865 57.55 207.07 ;
     RECT  61.17 206.21 82.19 207.07 ;
     RECT  82.45 206.21 147.71 207.07 ;
     RECT  154.13 206.21 264.19 207.07 ;
     RECT  88.05 207.07 147.71 209.385 ;
     RECT  187.73 207.07 264.19 209.385 ;
     RECT  31.49 206.21 45.79 209.415 ;
     RECT  61.17 207.07 65.39 209.415 ;
     RECT  65.65 207.07 82.19 209.415 ;
     RECT  88.05 209.385 104.59 209.415 ;
     RECT  113.515 209.385 118.59 209.415 ;
     RECT  127.515 209.385 147.71 209.415 ;
     RECT  154.13 207.07 186.35 209.415 ;
     RECT  187.73 209.385 226.11 209.415 ;
     RECT  235.035 209.385 237.31 209.415 ;
     RECT  246.235 209.385 264.19 209.415 ;
     RECT  80.77 213.945 86.11 213.975 ;
     RECT  95.035 213.945 112.99 213.975 ;
     RECT  121.915 213.945 146.59 213.975 ;
     RECT  230.85 213.945 231.71 213.975 ;
     RECT  240.635 213.945 265.87 213.975 ;
     RECT  13.57 213.945 30.11 216.29 ;
     RECT  30.37 213.945 63.15 216.29 ;
     RECT  63.41 213.945 79.95 216.29 ;
     RECT  80.77 213.975 146.59 216.29 ;
     RECT  146.85 213.945 186.35 216.29 ;
     RECT  187.73 213.945 228.35 216.29 ;
     RECT  230.85 213.975 265.87 216.29 ;
     RECT  13.57 216.29 266.99 217.15 ;
     RECT  40.45 217.15 193.63 219.465 ;
     RECT  212.37 217.15 266.99 219.465 ;
     RECT  22.53 217.15 39.07 219.495 ;
     RECT  40.45 219.465 115.23 219.495 ;
     RECT  124.155 219.465 138.75 219.495 ;
     RECT  147.675 219.465 193.63 219.495 ;
     RECT  195.01 217.15 211.55 219.495 ;
     RECT  212.37 219.465 213.23 219.495 ;
     RECT  222.155 219.465 255.79 219.495 ;
     RECT  264.715 219.465 266.99 219.495 ;
     RECT  28.13 224.025 56.99 224.055 ;
     RECT  65.915 224.025 84.99 224.055 ;
     RECT  111.01 224.025 147.71 224.055 ;
     RECT  156.635 224.025 174.59 224.055 ;
     RECT  177.09 224.025 207.63 224.055 ;
     RECT  216.555 224.025 254.11 224.055 ;
     RECT  256.05 224.025 256.91 224.055 ;
     RECT  265.835 224.025 268.11 224.055 ;
     RECT  89.73 224.025 107.39 226.37 ;
     RECT  111.01 224.055 174.59 226.37 ;
     RECT  177.09 224.055 254.11 226.37 ;
     RECT  256.05 224.055 268.11 226.37 ;
     RECT  28.13 224.055 84.99 227.23 ;
     RECT  85.25 226.37 174.59 227.23 ;
     RECT  176.53 226.37 268.11 227.23 ;
     RECT  53.33 227.23 81.63 229.545 ;
     RECT  85.25 227.23 129.79 229.545 ;
     RECT  130.61 227.23 163.39 229.545 ;
     RECT  227.49 227.23 265.87 229.545 ;
     RECT  20.85 226.37 23.95 229.575 ;
     RECT  28.13 227.23 52.51 229.575 ;
     RECT  53.33 229.545 60.91 229.575 ;
     RECT  69.835 229.545 81.63 229.575 ;
     RECT  85.25 229.545 91.15 229.575 ;
     RECT  100.075 229.545 129.79 229.575 ;
     RECT  130.61 229.545 147.15 229.575 ;
     RECT  156.075 229.545 163.39 229.575 ;
     RECT  167.01 227.23 172.91 229.575 ;
     RECT  176.53 227.23 180.19 229.575 ;
     RECT  185.49 227.23 226.11 229.575 ;
     RECT  227.49 229.545 247.39 229.575 ;
     RECT  256.315 229.545 265.87 229.575 ;
     RECT  81.33 234.105 87.79 234.135 ;
     RECT  96.715 234.105 98.99 234.135 ;
     RECT  46.61 234.105 81.07 236.45 ;
     RECT  81.33 234.135 98.99 236.45 ;
     RECT  99.25 234.105 110.75 236.45 ;
     RECT  119.41 234.105 145.47 236.45 ;
     RECT  158.61 234.105 267.55 236.45 ;
     RECT  13.57 234.105 39.63 237.31 ;
     RECT  46.61 236.45 110.75 237.31 ;
     RECT  111.57 234.105 114.67 237.31 ;
     RECT  119.41 236.45 149.95 237.31 ;
     RECT  156.93 236.45 268.67 237.31 ;
     RECT  168.13 237.31 233.95 239.625 ;
     RECT  234.21 237.31 268.67 239.625 ;
     RECT  21.41 237.31 24.51 239.655 ;
     RECT  31.49 237.31 37.39 239.655 ;
     RECT  51.09 237.31 87.23 239.655 ;
     RECT  87.49 237.31 109.07 239.655 ;
     RECT  121.65 237.31 129.79 239.655 ;
     RECT  130.61 237.31 135.95 239.655 ;
     RECT  136.77 237.31 139.87 239.655 ;
     RECT  144.61 237.31 149.95 239.655 ;
     RECT  156.93 237.31 160.59 239.655 ;
     RECT  168.13 239.625 202.59 239.655 ;
     RECT  211.515 239.625 233.95 239.655 ;
     RECT  234.21 239.625 235.07 239.655 ;
     RECT  243.995 239.625 246.27 239.655 ;
     RECT  255.195 239.625 257.47 239.655 ;
     RECT  266.395 239.625 268.67 239.655 ;
     RECT  182.69 244.185 235.07 244.215 ;
     RECT  243.995 244.185 246.27 244.215 ;
     RECT  255.195 244.185 257.47 244.215 ;
     RECT  266.395 244.185 268.67 244.215 ;
     RECT  13.57 244.185 44.67 246.53 ;
     RECT  51.65 244.185 68.75 246.53 ;
     RECT  69.57 244.185 86.11 246.53 ;
     RECT  89.17 244.185 133.15 246.53 ;
     RECT  133.41 244.185 138.75 246.53 ;
     RECT  141.25 244.185 165.07 246.53 ;
     RECT  165.33 244.185 181.87 246.53 ;
     RECT  182.69 244.215 268.67 246.53 ;
     RECT  13.57 246.53 46.91 247.39 ;
     RECT  50.53 246.53 86.67 247.39 ;
     RECT  89.17 246.53 268.67 247.39 ;
     RECT  202.29 247.39 267.55 249.705 ;
     RECT  16.93 247.39 46.91 249.735 ;
     RECT  50.53 247.39 73.79 249.735 ;
     RECT  74.05 247.39 79.39 249.735 ;
     RECT  83.01 247.39 86.67 249.735 ;
     RECT  91.97 247.39 148.27 249.735 ;
     RECT  156.93 247.39 201.47 249.735 ;
     RECT  202.29 249.705 233.39 249.735 ;
     RECT  242.315 249.705 267.55 249.735 ;
     RECT  80.77 254.265 97.31 256.61 ;
     RECT  98.69 254.265 123.63 256.61 ;
     RECT  123.89 254.265 140.43 256.61 ;
     RECT  140.69 254.265 147.15 256.61 ;
     RECT  149.09 254.265 267.55 256.61 ;
     RECT  11.33 254.265 46.35 257.47 ;
     RECT  47.73 254.265 79.95 257.47 ;
     RECT  80.77 256.61 140.43 257.47 ;
     RECT  140.69 256.61 267.55 257.47 ;
     RECT  144.61 257.47 266.99 259.785 ;
     RECT  24.21 257.47 40.75 259.815 ;
     RECT  49.41 257.47 65.95 259.815 ;
     RECT  66.21 257.47 69.87 259.815 ;
     RECT  71.25 257.47 77.71 259.815 ;
     RECT  86.37 257.47 107.39 259.815 ;
     RECT  116.61 257.47 133.15 259.815 ;
     RECT  144.61 259.785 180.75 259.815 ;
     RECT  189.675 259.785 191.95 259.815 ;
     RECT  200.875 259.785 203.15 259.815 ;
     RECT  212.075 259.785 235.63 259.815 ;
     RECT  244.555 259.785 266.99 259.815 ;
     RECT  55.57 264.345 59.23 264.375 ;
     RECT  68.155 264.345 70.43 264.375 ;
     RECT  161.97 264.345 174.03 264.375 ;
     RECT  182.955 264.345 185.23 264.375 ;
     RECT  194.155 264.345 196.43 264.375 ;
     RECT  205.355 264.345 207.63 264.375 ;
     RECT  216.555 264.345 218.83 264.375 ;
     RECT  227.755 264.345 230.03 264.375 ;
     RECT  238.955 264.345 241.23 264.375 ;
     RECT  250.155 264.345 257.47 264.375 ;
     RECT  266.395 264.345 268.67 264.375 ;
     RECT  30.93 264.345 34.59 267.55 ;
     RECT  55.57 264.375 70.43 267.55 ;
     RECT  93.65 264.345 97.31 267.55 ;
     RECT  98.69 264.345 102.35 267.55 ;
     RECT  121.09 264.345 124.75 267.55 ;
     RECT  142.37 264.345 161.71 267.55 ;
     RECT  161.97 264.375 268.67 267.55 ;
    LAYER Metal1 ;
     RECT  10.08 9.78 31.36 267.42 ;
     RECT  31.36 9.78 34.16 267.57 ;
     RECT  34.16 9.78 56 267.42 ;
     RECT  56 9.78 70 267.57 ;
     RECT  70 9.78 82.32 267.42 ;
     RECT  82.32 9.63 87.92 267.42 ;
     RECT  87.92 9.78 94.08 267.42 ;
     RECT  94.08 9.78 101.92 267.57 ;
     RECT  101.92 9.78 121.52 267.42 ;
     RECT  121.52 9.78 124.32 267.57 ;
     RECT  124.32 9.78 142.8 267.42 ;
     RECT  142.8 9.78 268.24 267.57 ;
    LAYER Metal2 ;
     RECT  71.42 9.89 72.74 12.41 ;
     RECT  71.42 12.41 83.3 13.95 ;
     RECT  71.42 13.95 83.86 16.75 ;
     RECT  96.42 14.93 97.74 16.75 ;
     RECT  121.42 9.89 122.74 17.31 ;
     RECT  119.98 17.31 122.74 17.45 ;
     RECT  133.98 17.31 134.26 17.45 ;
     RECT  146.42 14.93 147.74 17.45 ;
     RECT  171.42 9.89 172.74 17.45 ;
     RECT  119.98 17.45 147.74 18.57 ;
     RECT  115.5 18.57 147.74 20.3 ;
     RECT  115.5 20.3 150.5 21.23 ;
     RECT  161.98 17.45 176.26 21.23 ;
     RECT  71.42 16.75 97.74 22.49 ;
     RECT  115.5 21.23 176.26 22.49 ;
     RECT  71.42 22.49 98.98 22.54 ;
     RECT  71.42 22.54 99.54 23.61 ;
     RECT  111.58 22.49 176.26 23.61 ;
     RECT  71.42 23.61 176.26 25.34 ;
     RECT  71.42 25.34 177.94 26.41 ;
     RECT  62.3 26.41 177.94 26.46 ;
     RECT  60.62 26.46 177.94 27.53 ;
     RECT  59.5 27.53 177.94 32.01 ;
     RECT  221.42 9.89 222.74 32.01 ;
     RECT  46.42 14.93 47.74 32.57 ;
     RECT  59.5 32.01 178.5 32.57 ;
     RECT  212.94 32.01 222.74 32.57 ;
     RECT  46.42 32.57 178.5 33.13 ;
     RECT  209.02 32.57 222.74 33.69 ;
     RECT  209.02 33.69 223.3 33.74 ;
     RECT  196.42 14.93 197.74 37.61 ;
     RECT  209.02 33.74 224.42 37.61 ;
     RECT  46.42 33.13 179.06 38.17 ;
     RECT  46.42 38.17 183.54 41.39 ;
     RECT  196.42 37.61 228.34 41.39 ;
     RECT  46.42 41.39 228.34 47.13 ;
     RECT  46.06 47.13 228.34 47.55 ;
     RECT  21.42 9.89 22.74 47.69 ;
     RECT  42.7 47.55 228.34 47.69 ;
     RECT  21.42 47.69 228.34 53.11 ;
     RECT  95.9 53.11 228.34 57.63 ;
     RECT  95.9 57.63 231.14 57.77 ;
     RECT  95.9 57.77 232.26 58.89 ;
     RECT  246.42 14.93 247.74 58.89 ;
     RECT  95.9 58.89 247.74 62.25 ;
     RECT  95.9 62.25 253.54 62.3 ;
     RECT  95.9 62.3 255.22 63.93 ;
     RECT  21.42 53.11 84.42 67.71 ;
     RECT  95.9 63.93 263.62 67.71 ;
     RECT  21.42 67.71 263.62 68.41 ;
     RECT  21.42 68.41 267.54 73.27 ;
     RECT  35.98 73.27 267.54 82.79 ;
     RECT  35.98 82.79 72.74 83.35 ;
     RECT  85.26 82.79 267.54 93.43 ;
     RECT  46.42 83.35 72.74 96.83 ;
     RECT  46.42 96.83 74.9 97.53 ;
     RECT  46.06 97.53 74.9 97.58 ;
     RECT  44.38 97.58 74.9 100.66 ;
     RECT  21.42 73.27 22.74 100.89 ;
     RECT  21.42 100.89 31.78 102.57 ;
     RECT  43.26 100.66 74.9 102.57 ;
     RECT  21.42 102.57 74.9 106.49 ;
     RECT  86.94 93.43 267.54 106.49 ;
     RECT  21.42 106.49 267.54 122.73 ;
     RECT  18.62 122.73 267.54 122.78 ;
     RECT  18.06 122.78 267.54 123.29 ;
     RECT  15.26 123.29 267.54 126.09 ;
     RECT  15.26 126.09 268.1 128.66 ;
     RECT  16.38 128.66 268.1 129.27 ;
     RECT  17.5 129.27 268.1 143.45 ;
     RECT  16.94 143.45 268.1 147.79 ;
     RECT  14.7 147.79 268.1 149.05 ;
     RECT  11.34 149.05 268.1 149.43 ;
     RECT  11.34 149.43 35.14 152.79 ;
     RECT  11.34 152.79 34.58 153.35 ;
     RECT  12.46 153.35 34.58 153.91 ;
     RECT  46.42 149.43 268.1 159.13 ;
     RECT  13.02 153.91 34.58 163.99 ;
     RECT  14.14 163.99 34.58 164.73 ;
     RECT  46.42 159.13 272.58 164.73 ;
     RECT  14.14 164.73 272.58 173.51 ;
     RECT  14.7 173.51 272.58 184.15 ;
     RECT  16.38 184.15 272.58 185.22 ;
     RECT  16.94 185.22 272.58 203.93 ;
     RECT  15.26 203.93 272.58 219.43 ;
     RECT  20.86 219.43 272.58 233.05 ;
     RECT  18.62 233.05 272.58 234.17 ;
     RECT  15.26 234.17 272.58 244.81 ;
     RECT  15.26 244.81 273.7 254.19 ;
     RECT  13.02 254.19 273.7 254.71 ;
     RECT  21.42 254.71 273.7 262.27 ;
     RECT  26.46 262.27 273.7 265.35 ;
     RECT  38.22 265.35 273.7 273.19 ;
     RECT  26.46 265.35 26.74 275.43 ;
     RECT  38.22 273.19 38.5 275.99 ;
     RECT  50.54 273.19 273.7 278.04 ;
     RECT  50.54 278.04 53.62 278.18 ;
     RECT  105.98 278.04 106.26 278.23 ;
     RECT  132.86 278.04 133.14 278.23 ;
     RECT  256.06 278.04 258.58 278.23 ;
    LAYER Metal3 ;
     RECT  11.29 149.1 14.09 149.38 ;
     RECT  12.97 163.66 14.09 163.94 ;
     RECT  14.09 149.1 14.65 151.06 ;
     RECT  14.09 163.66 14.65 173.46 ;
     RECT  16.33 128.94 17.45 129.22 ;
     RECT  14.65 147.98 18.01 184.1 ;
     RECT  18.01 145.18 18.57 184.1 ;
     RECT  17.45 128.94 19.13 133.7 ;
     RECT  18.57 145.18 19.13 186.34 ;
     RECT  12.97 254.38 20.25 254.66 ;
     RECT  19.13 128.94 21.37 186.34 ;
     RECT  19.13 198.94 21.37 199.22 ;
     RECT  15.21 219.1 21.37 219.38 ;
     RECT  20.25 244.3 21.37 254.66 ;
     RECT  21.37 9.94 22.79 262.22 ;
     RECT  22.79 126.14 28.47 255.78 ;
     RECT  26.41 275.1 38.17 275.38 ;
     RECT  22.79 47.74 38.73 67.06 ;
     RECT  28.47 183.26 39.29 255.78 ;
     RECT  22.79 100.94 39.85 101.22 ;
     RECT  38.17 112.7 39.85 112.98 ;
     RECT  39.29 183.26 39.85 259.7 ;
     RECT  38.17 275.1 39.85 275.94 ;
     RECT  39.85 100.94 40.41 112.98 ;
     RECT  28.47 126.14 40.41 169.54 ;
     RECT  38.73 47.74 41.86 68.74 ;
     RECT  41.86 47.18 46.37 69.3 ;
     RECT  39.85 81.9 46.37 82.18 ;
     RECT  40.41 100.94 46.37 169.54 ;
     RECT  39.85 183.26 46.37 275.94 ;
     RECT  46.37 14.98 47.79 275.94 ;
     RECT  47.79 177.66 52.17 275.94 ;
     RECT  47.79 100.94 54.79 145.46 ;
     RECT  47.79 36.54 57.59 81.06 ;
     RECT  57.59 36.54 58.15 79.94 ;
     RECT  52.17 177.66 58.89 277.06 ;
     RECT  58.15 36.54 60.57 78.82 ;
     RECT  58.89 177.66 61.69 277.62 ;
     RECT  61.69 176.54 61.74 277.62 ;
     RECT  60.57 33.18 62.81 78.82 ;
     RECT  54.79 102.06 65.61 145.46 ;
     RECT  47.79 158.62 65.61 163.38 ;
     RECT  65.61 102.06 67.85 163.38 ;
     RECT  61.74 176.54 67.85 278.18 ;
     RECT  62.81 31.5 71.37 78.82 ;
     RECT  67.85 97.02 71.37 163.38 ;
     RECT  67.85 174.86 71.37 278.18 ;
     RECT  71.37 9.94 72.79 278.18 ;
     RECT  72.79 14.14 83.91 39.06 ;
     RECT  72.79 58.94 84.47 81.62 ;
     RECT  84.47 67.9 85.03 81.62 ;
     RECT  72.79 97.02 85.21 278.18 ;
     RECT  83.91 16.94 89.13 39.06 ;
     RECT  89.13 16.94 95.85 51.38 ;
     RECT  85.03 67.9 95.85 69.86 ;
     RECT  95.85 16.94 96.37 69.86 ;
     RECT  85.21 81.9 96.37 278.18 ;
     RECT  96.37 14.98 97.79 278.18 ;
     RECT  97.79 28.14 101.83 278.18 ;
     RECT  101.83 29.26 115.45 278.18 ;
     RECT  115.45 18.62 119.93 278.18 ;
     RECT  119.93 17.5 121.37 278.18 ;
     RECT  121.37 9.94 122.79 278.18 ;
     RECT  122.79 67.9 134.49 278.18 ;
     RECT  122.79 17.5 138.97 43.54 ;
     RECT  134.49 57.82 138.97 278.18 ;
     RECT  138.97 17.5 146.37 278.18 ;
     RECT  146.37 14.98 147.79 278.18 ;
     RECT  147.79 21.42 156.71 278.18 ;
     RECT  156.71 22.54 171.37 278.18 ;
     RECT  171.37 9.94 172.79 278.18 ;
     RECT  172.79 36.54 196.37 278.18 ;
     RECT  196.37 14.98 197.79 278.18 ;
     RECT  197.79 36.54 221.37 278.18 ;
     RECT  221.37 9.94 222.79 278.18 ;
     RECT  222.79 37.66 223.3 278.18 ;
     RECT  223.3 37.66 228.39 277.62 ;
     RECT  228.39 57.82 231.19 277.62 ;
     RECT  231.19 58.94 246.37 277.62 ;
     RECT  246.37 14.98 247.79 277.62 ;
     RECT  247.79 63.42 253.59 277.62 ;
     RECT  253.59 67.34 256.01 277.62 ;
     RECT  256.01 67.34 258.63 278.18 ;
     RECT  258.63 67.34 259.75 276.5 ;
     RECT  259.75 67.34 260.87 184.1 ;
     RECT  260.87 144.62 261.99 184.1 ;
     RECT  260.87 67.34 263.11 129.78 ;
     RECT  263.11 67.34 263.67 88.9 ;
     RECT  259.75 197.26 263.67 276.5 ;
     RECT  263.67 68.46 264.23 88.9 ;
     RECT  263.67 197.26 264.23 223.86 ;
     RECT  261.99 147.98 264.79 184.1 ;
     RECT  264.23 209.02 264.79 222.74 ;
     RECT  264.23 68.46 265.35 78.26 ;
     RECT  263.11 107.66 265.35 108.5 ;
     RECT  264.79 159.18 265.35 184.1 ;
     RECT  264.79 213.5 265.35 222.74 ;
     RECT  263.67 235.34 265.91 276.5 ;
     RECT  265.35 107.66 266.47 107.94 ;
     RECT  265.91 235.34 266.47 260.82 ;
     RECT  265.35 68.46 267.59 68.74 ;
     RECT  265.35 222.46 267.59 222.74 ;
     RECT  263.11 126.14 268.15 126.42 ;
     RECT  264.23 197.26 268.15 197.54 ;
     RECT  266.47 235.34 268.15 245.14 ;
     RECT  266.47 260.54 268.15 260.82 ;
     RECT  265.91 273.98 268.66 276.5 ;
     RECT  265.35 159.18 268.71 173.46 ;
     RECT  268.66 273.98 268.71 275.94 ;
     RECT  268.71 273.98 269.27 274.82 ;
     RECT  268.71 173.18 270.39 173.46 ;
     RECT  269.27 273.98 271.51 274.26 ;
     RECT  268.71 159.18 272.63 159.46 ;
     RECT  268.15 244.86 273.75 245.14 ;
    LAYER Metal4 ;
     RECT  221.28 9.78 222.88 47.69 ;
     RECT  196.28 14.82 197.88 60.01 ;
     RECT  192.22 60.01 197.88 63.93 ;
     RECT  187.18 63.93 197.88 67.67 ;
     RECT  96.28 14.82 97.88 72.89 ;
     RECT  191.66 67.67 197.88 76.07 ;
     RECT  192.22 76.07 197.88 78.31 ;
     RECT  96.28 72.89 104.58 82.41 ;
     RECT  193.34 78.31 197.88 89.51 ;
     RECT  146.28 14.82 147.88 108.73 ;
     RECT  171.28 9.78 172.88 110.41 ;
     RECT  121.28 9.78 122.88 113.21 ;
     RECT  171.28 110.41 177.94 121.43 ;
     RECT  71.28 9.78 72.88 123.29 ;
     RECT  94.78 82.41 104.58 123.29 ;
     RECT  121.28 113.21 124.74 123.29 ;
     RECT  94.78 123.29 124.74 133.37 ;
     RECT  141.26 108.73 147.88 140.09 ;
     RECT  221.28 47.69 228.34 159.13 ;
     RECT  246.28 14.82 247.88 169.21 ;
     RECT  171.28 121.43 172.88 171.45 ;
     RECT  246.28 169.21 252.42 172.57 ;
     RECT  71.28 123.29 73.78 179.29 ;
     RECT  71.28 179.29 74.9 179.85 ;
     RECT  60.06 179.85 74.9 180.79 ;
     RECT  171.28 171.45 174.02 185.83 ;
     RECT  221.28 159.13 229.46 188.25 ;
     RECT  246.28 172.57 254.66 188.25 ;
     RECT  141.26 140.09 149.38 191.61 ;
     RECT  94.22 133.37 124.74 193.29 ;
     RECT  196.28 89.51 197.88 194.41 ;
     RECT  60.06 180.79 73.78 195.91 ;
     RECT  140.14 191.61 149.38 202.07 ;
     RECT  221.28 188.25 254.66 205.05 ;
     RECT  94.22 193.29 125.86 207.67 ;
     RECT  46.28 14.82 47.88 207.85 ;
     RECT  60.06 195.91 72.88 207.85 ;
     RECT  192.78 194.41 197.88 214.57 ;
     RECT  146.28 202.07 149.38 217.75 ;
     RECT  94.22 207.67 107.94 219.61 ;
     RECT  119.98 207.67 125.86 219.61 ;
     RECT  94.22 219.61 125.86 222.41 ;
     RECT  146.28 217.75 147.88 222.41 ;
     RECT  191.66 214.57 197.88 224.65 ;
     RECT  219.1 205.05 254.66 224.65 ;
     RECT  191.66 224.65 254.66 225.21 ;
     RECT  191.1 225.21 254.66 226.33 ;
     RECT  191.1 226.33 258.02 226.89 ;
     RECT  186.62 226.89 258.02 227.45 ;
     RECT  92.54 222.41 125.86 229.69 ;
     RECT  84.14 229.69 125.86 233.05 ;
     RECT  143.5 222.41 147.88 233.05 ;
     RECT  186.06 227.45 258.02 233.99 ;
     RECT  46.28 207.85 72.88 234.17 ;
     RECT  84.14 233.05 147.88 234.17 ;
     RECT  171.28 185.83 172.88 234.26 ;
     RECT  46.28 234.17 147.88 235.67 ;
     RECT  46.28 235.67 72.88 236.79 ;
     RECT  86.38 235.67 147.88 241.27 ;
     RECT  60.06 236.79 72.88 244.63 ;
     RECT  88.06 241.27 147.88 244.63 ;
     RECT  186.06 233.99 208.18 245.19 ;
     RECT  186.62 245.19 208.18 246.31 ;
     RECT  96.28 244.63 147.88 250.41 ;
     RECT  191.66 246.31 208.18 252.65 ;
     RECT  221.28 233.99 258.02 252.65 ;
     RECT  191.66 252.65 258.02 254.71 ;
     RECT  96.28 250.41 149.94 260.31 ;
     RECT  96.28 260.31 148.82 260.87 ;
     RECT  21.28 9.78 22.88 262.38 ;
     RECT  71.28 244.63 72.88 262.38 ;
     RECT  165.9 234.26 172.88 262.38 ;
     RECT  221.28 254.71 258.02 262.38 ;
     RECT  46.28 236.79 47.88 267.42 ;
     RECT  96.28 260.87 147.88 267.42 ;
     RECT  226.38 262.38 258.02 267.42 ;
     RECT  102.06 267.42 144.9 268.71 ;
     RECT  191.66 254.71 208.18 273.86 ;
     RECT  226.38 267.42 235.62 273.86 ;
     RECT  77.42 273.93 77.7 274.49 ;
     RECT  75.46 274.49 77.7 275.09 ;
     RECT  102.06 268.71 142.66 276.55 ;
     RECT  76.3 275.09 77.7 277.11 ;
     RECT  191.66 273.86 235.62 277.11 ;
     RECT  76.3 277.11 76.58 277.67 ;
     RECT  102.06 276.55 120.26 277.67 ;
     RECT  134.54 276.55 142.66 277.67 ;
     RECT  165.9 262.38 166.18 277.67 ;
     RECT  191.66 277.11 217.7 277.67 ;
     RECT  235.34 277.11 235.62 277.67 ;
     RECT  257.74 267.42 258.02 277.67 ;
     RECT  116.62 277.67 116.9 277.84 ;
     RECT  136.22 277.67 136.5 277.84 ;
     RECT  206.22 277.67 206.5 277.84 ;
    LAYER Metal5 ;
     RECT  101.98 276.53 111.5 276.97 ;
     RECT  111.5 273.83 116.54 276.97 ;
     RECT  116.54 273.83 124.38 277.87 ;
     RECT  124.38 272.03 124.94 277.87 ;
     RECT  124.94 271.13 141.62 277.87 ;
     RECT  141.62 272.03 142.74 277.87 ;
     RECT  84.06 234.23 166.26 234.67 ;
     RECT  142.74 273.83 206.58 277.87 ;
     RECT  206.58 273.83 213.3 276.07 ;
     RECT  213.3 273.83 217.78 274.27 ;
  END
END adder_tester
END LIBRARY
